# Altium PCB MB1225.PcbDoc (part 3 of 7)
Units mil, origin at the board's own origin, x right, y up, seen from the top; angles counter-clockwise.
Board outline 5000 x 3464.56 mil, 6 copper layers (Top Layer, L2_GND, L3_VCC, L4_SIG, L5_GND, Bottom Layer), stack 62.2 mil thick; 453 components, 378 nets, 1982 pads, 949 vias.

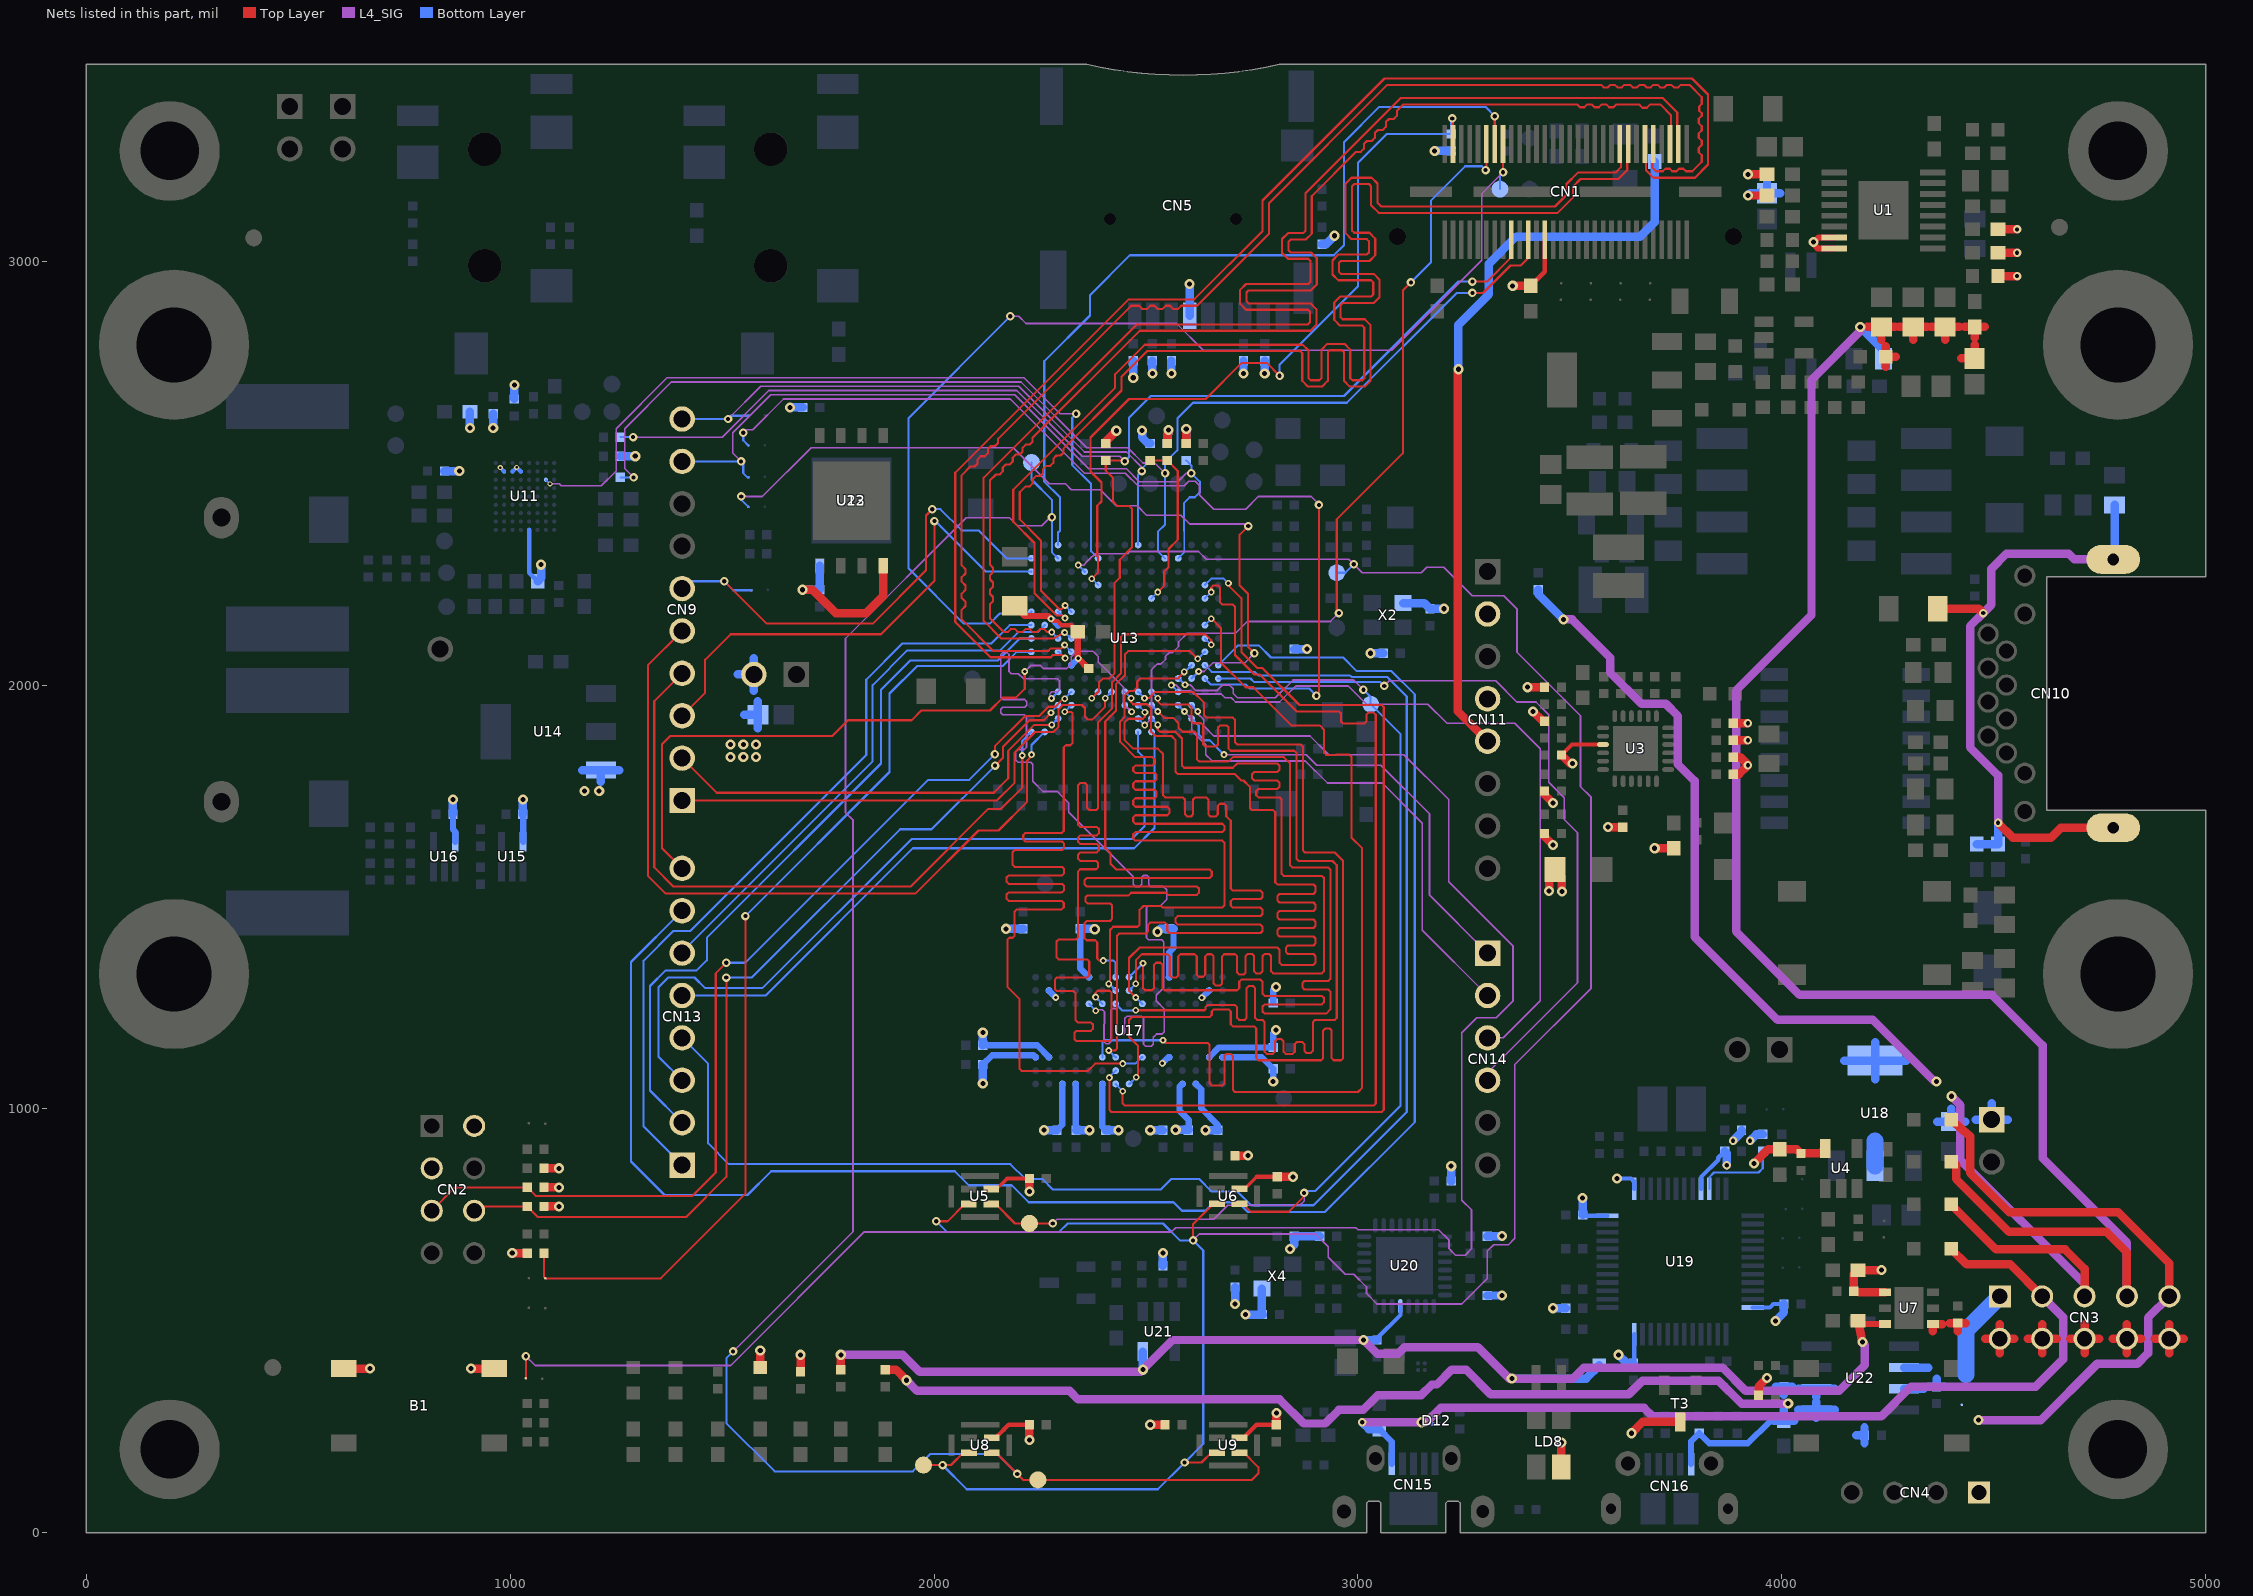
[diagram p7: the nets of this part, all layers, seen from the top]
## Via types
v1: diameter 20, hole 10, Top Layer to Bottom Layer, 354 vias
v2: diameter 24, hole 12, Top Layer to Bottom Layer, 347 vias
v3: diameter 16, hole 8, Top Layer to Bottom Layer, 221 vias
v4: diameter 12, hole 6, Top Layer to Bottom Layer, 27 vias

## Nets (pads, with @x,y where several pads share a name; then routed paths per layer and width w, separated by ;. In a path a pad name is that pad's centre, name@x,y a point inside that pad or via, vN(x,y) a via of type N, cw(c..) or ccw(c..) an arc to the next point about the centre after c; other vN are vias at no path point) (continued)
3V3: B1.1 B1.4 C1.2 C33.2 C38.1 C44.1 C45.1 C48.2 C49.2 C55.1 C56.1 C65.1 C67.2 C71.1 C92.1 C96.2 C98.2 C117.2 C118.2 C123.2 C124.2 C125.2 C126.2 C127.2 C128.2 C130.2 C131.2 C133.2 C134.2 C135.2 C136.2 C137.2 C138.2 C144.1 C147.1 CN1.36 CN2.2 CN2.3 CN5.4 CN11.2 CN11.4 JP4.2 L2.2 R8.1 R17.2 R19.1 R20.1 R30.2 R34.2 R35.1 R37.1 R39.1 R41.1 R43.2 R45.2 R47.2 R51.2 R52.2 R54.1 R56.1 R65.2 R66.2 R67.2 R71.2 R76.2 R79.2 R80.2 R81.2 R82.2 R83.2 R86.2 R87.2 R89.1 R90.1 R91.1 R94.2 R106.2 R107.1 R109.2 R123.2 R125.2 R126.2 R130.1 R134.1 R137.2 R200.1 U3.9 U5.1 U6.1 U7.4 U8.1 U9.1 U11.B2 U11.C2 U11.D2 U11.E9 U12.8 U14.3 U15.5 U16.5 U17.A7 U17.B2 U17.B7 U17.C9 U17.D9 U17.E1 U17.F9 U17.L1 U17.L7 U17.M9 U17.N9 U17.P2 U17.P7 U17.R7 U23.8 X2.4 X4.4 | length 6354.3
  Top Layer w8: U5.1@2145.89,809.28 2172.61,836 ; U6.1@2730.73,809.28 2761.45,840
  Top Layer w10: U8.1@2136,224.67 2145.67,224.67 2159.05,238.05 2159.27,238.05 2165.71,244.49 2165.71,244.71 2176,255 C55.1@2225,255 ; U5.1@2136,809.28 U5.1@2145.89,809.28 ; 2172.61,836 C44.1@2225,836 ; U9.1@2720.61,224.67 2730.5,224.67 2760.83,255 C56.1@2807.57,255 ; U6.1@2720.61,809.28 U6.1@2730.73,809.28 ; 2761.45,840 C45.1@2810,840 ; C1.2@3407.51,2941.92 3440.78,2975.19 CN1.36@3440.78,3050.55 ; C33.2@3480,1835 3504.84,1859.84 U3.9@3578.23,1859.84
  Top Layer w20: B1.4@607.83,387.5 v2(669.5,387.5) ; v2(907.5,387.5) B1.1@962.17,387.5 ; v2(1005,660) R52.2@1040,660 ; R54.1@1080,770 v2(1115,770) ; R56.1@1080,815 v2(1115,815) ; R200.1@1080,860 v2(1115,860) ; R65.2@1590,390 v2(1590,430) ; R66.2@1685,380 v2(1685,420) ; v2(1690,2225) 1713,2225 1768,2170 1840,2170 1880,2210 U23.8@1880,2281.9 ; v2(2225,219) C55.1@2225,255 ; C44.1@2225,836 2225,805.29 v2(2225.29,805.29) ; R17.2@2405,2570 2405,2575 v2(2430,2600) ; v2(2510,255) R71.2@2545,255 ; R19.1@2550,2570 2550,2590 2553,2593 v2(2553,2602) ; R20.1@2595,2570 v2(2595,2604) ; R51.2@2710,890 v2(2741,890) ; C56.1@2807.57,255 v2(2807.57,283) ; C45.1@2810,840 v2(2847,840) ; v2(3365,2941.92) C1.2@3407.51,2941.92 ; v2(3400,1995) R30.2@3440,1995 ; v2(3413,1938) 3436,1915 R34.2@3440,1915 ; R47.2@3440,1650 3440,1643 v2(3460,1623) ; R43.2@3440,1750 3440,1742 v2(3460,1722) ; v2(3451,1514) C38.1@3451,1544 ; C38.1@3451,1551 C38.1@3465,1565 3481,1549 v2(3481,1513) ; C33.2@3480,1835 3500,1815 v2(3506,1815) ; v2(3590,1665) R45.2@3625,1665 ; v2(3700,1615) L2.2@3745,1615 ; R41.1@3885,1790 3899,1790 v1(3920,1811) 3920,1812 3902,1830 R39.1@3885,1830 ; R37.1@3885,1870 v1(3920,1870) ; R35.1@3885,1910 v1(3920,1910) ; R67.2@3945,325 3945,345 v2(3965,365) ; v2(4235,620) C48.2@4180,620 4170,610 C49.2@4170,570 4182.6,567.4 U7.4@4243.48,567.4
  Bottom Layer w9: v4(976.54,2513.25) 985.73,2504.06 U11.B2@985.79,2504.06 ; U11.C2@1005.47,2504.06 U11.C2@1005.47,2504.06 v4(1015.22,2513.76)
  Bottom Layer w10: v4(1015.22,2513.76) 1024.92,2504.06 U11.D2@1025.16,2504.06 ; U11.E9@1044.84,2366.26 1044.84,2265.16 C92.1@1065,2245
  Bottom Layer w15: C118.2@865,1695 865,1660 870.59,1654.41 U16.5@870.59,1630.43 ; C117.2@1030,1695 1030.59,1694.41 U15.5@1030.59,1630.43 ; C130.2@2115,1105 2137,1127 2234.54,1127 U17.A7@2239.53,1122.01 ; C127.2@2115,1150 2243.03,1150 U17.B7@2271.02,1122.01 ; U17.B2@2271.02,1279.49 2271.02,1278.98 v3(2287,1263) ; C138.2@2290,950 2302.52,962.52 U17.C9@2302.52,1059.02 ; U17.D9@2334.02,1059.02 2334.02,950.98 C137.2@2335,950 ; C124.2@2345,1425 2345,1331.49 U17.E1@2365.51,1310.98 ; U17.F9@2397.01,1059.02 2397.01,957.99 C136.2@2405,950 ; v3(2538.61,1108) 2552.62,1122.01 U17.L7@2554.49,1122.01 ; U17.L1@2554.49,1310.98 2554.49,1369.49 2565,1380 C123.2@2565,1425 ; U17.M9@2585.98,1059.02 2579,1052.04 2579,996 2600.84,974.16 2600.84,950.84 C134.2@2600,950 ; U17.N9@2617.48,1059.02 2630,1046.5 2630,1002 2670,962 C133.2@2670,950 ; v3(2631.92,1262.43) U17.P2@2648.98,1279.49 ; U17.P7@2648.98,1122.01 2671.97,1145 C128.2@2800,1145 2800,1179 v2(2807,1186) ; U17.R7@2680.47,1122.01 2772.99,1122.01 C131.2@2800,1095 v2(2800,1065) ; C126.2@2800,1250 2800,1281 v2(2807,1288)
  Bottom Layer w20: C71.1@845,2505 v2(880,2505) ; C118.2@865,1695 v2(865,1730) ; v2(905,2606.83) C67.2@905,2645 ; v2(960,2606.83) C65.1@960,2640 ; R87.2@1010,2675 v2(1010,2707.91) ; C117.2@1030,1695 v2(1030,1730) ; C92.1@1065,2245 1073,2253 v2(1073,2284) ; 1170.5,1799.45 U14.3@1214.02,1799.45 ; 1214.02,1771.43 U14.3@1214.02,1799.45 ; 1257.54,1799.45 U14.3@1214.02,1799.45 ; R94.2@1260,2540 v2(1295,2540) ; 1536.98,2025 JP4.2@1575,2025 ; 1551.97,1930 R109.2@1584.49,1930 ; 1575,1986.98 JP4.2@1575,2025 ; 1575,2063.02 JP4.2@1575,2025 ; 1584.49,1898.48 R109.2@1584.49,1930 ; 1584.49,1961.52 R109.2@1584.49,1930 ; v2(1660,2655) R86.2@1690,2655 ; v2(1690,2225) C96.2@1730,2225 U12.8@1730,2281.46 ; v2(2115,1060) C130.2@2115,1105 ; C127.2@2115,1150 v2(2115,1180) ; v2(2170,1425) C125.2@2210,1425 ; v2(2259,950) C138.2@2290,950 ; C137.2@2335,950 v2(2367,950) ; C124.2@2345,1425 2378,1425 v2(2379,1424) ; C136.2@2405,950 v2(2435,950) ; v2(2470,2725) R83.2@2470,2765 ; v2(2490.82,2600.29) 2490.82,2584.18 2505,2570 R91.1@2510,2570 ; v2(2510,950) C135.2@2540,950 ; v2(2515,2735) R82.2@2515,2765 ; v2(2527,1418) 2534,1425 C123.2@2555,1425 C123.2@2565,1425 ; R130.1@2540,630 v2(2540,660) ; R90.1@2550,2570 2550,2590 2553,2593 v2(2553,2602) ; v2(2560,2735) R81.2@2560,2765 ; v2(2570,950.84) C134.2@2600.84,950.84 ; R89.1@2595,2570 v2(2595,2604) ; CN5.4@2602.99,2871.21 v2(2602.99,2946) ; v2(2640,950) C133.2@2670,950 ; v2(2710,540) R134.1@2710,580 ; v2(2730,2735) R80.2@2730,2765 ; v2(2735,515) C147.1@2775,515 2773.58,516.42 X4.4@2773.58,576.46 ; v2(2780,2735) R79.2@2780,2765 ; v2(2840,670) 2850,680 C144.1@2850,700 R126.2@2910,700 ; R106.2@2850,2085 v2(2880,2085) ; R76.2@2915,3040 2925,3040 v2(2945,3060) ; v2(3030,2075) R107.1@3060,2075 ; X2.4@3106.42,2193.54 3156.46,2193.54 C98.2@3170,2180 v2(3203.12,2180) ; v2(3181,3260) R8.1@3220,3260 ; R123.2@3220,830 v2(3220,865) ; R137.2@3305,560 v2(3340,560) ; R125.2@3305,700 v2(3340,700)
  other v2: 1175,1750 1210,1750 1520,1830 1550,1830 1580,1830 1520,1860 1550,1860 1580,1860
3V3_ST_LINK: C41.1 C42.2 C140.1 C143.2 C146.2 C151.2 CN4.1 LD8.4 R118.2 R120.1 R138.2 T3.3 U4.5 U19.1 U19.9 U19.24 U19.36 U19.48 | length 1019.4
  Top Layer w20: LD8.4@3479.53,155.94 v2(3479.53,213) ; v2(3645,235) 3671.69,261.69 T3.3@3760,261.69 ; v2(3933.98,871.31) 3967.67,905 C41.1@3995,905 4035,905 C42.2@4045,895 4090.36,895 U4.5@4102.6,907.24
  Bottom Layer w10: C143.2@3530,750 3531.73,748.27 U19.48@3588.74,748.27 ; v2(3611,836) 3644,836 3651.73,828.27 U19.1@3651.73,811.26 ; C151.2@3650,400 3651.73,401.73 U19.36@3651.73,468.74 ; U19.9@3809.21,811.26 3809.21,839.21 3850,880 3850,885 C140.1@3865,900 ; U19.24@3931.26,531.73 3971.73,531.73 3980,540 C146.2@4005,540
  Bottom Layer w20: v2(3460,530) R138.2@3490,530 ; C143.2@3530,750 v2(3530,790) ; v2(3615,420) 3635,400 C151.2@3650,400 ; C140.1@3865,900 3870,895 v1(3870,867.5) ; v1(3885,925) 3905,945 R118.2@3905,950 ; v1(3925,925) 3940,940 R120.1@3955,940 ; v2(3985,500) 4005,520 C146.2@4005,540
5V: C50.2 C51.2 C150.1 CN3.2 CN3.4 CN3.6 CN3.8 CN3.10 CN11.5 D11.1 L4.1 R58.1 U7.1 U7.6 U20.21 U21.5 | length 5713.9
  Top Layer w15: C51.2@4180,500 4197.4,492.6 U7.6@4243.48,492.6
  Top Layer w20: R58.1@1780,385 v2(1780,420) ; v2(3237,2745) 3235,2743 3235,1938.5 CN11.5@3305.8,1867.7 ; C51.2@4180,500 v2(4190,450) ; 4356.52,475.58 U7.1@4356.52,492.6 4378.54,492.6 ; 4395.98,495 C50.2@4415,495 ; 4415,475.98 C50.2@4415,495 ; 4434.02,495 C50.2@4415,495 ; 4480.2,458 CN3.2@4514.22,458 ; 4514.22,423.98 CN3.2@4514.22,458 ; 4514.22,492.02 CN3.2@4514.22,458 ; 4548.24,458 CN3.2@4514.22,458 ; 4580.2,458 CN3.4@4614.22,458 ; 4614.22,423.98 CN3.4@4614.22,458 ; 4614.22,492.02 CN3.4@4614.22,458 ; 4648.24,458 CN3.4@4614.22,458 ; 4680.2,458 CN3.6@4714.22,458 ; 4714.22,423.98 CN3.6@4714.22,458 ; 4714.22,492.02 CN3.6@4714.22,458 ; 4748.24,458 CN3.6@4714.22,458 ; 4780.2,458 CN3.8@4814.22,458 ; 4814.22,423.98 CN3.8@4814.22,458 ; 4814.22,492.02 CN3.8@4814.22,458 ; 4848.24,458 CN3.8@4814.22,458 ; 4880.2,458 CN3.10@4914.22,458 ; 4914.22,423.98 CN3.10@4914.22,458 ; 4914.22,492.02 CN3.10@4914.22,458 ; 4948.24,458 CN3.10@4914.22,458
  L4_SIG w20: v2(1780,420) 1926,420 1966,380 2487.6,380 v2(2492.6,385) 2562.6,455 v2(3013,455) 3045,423 3095.13,423 3110.13,438 3283,438 3357,364 v2(3363,364) 3507,364 3533,390 3860,390 3915,335 4135,335 4196,396 4196,444 v2(4190,450)
  Bottom Layer w10: C150.1@3045,455 3045,459 3100.16,514.16 U20.21@3100.16,534.72
  Bottom Layer w20: v2(2492.6,385) U21.5@2492.6,427.76 ; v2(3013,455) C150.1@3045,455 ; v2(3237,2745) 3237,2850 3309,2922 3309,2994 3373,3058 3666,3058 3700,3092 L4.1@3700,3235 ; v2(3363,364) 3538.29,364 D11.1@3569.29,395
5V_POE: C13.2 C14.2 C15.2 C16.2 CN3.7 D6.1 R11.2 R16.2 R84.2 | length 4278.5
  Top Layer w20: 4201.98,2845 C13.2@4235,2845 ; 4235,2814.48 C13.2@4235,2845 ; 4245,2750.98 R11.2@4245,2775 ; 4245,2799.02 R11.2@4245,2775 ; 4268.02,2845 C13.2@4235,2845 ; 4268.52,2775 R11.2@4245,2775 ; 4276.98,2845 C14.2@4310,2845 ; 4310,2814.48 C14.2@4310,2845 ; 4343.02,2845 C14.2@4310,2845 ; 4351.98,2845 C15.2@4385,2845 ; 4385,2814.48 C15.2@4385,2845 ; D6.1@4399.29,875 4411,868.29 4411,835 4536,710 4766,710 4814.22,661.78 CN3.7@4814.22,558 ; 4418.02,2845 C15.2@4385,2845 ; 4423.48,2770.51 R16.2@4455,2770.51 4455,2803.03 ; 4430.98,2845 C16.2@4455,2845 ; 4455,2819.48 C16.2@4455,2845 ; 4479.02,2845 C16.2@4455,2845
  L4_SIG w20: v2(4185,2845) 4185,2835 4070,2720 4070,2165 3892,1987 3892,1419 4042,1269 4496,1269 4615,1150 4615,884 4814.22,684.78 CN3.7@4814.22,558
  Bottom Layer w20: v2(4185,2845) 4240,2790 R84.2@4240,2770
5V_ST_LINK: C152.2 CN3.1 SB23.2 U22.6 U22.7 | length 378.7
  Bottom Layer w20: U22.7@4288.3,340 4335,340 ; U22.6@4288.3,390 4345.98,390 ; 4345.98,345 C152.2@4365,345 ; 4365,364.02 C152.2@4365,345 ; 4384.02,345 C152.2@4365,345
  Bottom Layer w40: 4434,374 4434,477.78 CN3.1@4514.22,558
5V_USB_CHARGER: C155.2 CN3.9 CN16.1 D5.1 R59.2 R144.2 R147.2 R150.2 SB23.1 U22.1 U22.2 | length 4390.4
  Top Layer w20: R59.2@1885,385 1910,385 v2(1935,360) ; D5.1@4399.29,975 4444,935.29 4444,849 4537,756 4794,756 4914.22,635.78 CN3.9@4914.22,558
  L4_SIG w20: v2(1935,360) 1960,335 2320,335 2340,315 2815,315 2872,258 2923,258 2955,290 3012,290 3047,325 3149.49,325 3174.49,350 3186.4,350 3221.4,385 3255,385 3313,327 3639,327 3671,359 3851,359 3905,305 v2(4015,305) ; v2(4464,266) 4611,266 4744,399 4839,399 4864,424 4864,507.78 CN3.9@4914.22,558
  Bottom Layer w14: CN16.1@3786.18,162.4 3786.18,216.18 R147.2@3805,235
  Bottom Layer w15: R147.2@3805,235 3829,211 3920,211 3970,261
  Bottom Layer w20: 3980.98,265 C155.2@4005,265 ; 3985.98,345 R144.2@4005,345 ; 4005,290.52 C155.2@4005,265 ; 4005,325.98 R144.2@4005,345 ; 4024.02,345 R144.2@4005,345 ; 4029.02,265 C155.2@4005,265 ; 4038.68,290 U22.1@4081.7,290 ; 4038.68,340 U22.2@4081.7,340 ; 4081.7,270.98 U22.1@4081.7,290 ; 4081.7,309.02 U22.1@4081.7,290 ; 4081.7,320.98 U22.2@4081.7,340 ; 4124.72,290 U22.1@4081.7,290 ; 4124.72,340 U22.2@4081.7,340 ; 4175.98,230 R150.2@4195,230 ; 4195,210.98 R150.2@4195,230 ; 4195,249.02 R150.2@4195,230
5V_USB_HS: CN3.3 CN15.1 D8.1 D12.A1 L7.2 | length 2332.1
  Top Layer w20: D8.1@4399.29,670 4436.15,633.14 4539.08,633.14 CN3.3@4614.22,558
  L4_SIG w20: v1(3010,261) v2(3150,261) 3161.03,261 3194.98,295 3675,295 3695,275 4235,275 4305,345 4599,345 4664,410 4664,508.22 CN3.3@4614.22,558
  Bottom Layer w8: v2(3150,261) 3153.87,257.13 D12.A1@3177.13,257.13
  Bottom Layer w15: L7.2@3050,245 3079.69,215.31 CN15.1@3079.69,162.8
  Bottom Layer w20: v1(3010,261) 3026,245 L7.2@3050,245
AGND: C6.1 C7.1 C10.2 C11.2 R6.2 R74.2 U1.15 U1.16 | length 447.6
  Top Layer w14: U1.16@4123.86,3030.43 4084.57,3030.43 4075,3040 v2(4075,3045) 4086.02,3056.02 U1.15@4123.86,3056.02
  Top Layer w20: v2(3920,3155) C7.1@3965,3155 ; v2(3920,3205) C6.1@3965,3205 ; R6.2@4510,2965 v1(4555,2965) ; C11.2@4510,3020 v1(4555,3020) ; C10.2@4510,3075 v1(4555,3075)
  Bottom Layer w20: v2(3920,3155) 3925.51,3160.51 R74.2@3965,3160.51 ; 3965,3193.03 R74.2@3965,3160.51 ; 3996.52,3160.51 R74.2@3965,3160.51
AIN_1: R119.2 R120.2 U19.10 | length 247.5
  Bottom Layer w5: U19.10@3828.9,811.26 3828.9,838.9 3840,850 3945,850 3955,860 R120.2@3955,900 R119.2@4000,900
ARD_A0: CN14.1 U13.P3 | length 1051.7
  L4_SIG w4: v3(2684,1836) 2878,1836 2903,1811 3054,1811 3169,1696 3169,1504.5 CN14.1@3305.8,1367.7
  Bottom Layer w5: U13.P3@2607.48,1921.02 2624.48,1904.02 2624.48,1883.52 2638,1870 2650,1870 v3(2684,1836)
ARD_A1: CN14.2 U13.N4 | length 1191.6
  L4_SIG w4: v3(2590.83,1937.67) 2608,1920.5 2608,1892 2641,1859 2641,1836 2656,1821 2876,1821 2928,1769 3057,1769 3152,1674 3152,1421.5 CN14.2@3305.8,1267.7
  Bottom Layer w5: U13.N4@2575.98,1952.52 v3(2590.83,1937.67)
ARD_A2: CN14.3 U13.M4 | length 1741.6
  L4_SIG w4: v3(2560,2000) 2571.41,2000 2585.2,1986.21 2605.47,1986.21 2612.68,1979 2677.22,1979 2686.2,1970.02 2700.98,1970.02 2711,1960 2815,1960 2853,1998 2977,1998 3020,1955 3165,1955 3210,1910 3370,1910 3430,1850 3430,1255 3342.7,1167.7 CN14.3@3305.8,1167.7
  Bottom Layer w5: v3(2560,2000) U13.M4@2575.98,1984.02
ARD_A3: CN14.4 U13.L1 | length 1803.3
  L4_SIG w4: v1(3062,1998) 3074,2010 3325,2010 3375,1960 3420,1960 3450,1930 3450,1771 3487,1734 3487,1683 3518,1652 3518,1298 3305.8,1085.8 CN14.4@3305.8,1067.7
  Bottom Layer w5: U13.L1@2670.47,2015.51 2746.49,2015.51 2755,2007 3053,2007 v1(3062,1998)
ARD_A4: SB14.1 U13.L3 | length 1847.5
  Top Layer w5: v1(2741,2375) 2721,2355 2721,2235 2741,2215 2741,2089.77 v1(2755.75,2075.02)
  L4_SIG w4: v1(1545,2445) 1595,2445 1710,2560 2187,2560 2272,2475 2310,2475 2324,2461 2392,2461 2430,2423 2479,2423 2501.16,2400.84 2582.16,2400.84 2603,2380 2736,2380 v1(2741,2375) ; v3(2624,2032) 2637,2032 2658,2053 2733.73,2053 v1(2755.75,2075.02)
  Bottom Layer w5: v1(1545,2445) 1545,2437.32 SB14.1@1561.99,2420.33 ; U13.L3@2607.48,2015.51 2616.96,2024.99 ; 2616.99,2024.99 v3(2624,2032)
ARD_A5: SB12.1 U13.L2 | length 2310.3
  Top Layer w5: v1(2902,1975) 2903,1975 2908,1980 v1(2908,2425.01)
  L4_SIG w4: v1(1550,2595) 1557.5,2602.5 1572.5,2602.5 1645,2675 2180,2675 2355,2500 2451.22,2500 2481.22,2470 2590,2470 2601,2481 2616.05,2481 2626,2471.05 2626,2449 2660,2415 2735,2415 2765,2445 2890,2445 2908,2427 v1(2908,2425.01)
  Bottom Layer w5: v1(1550,2595) 1550,2577.32 SB12.1@1561.99,2565.33 ; U13.L2@2638.98,2015.51 2653.49,2001 2736,2001 2745,1992 2885,1992 v1(2902,1975)
ARD_D0: CN13.1 U13.G15 | length 1866.6
  Bottom Layer w5: CN13.1@1405.8,867.7 1315,958.5 1315,1350 1385,1420 1425,1420 1840,1835 1840,2013 1925,2098 2135,2098 2178.5,2141.5 U13.G15@2229.53,2141.5
ARD_D1: CN13.2 U13.H15 | length 1725.9
  Bottom Layer w5: CN13.2@1405.8,967.7 1330,1043.5 1330,1290 1367,1327 1440,1327 1464,1351 1464,1404 1875,1815 1875,1989 1944,2058 2150,2058 2202,2110 U13.H15@2229.53,2110
ARD_D2: CN13.3 U13.R7 | length 1795.4
  Bottom Layer w5: CN13.3@1405.8,1067.7 1350,1123.5 1350,1287 1373,1310 1435,1310 1460,1285 1595,1285 1947,1637 2466,1637 2496.35,1667.35 2496.35,1827.65 2481.5,1842.5 U13.R7@2481.5,1889.53
ARD_D3: CN13.4 U13.K2 | length 3581
  Bottom Layer w5: CN13.4@1405.8,1167.7 1467,1106.5 1467,919 1516,870 2180,870 2215,835 2255,835 2280,810 2535,810 2560,835 2625,835 2655,805 2716,805 2748,773 2895,773 3115,993 3115,1973 3069,2019 2985,2019 2981,2023 2765,2023 2756.9,2031.1 2654.89,2031.1 U13.K2@2638.98,2047.01
ARD_D4: CN13.5 U13.R6 | length 1507.4
  Bottom Layer w5: CN13.5@1405.8,1267.7 1602.7,1267.7 1950,1615 2472,1615 2520,1663 2520,1882.52 U13.R6@2512.99,1889.53
ARD_D5: CN13.6 U13.G14 | length 1283
  Bottom Layer w5: CN13.6@1405.8,1367.7 1405.8,1370.8 1855,1820 1855,2000 1937,2082 2156,2082 2199,2125 2244.52,2125 U13.G14@2261.02,2141.5
ARD_D6: CN13.7 U13.K1 | length 4230
  Bottom Layer w5: CN13.7@1405.8,1467.7 1285,1346.9 1285,876 1364,797 1560,797 1616,853 2049,853 2082,820 2183,820 2223,780 2565,780 2585,760 2640,760 2660,780 2717,780 2740,757 2922,757 3134,969 3134,1978 3079,2033 2997,2033 2965,2065 2795,2065 2767,2093 2716.46,2093 U13.K1@2670.47,2047.01
ARD_D7: CN13.8 U13.N8 | length 1663.7
  Top Layer w5: CN13.8@1405.8,1567.7 1358,1615.5 1358,1860 1378,1880 1760,1880 1797,1917 1947,1917 1970,1940 2132,1940 2162,1970 2193,1970 2214,1991 v3(2214,2032)
  L4_SIG w4: v3(2214,2032) 2228,2046 2251,2046 2258,2039 2313,2039 2324,2050 2324,2067 2337,2080 2375,2080 2387.5,2067.5 2387.5,2054.5 2447,1995 2447,1955 2465,1937 v3(2466,1937)
  Bottom Layer w4: U13.N8@2450,1952.52 2450.48,1952.52 v3(2466,1937)
ARD_D8: CN9.1 U13.M9 | length 1237
  Top Layer w5: CN9.1@1405.8,1727.7 2147.7,1727.7 2190,1770 2190,1841 2238.25,1889.25 2281.26,1889.25 2294,1901.99 2294,1942.99 2304.01,1953 2349,1953 2356,1946 2356,1925 2362,1919 2374,1919 2403.65,1948.65 v3(2403.65,1969.17)
  Bottom Layer w5: v3(2403.65,1969.17) U13.M9@2418.5,1984.02
ARD_D9: CN9.2 U13.P13 | length 1031
  Top Layer w5: CN9.2@1405.8,1827.7 1487.5,1746 2141,1746 2175.08,1780.08 2175.08,1844.92 2236.33,1906.17 v3(2277.67,1906.17)
  Bottom Layer w5: v3(2277.67,1906.17) U13.P13@2292.52,1921.02
ARD_D10: CN9.3 U13.C15 | length 1191.8
  Top Layer w5: CN9.3@1405.8,1927.7 1460,1981.9 1460,2060 1520,2120 1875,2120 2001,2246 v1(2001,2387)
  Bottom Layer w5: v1(2001,2387) 2003,2387 2122,2268 2229.01,2268 U13.C15@2229.53,2267.48
ARD_D11: CN9.4 U13.R15 | length 1608.6
  Top Layer w5: CN9.4@1405.8,2027.7 1340,1961.9 1340,1570 1385,1525 1945,1525 2128,1708 2158,1708 2208,1758 v3(2208,1834)
  Bottom Layer w5: v3(2208,1834) 2208,1868 U13.R15@2229.53,1889.53
ARD_D12: CN9.5 U13.R14 | length 1795
  Top Layer w5: CN9.5@1405.8,2127.7 1325,2046.9 1325,1550 1367,1508 1956,1508 2105,1657 2152,1657 2219,1724 2219,1821 2230,1832 v3(2230,1836)
  Bottom Layer w5: v3(2230,1836) 2230,1858.51 U13.R14@2261.02,1889.53
ARD_D13: CN9.6 SB15.2 U13.B15 | length 1180.7
  Top Layer w5: v1(1505,2245) 1605,2145 1855,2145 1981,2271 1981,2400 v1(1996,2415)
  Bottom Layer w5: CN9.6@1405.8,2227.7 1423.1,2245 v1(1505,2245) 1526.19,2223.81 SB15.2@1569.17,2223.81 ; v1(1996,2415) 2015,2415 2065,2365 2105,2365 2171.02,2298.98 U13.B15@2229.53,2298.98
ARD_D14: CN9.9 R89.2 SB13.1 U13.B4 | length 1745.1
  L4_SIG w4: v1(1544.67,2527.7) 1525,2547.37 1525,2595 1615,2685 2190,2685 2365,2510 2453.95,2510 2483.95,2480 2575,2480 2595,2500 v1(2607,2500)
  Bottom Layer w4: U13.B4@2575.98,2298.98 2590,2313 2590,2364
  Bottom Layer w5: CN9.9@1405.8,2527.7 v1(1544.67,2527.7) 1550,2522.37 1550,2500 1559.67,2490.33 SB13.1@1561.99,2490.33 ; 2590,2364 2590,2430 2603,2443 2615,2443 2627,2455 2627,2480 v1(2607,2500) 2607,2518 R89.2@2595,2530
ARD_D15: CN9.10 R91.2 SB11.1 U13.A7 | length 1466.8
  L4_SIG w4: v1(1514,2627.7) 1591.3,2705 2200,2705 2355,2550 2454,2550 2490,2514 v1(2490,2505)
  Bottom Layer w5: CN9.10@1405.8,2627.7 v1(1514,2627.7) 1521.63,2635.33 SB11.1@1561.99,2635.33 ; U13.A7@2481.5,2330.47 2481.5,2496.5 v1(2490,2505) 2490,2510 R91.2@2510,2530
Audio_INT: U11.G3 U13.B10 | length 1826.2
  L4_SIG w3.5: v4(1093.96,2474.62) 1115.38,2474.62 1120,2470
  L4_SIG w4: 1120,2470 1215,2470 1250,2505 1250,2605 1370,2725 2212.06,2725 2297.06,2640 v1(2335,2640)
  Bottom Layer w3.5: U11.G3@1084.21,2484.37 v4(1093.96,2474.62)
  Bottom Layer w5: v1(2335,2640) 2326,2631 2326,2519 2370.5,2474.5 2370.5,2315.49 U13.B10@2387.01,2298.98
AUDIO_SCL: CN1.44 R17.1 R88.1 U13.M10 | length 3230.1
  Top Layer w5: v3(2372.16,1969.17) 2389.15,1986.16 2389.15,2006.67 2397.64,2015.16 2413.16,2015.16 2426,2028 2426,2241 2438,2253 2438,2296 2467,2325 2467,2416 2460.5,2422.5 2432.49,2422.5 2430.99,2424 2422,2433.01 2422,2489 2405,2506 R17.1@2405,2530 2448,2530 v1(2450,2528) ; v1(3270,2952) 3305,2952 3362.04,3009.04 CN1.44@3362.04,3050.55
  L4_SIG w4: v1(1290,2585) 1500,2585 1610,2695 2195,2695 2350,2540 2438,2540 v1(2450,2528)
  Bottom Layer w5: R88.1@1260,2585 v1(1290,2585) ; v3(2372.16,1969.17) U13.M10@2387.01,1984.02 ; v1(2450,2528) 2460,2538 2460,2631 2511,2682 2967,2682 3237,2952 v1(3270,2952)
AUDIO_SDA: CN1.40 R90.2 R95.1 U13.B5 | length 2947.1
  Top Layer w5: v1(3270,2925) 3295,2925 3360,2990 3384,2990 3401.41,3007.41 CN1.40@3401.41,3050.55
  L4_SIG w4: v1(1291,2490) 1270,2511 1270,2605 1380,2715 2205,2715 2360,2560 2457,2560 2493,2524 2521,2524 v1(2545,2500)
  Bottom Layer w5: R95.1@1260,2490 v1(1291,2490) ; U13.B5@2544.49,2298.98 2528.53,2314.94 2528.53,2362.53 2545,2379 v1(2545,2500) 2545,2525 R90.2@2550,2530 2574,2554 2574,2629 2611,2666 2974,2666 3233,2925 v1(3270,2925)
B_USER: SB9.1 U13.N3 | length 4391.8
  Top Layer w5: SB9.1@1037.13,364.47 v1(1037.13,416.87)
  L4_SIG w4: v1(1037.13,416.87) 1059,395 1520,395 1835,710 2560,710 2570,720 2995,720 3000,715 3190,715 3215,690 3215,670 3230,655 3253,655 3268,670 3268,762 3245,785 3245,1180 3280,1215 3326,1215 3366,1255 3366,1384 3214,1536 3214,1730 3108,1836 2931,1836 2887,1880 2660,1880 2636.33,1903.67 2636.33,1918.67 2622.33,1932.67 v3(2622.33,1937.67)
  Bottom Layer w5: U13.N3@2607.48,1952.52 v3(2622.33,1937.67)
BOOT0: R18.2 R19.2 U13.E6 | length 401.6
  Top Layer w5: R18.2@2510,2530 R19.2@2550,2530 2575,2505 2575,2343 2553,2321 2553,2278 2543,2268 2543,2234.5 v3(2527.84,2219.34)
  Bottom Layer w4: U13.E6@2512.99,2204.49 v3(2527.84,2219.34)
CEC: CN1.47 U13.A13 | length 2007.1
  Top Layer w5: CN1.47@3322.67,3276.53 v1(3322.67,3341.67)
  Bottom Layer w5: U13.A13@2292.52,2330.47 2292.52,2360 2297,2364.48 2297,2443 2260,2480 2260,2764 2368,2872 2368,2920 2462,3014 2943,3014 2967,3038 2967,3281 3050,3364 3301,3364 3322.67,3342.33 v1(3322.67,3341.67)
CEC_CLK: CN1.45 TP2.1 U13.F15 | length 2620.8
  Top Layer w5: v1(3342.35,3210) CN1.45@3342.35,3276.53
  L4_SIG w4: v1(2180,2870) 2200,2870 2217,2853 2572,2853 2635,2790 3080,2790 3292,3002 3292,3159.65 v1(3342.35,3210)
  Bottom Layer w5: v1(2180,2870) 1940,2630 1940,2275 2070,2145 2131.22,2145 2155.22,2169 2225.54,2169 U13.F15@2229.53,2172.99 ; TP2.1@3335,3170 3335,3202.65 v1(3342.35,3210)
CHASSIS: C89.1 C121.1 C122.2 CN10.13 CN10.14 R96.1 | length 1592.4
  Top Layer w20: C89.1@4368,2180 4465,2180 v1(4475,2170) ; v1(4510,1675) 4545,1640 4635,1640 4658.46,1663.46 CN10.14@4781.85,1663.46
  L4_SIG w20: v1(4510,1675) 4510,1787 4444,1853 4444,2139 v1(4475,2170) 4494,2189 4494,2274 4530,2310 4676.54,2310 4690,2296.54 CN10.13@4781.85,2296.54
  Bottom Layer w20: C122.2@4460,1625 C121.1@4510,1625 v1(4510,1675) ; CN10.13@4781.85,2296.54 4785,2299.69 R96.1@4785,2425
DFSDM_CKOUT: TP5.1 TP102.1 U5.3 U6.3 U8.3 U9.3 U13.C11 | length 6007.5
  Top Layer w5: TP5.1@1975,160 v1(2020,160) 2040,160 2071.21,191.21 U8.3@2082.86,191.21 ; v1(2005,735) 2032,735 2072.82,775.82 U5.3@2082.86,775.82 ; v1(2591,166) 2631,166 2656.21,191.21 U9.3@2667.47,191.21 ; v1(2611,690) 2611,728 2658.82,775.82 U6.3@2667.47,775.82
  L4_SIG w4: v3(2340,2283) 2353,2283 2358,2288 2358,2288.29 2366.2,2296.49 2366.49,2296.49 2380,2310 2457,2310 2462,2315 2624,2315 2642,2297 2978,2297 v1(2990,2285) 3010,2265 3149,2265 3162,2278 3202.46,2278 3269.81,2210.65 3344.35,2210.65 3375,2180 3375,2078 3525,1928 3525,1760 3550,1735 3550,1285 3370,1105 3370,695 3355,680 3320,680 3305,665 3305,600 3245,540 3045,540 3020,565 3020,580 2990,610 2970,610 2930,650 2930,675 2900,705 2626,705 v1(2611,690)
  Bottom Layer w5: v1(2005,735) 2030,710 2295,710 2315,730 2540,730 2580,690 v1(2611,690) 2635,666 2635,210 v1(2591,166) 2528,103 2077,103 v1(2020,160) ; v3(2340,2283) 2341,2282 U13.C11@2355.51,2267.48 ; TP102.1@2950,2265 2970,2265 v1(2990,2285)
DFSDM_DATIN1: TP101.1 TP103.1 U5.4 U6.4 U13.L4 | length 2810
  Top Layer w5: U5.4@2136,775.82 2145.18,775.82 2191,730 TP103.1@2225,730 v1(2280,730) ; U6.4@2720.61,775.82 2729.18,775.82 2747.5,757.5 2836.5,757.5 2873,794 v1(2873,802)
  L4_SIG w4: v1(2280,730) 2290,740 2660,740 2693,773 2863,773 2873,783 v1(2873,802) ; v3(2592,2001) 2604,2001 2618,1987 2667,1987 2680,2000 2697,2000 2706,1991 2706,1980 2716,1970 2805,1970 2847,2012 2990,2012 v1(3013,1989)
  Bottom Layer w5: U13.L4@2575.98,2015.51 2577.49,2015.51 v3(2592,2001) ; v1(2873,802) 2877.5,806.5 2899.5,806.5 3100,1007 3100,1885 TP101.1@3030,1955 3030,1972 v1(3013,1989)
DFSDM_DATIN5: TP100.1 TP104.1 U8.4 U9.4 U13.B13 | length 4362.1
  Top Layer w5: U8.4@2136,191.21 2143.79,191.21 v1(2196,139) 2210,125 TP104.1@2245,125 2750,125 2765,140 2765,155 2728.79,191.21 U9.4@2720.61,191.21
  L4_SIG w4: v1(1526,428) 1809,711 1809,1681 1791,1699 1791,2110 2076,2395 2178,2395 2197,2376 2254,2376 2274,2396 v1(2278,2396)
  Bottom Layer w5: v1(1526,428) 1510,412 1510,259 1624,145 1950,145 1991,186 2149,186 v1(2196,139) ; TP100.1@2230,2525 2230,2485 2278,2437 v1(2278,2396) 2278,2313.5 U13.B13@2292.52,2298.98
DSI.DSI_CK_N: CN1.5 U13.H13 | length 3263.4
  Top Layer w5.1: v3(2277.5,2125) 2267,2125 2260,2132 2249.79,2132 2242.79,2125 2232.59,2125 2225.59,2132 2215.39,2132 2208.39,2125 2198.19,2125 2191.19,2132 2180.99,2132 2173.99,2125 2165,2125 2132,2158 2132,2190.52 2139,2197.52 2139,2207.72 2132,2214.72 2132,2224.92 2139,2231.92 2139,2242.12 2132,2249.12 2132,2259.32 2139,2266.32 2139,2276.52 2132,2283.52 2132,2483 2145.93,2496.93 2154.93,2496.93 2162.14,2504.14 2162.14,2513.14 2169.35,2520.35 2178.35,2520.35 2185.56,2527.56 2185.56,2536.56 2192.77,2543.77 2201.77,2543.77 2208.98,2550.98 2208.98,2559.98 2216.19,2567.19 2225.19,2567.19 2232.4,2574.4 2232.4,2583.4 2485,2836 2888.22,2836 2902,2849.78 2902,2886.76 2888.22,2900.54 2742,2900.54 2737,2905.54 2737,2926.14 2742,2931.14 2889.22,2931.14 2903,2944.92 2903,3006.86 2889.22,3020.64 2841.1,3020.64 2836,3025.74 2836,3046.14 2841.1,3051.24 2877.12,3051.24 2891,3065.12 2891,3153.52 2995.29,3257.81 3006.81,3257.81 3014.02,3265.02 3014.02,3276.54 3021.23,3283.75 3032.75,3283.75 3039.96,3290.96 3039.96,3302.48 3047.17,3309.69 3058.69,3309.69 3065.9,3316.9 3065.9,3328.42 3073.11,3335.63 3084.63,3335.63 3091.84,3342.84 3091.84,3354.36 3107.48,3370 3516.78,3370 3523.78,3363 3533.98,3363 3540.98,3370 3551.18,3370 3558.18,3363 3568.38,3363 3575.38,3370 3585.58,3370 3592.58,3363 3602.78,3363 3609.78,3370 3663.01,3370 3671.01,3362 3681.21,3362 3689.21,3370 3713,3370 3738.39,3344.61 3738.39,3321 3736.05,3318.66 CN1.5@3736.05,3276.53
  Bottom Layer w5.1: v3(2277.5,2125) U13.H13@2292.52,2110
DSI.DSI_CK_P: CN1.3 U13.H12 | length 3265
  Top Layer w5.1: v3(2308,2124) 2281,2110 2158.78,2110 2117,2151.78 2117,2489.22 2478.78,2851 2882,2851 2887,2856 2887,2880.54 2882,2885.54 2735.78,2885.54 2722,2899.32 2722,2932.36 2735.78,2946.14 2883,2946.14 2888,2951.14 2888,3000.64 2883,3005.64 2834.88,3005.64 2821,3019.52 2821,3052.36 2834.88,3066.24 2870.9,3066.24 2876,3071.34 2876,3159.74 3101.26,3385 3719.22,3385 3753.39,3350.83 3753.39,3321 3755.74,3318.65 CN1.3@3755.74,3276.53
  Bottom Layer w5.1: v3(2308,2124) U13.H12@2324.02,2110
DSI.DSI_D0_N: CN1.11 U13.J13 | length 3288
  Top Layer w5.1: v3(2309.17,2063.65) 2301.82,2071 2280.67,2071 2275.22,2065.55 2133.23,2065.55 2050,2148.78 2050,2501 2459,2910 2614,2910 2775,3071 2775,3143.22 3062.78,3431 3788.22,3431 3826,3393.22 3826,3228 3795,3197 3697,3197 3679.34,3214.66 3679.34,3231.66 3677,3234 CN1.11@3677,3276.53
  Bottom Layer w4: U13.J13@2292.52,2078.5 2294.32,2078.5 v3(2309.17,2063.65)
DSI.DSI_D0_P: CN1.9 U13.J12 | length 3284.5
  Top Layer w5.1: v3(2308,2094.52) 2299.48,2086 2274.45,2086 2269,2080.55 2139.45,2080.55 2065,2155 2065,2177.44 2074,2186.44 2074,2196.64 2065,2205.64 2065,2215.84 2074,2224.84 2074,2235.04 2065,2244.04 2065,2254.24 2074,2263.24 2074,2273.44 2065,2282.44 2065,2494.78 2085.76,2515.54 2095.54,2515.54 2102.76,2522.76 2102.76,2532.54 2109.98,2539.76 2119.76,2539.76 2126.98,2546.98 2126.98,2556.76 2134.2,2563.98 2143.98,2563.98 2151.2,2571.2 2151.2,2580.98 2465.22,2895 2483.78,2895 2491.78,2887 2501.98,2887 2509.98,2895 2520.18,2895 2528.18,2887 2538.38,2887 2546.38,2895 2556.58,2895 2564.58,2887 2574.78,2887 2582.78,2895 2620.22,2895 2790,3064.78 2790,3137 3069,3416 3573.8,3416 3579.8,3410 3590,3410 3596,3416 3606.2,3416 3612.2,3410 3622.4,3410 3628.4,3416 3642.29,3416 3648.29,3410 3658.49,3410 3664.49,3416 3674.69,3416 3680.69,3410 3690.89,3410 3696.89,3416 3707.09,3416 3713.09,3410 3723.29,3410 3729.29,3416 3739.49,3416 3745.49,3410 3755.69,3410 3761.69,3416 3782,3416 3811,3387 3811,3371.06 3805,3365.06 3805,3354.86 3811,3348.86 3811,3342.92 3804,3335.92 3804,3325.72 3811,3318.72 3811,3308.52 3804,3301.52 3804,3291.32 3811,3284.32 3811,3274.12 3804,3267.12 3804,3256.92 3811,3249.92 3811,3234.22 3788.78,3212 3773.8,3212 3767.8,3218 3757.6,3218 3751.6,3212 3741.4,3212 3735.4,3218 3725.2,3218 3719.2,3212 3703.22,3212 3694.34,3220.88 3694.34,3234 3696.68,3236.34 CN1.9@3696.68,3276.53
  Bottom Layer w4: v3(2308,2094.52) U13.J12@2324.02,2078.5
DSI.DSI_D1_N: CN1.17 U13.F13 | length 3220.4
  Top Layer w5.1: v3(2309,2158) 2303,2164 2289.78,2164 2237,2216.78 2237,2335 2187,2385 2187,2461 2427.22,2701.22 2427.22,2733.44 2496.78,2803 2869.59,2803 2883.47,2789.12 2883.47,2724 2888.47,2719 2909.07,2719 2914.07,2724 2914.07,2791.22 2927.85,2805 2968.22,2805 2982,2791.22 2982,2724 2987,2719 3010,2719 3015,2724 3015,2843 3010,2848 2957.78,2848 2944,2861.78 2944,2902.62 2957.78,2916.4 3031,2916.4 3036,2921.4 3036,2950 3031,2955 2953.78,2955 2940,2968.78 2940,3001.82 2953.78,3015.6 3021,3015.6 3026,3020.6 3026,3047 3021,3052 2984.78,3052 2971,3065.78 2971,3183.22 2984.78,3197 3032.22,3197 3046,3183.22 3046,3138.22 3055.22,3129 3464.78,3129 3492,3156.22 3492,3182.22 3518.78,3209 3607.78,3209 3620.28,3221.5 3620.28,3232 3617.94,3234.34 CN1.17@3617.94,3276.53
  Bottom Layer w5.1: U13.F13@2292.52,2172.99 v3(2309,2158)
DSI.DSI_D1_P: CN1.15 U13.F12 | length 3218.5
  Top Layer w5.1: v3(2309.17,2187.84) 2300.33,2179 2296,2179 2252,2223 2252,2341.22 2202,2391.22 2202,2454.78 2216.01,2468.79 2225.79,2468.79 2233.01,2476.01 2233.01,2485.79 2240.23,2493.01 2250.01,2493.01 2257.23,2500.23 2257.23,2510.01 2264.45,2517.23 2274.23,2517.23 2281.45,2524.45 2281.45,2534.23 2288.67,2541.45 2298.45,2541.45 2305.67,2548.67 2305.67,2558.45 2442.22,2695 2442.22,2727.22 2503,2788 2863.37,2788 2868.47,2782.9 2868.47,2717.78 2882.25,2704 2915.29,2704 2929.07,2717.78 2929.07,2785 2934.07,2790 2962,2790 2967,2785 2967,2717.78 2980.78,2704 3016.22,2704 3030,2717.78 3030,2849.22 3016.22,2863 2964,2863 2959,2868 2959,2896.4 2964,2901.4 3037.22,2901.4 3051,2915.18 3051,2956.22 3037.22,2970 2960,2970 2955,2975 2955,2995.6 2960,3000.6 3027.22,3000.6 3041,3014.38 3041,3053.22 3027.22,3067 2991,3067 2986,3072 2986,3177 2991,3182 3026,3182 3031,3177 3031,3132 3049,3114 3471,3114 3507,3150 3507,3176 3525,3194 3614,3194 3635.28,3215.28 3635.28,3232 3637.63,3234.35 CN1.15@3637.63,3276.53
  Bottom Layer w5.1: v3(2309.17,2187.84) U13.F12@2324.02,2172.99
DSI.DSI_RESET: CN1.57 R8.2 U13.D10 | length 1832.8
  Top Layer w5: v3(2372.16,2250.83) 2386.5,2265.17 2386.5,2303 2385,2304.5 2385,2423 2395,2433 2395,2478 2369,2504 2369,2584 2460,2675 2641,2675 2726,2760 2785,2760 v1(2815,2730) ; v1(3222.51,3336.92) 3224.24,3335.19 CN1.57@3224.24,3276.53
  Bottom Layer w4: v3(2372.16,2250.83) U13.D10@2387.01,2235.98
  Bottom Layer w5: v1(2815,2730) 2815,2756 3000,2941 3000,3232 3068,3300 R8.2@3220,3300 3220,3334.41 v1(3222.51,3336.92)
DSI.DSI_TE: CN1.49 U13.P7 | length 1962.7
  Top Layer w5: v1(2955,2170) 2950,2175 2950,2391 3106,2547 3106,2931 v1(3125,2950) ; v1(3301,3215) 3302.98,3216.98 CN1.49@3302.98,3276.53
  L4_SIG w4: v3(2497,1905.52) 2513,1921.52 2513,2035.8 2526.85,2049.65 2535.14,2049.65 2546,2060.51 2546,2067.8 2554.55,2076.35 2562.28,2076.35 2576.83,2090.9 2576.83,2101.8 2597.03,2122 2711,2122 2739,2150 2935,2150 v1(2955,2170)
  Bottom Layer w5: U13.P7@2481.5,1921.02 v3(2497,1905.52) ; v1(3125,2950) 3172,2997 3172,3143 3253,3224 3292,3224 v1(3301,3215)
DSI_VDD12: C23.2 C25.2 C27.2 U13.G13 U13.K12 | length 317.9
  Top Layer w10: v3(2276,2156.35) 2281.35,2151 2291,2151 2301,2141 2324,2141 C25.2@2339,2126
  Top Layer w15: C23.2@2190,2187 2214,2163 2269.35,2163 v3(2276,2156.35) ; C25.2@2339,2126 2339,2064 v3(2340,2063) 2364,2039 C27.2@2365,2039
  Bottom Layer w15: v3(2276,2156.35) 2277.67,2156.35 U13.G13@2292.52,2141.5 ; U13.K12@2324.02,2047.01 v3(2340,2063)
E5V: C139.2 CN3.5 D7.1 JP1.1 R103.2 U18.2 U18.4 | length 3276.8
  Top Layer w20: D7.1@4399.29,775 4505.65,668.64 4668.36,668.64 4714.22,622.78 CN3.5@4714.22,558
  L4_SIG w20: v2(3485,2155) 3505,2155 3595,2065 3595,2030 3669,1956 3726,1956 3755,1927 3755,1813 3794,1774 3794,1406 3990,1210 4215,1210 4360,1065 v2(4365,1065) ; v2(4400,1030) 4421,1009 4421,880 4714.22,586.78 CN3.5@4714.22,558
  Bottom Layer w20: R103.2@3425,2225 3425,2215 v2(3485,2155) ; 4146.98,1114.02 U18.4@4220,1114.02 ; 4220,1070.5 U18.4@4220,1114.02 ; 4220,1157.54 U18.4@4220,1114.02 ; 4293.02,1114.02 U18.4@4220,1114.02 ; 4366.98,970 C139.2@4400,970 ; 4400,1000.52 C139.2@4400,970 ; 4433.02,970 C139.2@4400,970 ; 4456.98,975 JP1.1@4495,975 ; 4495,1013.02 JP1.1@4495,975 ; 4533.02,975 JP1.1@4495,975
  Bottom Layer w40: U18.2@4220,865.98 4220,925
EXT_RST: CN2.6 R54.2 U13.N13 | length 2183.6
  Top Layer w5: CN2.6@915,760 925,770 R54.2@1040,770 1065,745 1415,745 1510,840 v1(1510,1310) ; v1(2144,1810) 2163,1829 2163,1855 2225,1917 2258.5,1917 v3(2276,1934.5)
  Bottom Layer w4: v3(2276,1934.5) 2276,1936 U13.N13@2292.52,1952.52
  Bottom Layer w5: v1(1510,1310) 1570,1310 1920,1660 1994,1660 v1(2144,1810)
EXT_SCL: CN2.5 R56.2 U13.M12 | length 2319
  Top Layer w5: CN2.5@815,760 870,815 R56.2@1040,815 1060,795 1430,795 1485,850 1485,1320 v1(1510,1345) ; v1(2143.5,1837) 2143.5,1855.5 2215,1927 2247.99,1927 2269.99,1949 2286,1949 2304.89,1967.89 v3(2308.37,1967.89)
  Bottom Layer w5: v1(1510,1345) 1555,1345 1986.5,1776.5 2083,1776.5 v1(2143.5,1837) ; v3(2308.37,1967.89) 2308.37,1968.37 U13.M12@2324.02,1984.02
EXT_SDA: R52.1 SB6.1 U13.J15 | length 2311.8
  Top Layer w5: R52.1@1080,660 1080,603.34 SB6.1@1083.01,600.33 1355.33,600.33 1555,800 v1(1555,1455)
  Bottom Layer w5: v1(1555,1455) 1895,1795 1895,1980 1960,2045 2162,2045 2195.5,2078.5 U13.J15@2229.53,2078.5
FMC_A0: U13.D2 U17.G8 | length 2331.5
  Top Layer w5: v3(2413.65,1074) 2413.65,998 2418.65,993 3056,993 3061,998 3061,1948 3056,1953 2862,1953 2775,2040 2763,2040 2725,2078 2725,2205 2694.36,2235.64 v3(2694.36,2240)
  Bottom Layer w5: v3(2413.65,1074) 2413.65,1075.66 U17.G8@2428.5,1090.51 ; U13.D2@2638.98,2235.98 2654.83,2251.83 2682.53,2251.83 v3(2694.36,2240)
FMC_A1: U13.E2 U17.G9 | length 2248.6
  Top Layer w5: v3(2445,1042) 2445,1013 2450,1008 3037,1008 3042,1013 3042,1930 3037,1935 3025,1935 3020,1930 3020,1914 3015,1909 2965,1909 2960,1914 2960,1933 2955,1938 2855,1938 2768,2025 2756,2025 2710,2071 2710,2185 2705,2190 2680,2190 2675,2195 2675,2230 2670,2235 2658.83,2235 2653.83,2230 v3(2653.83,2219.34)
  Bottom Layer w5: U17.G9@2428.5,1059.02 2428.5,1058.5 v3(2445,1042) ; U13.E2@2638.98,2204.49 v3(2653.83,2219.34)
FMC_A2: U13.G2 U17.F7 | length 2263.1
  Top Layer w5: v3(2540,1162) 2546,1156 2645,1156 2650,1151 2650,1060 2655,1055 2680,1055 2685,1060 2685,1125 2690,1130 2700,1130 2705,1125 2705,1045 2710,1040 3000,1040 3010,1050 3010,1615 2984.5,1640.5 2984.5,1831 2979.5,1836 2948.58,1836 2948.08,1835.5 2925,1835.5 2920,1840.5 2920,1895 2910,1905 2843,1905 2753,1995 2735,1995 2677,2053 2677,2134.35 2655,2156.35 v3(2653.83,2156.35)
  Bottom Layer w5: U17.F7@2397.01,1122.01 2397.01,1157 2402.01,1162 v3(2540,1162) ; U13.G2@2638.98,2141.5 v3(2653.83,2156.35)
FMC_A3: U13.H2 U17.F3 | length 2226.7
  Top Layer w5: v3(2381,1264) 2381,1274 2386,1279 2414,1279 2419,1274 2419,1165 2414,1160 2336,1160 2331,1165 2331,1179.29 2336,1184.29 2370,1184.29 2375,1189.29 2375,1199.29 2370,1204.29 2339,1204.29 2334,1209.29 2334,1273 2329,1278 2290,1278 2285,1283 2285,1305 2290,1310 2361,1310 2366,1315 2366,1348 2361,1353 2294,1353 2289,1358 2289,1395 2294,1400 2315.78,1400 2328.21,1399.99 2335,1400 2340,1405 2340,1560.44 2345,1565.44 2382,1565.44 2387,1570.44 2387,1580.44 2382,1585.44 2345,1585.44 2340,1590.44 2340,1600.44 2345,1605.44 2384,1605.44 2389,1610.44 2389,1620.44 2384,1625.44 2345,1625.44 2340,1630.44 2340,1640.44 2345,1645.44 2384,1645.44 2389,1650.44 2389,1660.44 2384,1665.44 2345,1665.44 2340,1670.44 2340,1764 2345,1769 2356,1769 2361,1764 2361,1710 2366,1705 2382,1705 2387,1710 2387,1912 2420,1945 2420,2007 2441.35,2028.35 2441.35,2115 2446.35,2120 2640,2120 2653.83,2106.17 v3(2653.83,2095.15)
  Bottom Layer w5: v3(2381,1264) U17.F3@2397.01,1247.99 ; U13.H2@2638.98,2110 v3(2653.83,2095.15)
FMC_A4: U13.J2 U17.G1 | length 2221.5
  Top Layer w5: v3(2399,1350) 2390,1350 2385,1355 2385,1393 2380,1398 2360,1398 2355,1403 2355,1438.5 2360,1443.5 2415,1443.5 2420,1448.5 2420,1480 2415,1485 2362,1485 2357,1490 2357,1499 2362,1504 2459,1504 2465,1510 2547.44,1510 2552.44,1505 2620,1505 2625,1510 2625,1520 2620,1525 2360,1525 2355,1530 2355,1540 2360,1545 2650,1545 2655,1550 2655,1560 2650,1565 2430,1565 2416,1579 2416,1604 2404,1616 2404,1914 2429,1939 2429,2002 2450.35,2023.35 2450.35,2072.35 2458,2080 2603.65,2080 2621.65,2062 v3(2622,2062)
  Bottom Layer w5: v3(2399,1350) 2423.5,1350 2428.5,1345 U17.G1@2428.5,1310.98 ; v3(2622,2062) 2623.51,2063.51 2623.99,2063.51 U13.J2@2638.98,2078.5
FMC_A5: U13.K3 U17.G2 | length 2248.1
  Top Layer w5: v3(2412,1295) 2415,1298 2415,1422.28 2422.72,1430 2480,1430 2485,1435 2485,1470 2494,1479 2536,1479 2540,1475 2680,1475 2685,1480 2685,1628 2680,1633 2475,1633 2470,1638 2470,1648 2475,1653 2680,1653 2685,1658 2685,1668 2680,1673 2475,1673 2470,1678 2470,1688 2475,1693 2550,1693 2555,1698 2555,1708 2550,1713 2475,1713 2470,1718 2470,1728 2475,1733 2520,1733 2525,1738 2525,1748 2520,1753 2475,1753 2470,1758 2470,1768 2475,1773 2520,1773 2525,1778 2525,1788 2520,1793 2475,1793 2470,1798 2470,1805 2475,1810 2515,1810 2520,1815 2520,1825 2515,1830 2475,1830 2439,1866 2439,1914 2449,1924 2449,1975 2460.16,1986.16 2470.86,1986.16 2479.35,1994.65 2479.35,2008.51 2486,2015.16 2574.16,2015.16 v3(2590,2031)
  Bottom Layer w5: v3(2412,1295) 2412.99,1295 U17.G2@2428.5,1279.49 ; v3(2590,2031) 2591.47,2031 U13.K3@2607.48,2047.01
FMC_A6: U13.M6 U17.G3 | length 2219.6
  Top Layer w5: v3(2476,1233) 2638,1233 2640,1235 2640,1240 2645,1245 2710,1245 2715,1240 2715,1215 2720,1210 2732.36,1210 2737.36,1215 2737.36,1285 2742.36,1290 2752.36,1290 2757.36,1285 2757.36,1215 2762.36,1210 2775,1210 2780,1205 2780,1135 2785,1130 2799.34,1130 2804.34,1135 2804.34,1160 2809.34,1165 2819.34,1165 2824.34,1160 2824.34,1135 2829.34,1130 2846,1130 2851,1135 2851,1153 2856,1158 2868.56,1158 2873.56,1153 2873.56,1137 2878.56,1132 2888.56,1132 2893.56,1137 2893.56,1205 2898.56,1210 2945,1210 2950,1215 2950,1575 2940,1585 2860,1585 2855,1590 2855,1840 2850,1845 2700,1845 2695,1850 2695,1900 2690,1905 2675,1905 2670,1900 2670,1860 2665,1855 2640,1855 2635,1860 2635,1905 2630,1910 2612,1910 2607,1915 2607,1948 2601,1954 2536,1954 2527.84,1962.16 v3(2527.84,1969.17)
  Bottom Layer w5: U17.G3@2428.5,1247.99 2444.49,1232 2475,1232 v3(2476,1233) ; U13.M6@2512.99,1984.02 v3(2527.84,1969.17)
FMC_A7: U13.N6 U17.H1 | length 2266.8
  Top Layer w5: v3(2493,1344) 2493,1285 2498,1280 2513.83,1280 2518.83,1285 2518.83,1340 2523.83,1345 2533.83,1345 2538.83,1340 2538.83,1285 2543.83,1280 2715,1280 2720,1285 2720,1300 2725,1305 2770,1305 2775,1300 2775,1271.87 2780,1266.87 2915,1266.87 2920,1261.87 2920,1251.87 2915,1246.87 2780,1246.87 2775,1241.87 2775,1230 2780,1225 2925,1225 2935,1235 2935,1276.87 2930,1281.87 2874,1281.87 2869,1286.87 2869,1296.87 2874,1301.87 2930,1301.87 2935,1306.87 2935,1565 2930,1570 2845,1570 2840,1575 2840,1815 2825,1830 2705,1830 2695,1820 2625,1820 2620,1825 2620,1885 2615,1890 2586.33,1890 2576.33,1900 2576.33,1910.67 2564.25,1922.75 2542.76,1922.75 v3(2527.84,1937.67)
  Bottom Layer w5: U17.H1@2460,1310.98 v3(2493,1344) ; U13.N6@2512.99,1952.52 v3(2527.84,1937.67)
FMC_A8: U13.P6 U17.H2 | length 2265.5
  Top Layer w5: v3(2476,1295.34) 2476,1350.71 2490.29,1365 2551.02,1365 2556.02,1360 2556.02,1315 2561.02,1310 2571.02,1310 2576.02,1315 2576.02,1360 2581.02,1365 2614.67,1365 2619.67,1360 2619.67,1317 2624.67,1312 2634.67,1312 2639.67,1317 2639.67,1360 2644.67,1365 2654.67,1365 2659.67,1360 2659.67,1296 2664.67,1291 2674.67,1291 2679.67,1296 2679.67,1360 2684.67,1365 2710,1365 2715,1360 2715,1322 2720,1317 2730,1317 2735,1322 2735,1361 2740,1366 2750,1366 2755,1361 2755,1325 2760,1320 2770,1320 2775,1325 2775,1361 2780,1366 2790,1366 2795,1361 2795,1325 2800,1320 2915,1320 2920,1325 2920,1545 2915,1550 2825,1550 2820,1555 2820,1730 2815,1735 2765,1735 2760,1740 2760,1750 2765,1755 2810,1755 2815,1760 2815,1770 2810,1775 2755,1775 2750,1780 2750,1790 2755,1795 2810,1795 2815,1800 2815,1810 2810,1815 2715,1815 2705,1805 2590,1805 2585,1810 2585,1874.01 2569.01,1890 2532.84,1890 2527.84,1895 v3(2527.84,1906.17)
  Bottom Layer w5: U17.H2@2460,1279.49 2460.15,1279.49 v3(2476,1295.34) ; U13.P6@2512.99,1921.02 v3(2527.84,1906.17)
FMC_A9: U13.M8 U17.J3 | length 2269.8
  Top Layer w5: v3(2464.85,1969.17) 2464.85,1959.82 2470,1954.67 2502.36,1954.67 2512,1945.03 2512,1890 2522,1880 2560,1880 2570,1870 2570,1795 2575,1790 2710,1790 2725,1775 2730,1775 2745,1760 2745,1710 2750,1705 2800,1705 2805,1700 2805,1535 2810,1530 2895,1530 2900,1525 2900,1512.05 2895,1507.05 2815,1507.05 2810,1502.05 2810,1492.05 2815,1487.05 2895,1487.05 2900,1482.05 2900,1472.05 2895,1467.05 2815,1467.05 2810,1462.05 2810,1452.05 2815,1447.05 2895,1447.05 2900,1442.05 2900,1432.05 2895,1427.05 2815,1427.05 2810,1422.05 2810,1412.05 2815,1407.05 2895,1407.05 2900,1402.05 2900,1390.56 2895,1385.56 2835,1385.56 2830,1380.56 2830,1370.56 2835,1365.56 2895,1365.56 2900,1360.56 2900,1345 2895,1340 2820,1340 2815,1345 2815,1376 2810,1381 2485,1381
  Top Layer w5.1: v3(2476,1263) 2460,1279 2460,1356 2485,1381
  Bottom Layer w5: U13.M8@2450,1984.02 v3(2464.85,1969.17) ; v3(2476,1263) 2491.01,1247.99 U17.J3@2491.5,1247.99
FMC_A10: U13.N7 U17.G7 | length 2227.5
  Top Layer w5: v3(2412,1138) 2427,1138 2432,1143 2432,1409 2437,1414 2500,1414 2505,1419 2505,1434.5 2510,1439.5 2545,1439.5 2550,1434.5 2550,1420 2555,1415 2770,1415 2775,1420 2775,1430 2770,1435 2575,1435 2570,1440 2570,1450 2575,1455 2770,1455 2775,1460 2775,1470 2770,1475 2705,1475 2700,1480 2700,1490 2705,1495 2770,1495 2775,1500 2775,1510 2770,1515 2705,1515 2700,1520 2700,1680 2689.37,1690.63 2689.37,1715 2684.37,1720 2674.37,1720 2669.37,1715 2669.37,1695 2664.37,1690 2652,1690 2647,1695 2647,1730 2642,1735 2616,1735 2611,1730 2611,1695 2606,1690 2597,1690 2592,1695 2592,1730 2587,1735 2545,1735 2540,1740 2540,1838 2528,1850 2470,1850 2449,1871 2449,1911 2458.67,1920.67 2492.5,1920.67 2497.5,1925.67 v3(2497.5,1935.81)
  Bottom Layer w4: U13.N7@2481.5,1952.52 2497.5,1936.52 v3(2497.5,1935.81)
  Bottom Layer w5: v3(2412,1138) 2427.99,1122.01 U17.G7@2428.5,1122.01
FMC_A11: U13.M7 U17.H9 | length 2255.9
  Top Layer w5: v3(2477,1075) 2481,1079 2481,1149 2460,1170 2460,1210 2467,1217 2650,1217 2655,1222 2655,1230 2660,1235 2695,1235 2700,1230 2700,1200 2705,1195 2755,1195 2760,1190 2760,1120 2765,1115 2912.9,1115 2917.9,1120 2917.9,1185 2922.9,1190 2932.9,1190 2937.9,1185 2937.9,1120 2942.9,1115 2960,1115 2965,1120 2965,1585 2945,1605 2875,1605 2870,1610 2870,1855 2865,1860 2715,1860 2710,1865 2710,1918.17 2705,1923.17 2642,1923.17 2637,1928.17 2637,1958 2611,1984 2522,1984 2507.17,1969.17 v3(2496.35,1969.17)
  Bottom Layer w5: U17.H9@2460,1059.02 2461.02,1059.02 v3(2477,1075) ; U13.M7@2481.5,1984.02 v3(2496.35,1969.17)
FMC_A12: U13.M13 U17.E3 | length 2225
  L4_SIG w4: v3(2277,1968.5) 2273,1972.5 2273,1979 2278,1984 2291,1984 2296,1989 2296,2009.66 2291,2014.66 2211.34,2014.66 2199,2027 2182,2027 2177,2032 2177,2072 2172,2077 2162,2077 2157,2072 2157,1971 2162,1966 2214,1966 2219,1961 2219,1952.69 2214.31,1948 2162,1948 2157,1943 2157,1935 2162,1930 2213,1930 2218,1925 2218,1853 2213,1848 2198,1848 2193,1843 2193,1823 2198,1818 2228,1818 2233,1813 2233,1773 2257,1749 2291,1749 2318,1722 2318,1700.12 2470.12,1548 2470.12,1530 2475.12,1525 2485.29,1525 2490.29,1530 2490.29,1547 2494.29,1551 2502.29,1551 2506.29,1547 2506.29,1529 2510.29,1525 2541,1525 2549,1517 2549,1494 2534,1479 2506,1479 2501,1474 2501,1404 2506,1399 2537,1399 2542,1394 2542,1286 2524,1268 2524,1255 2543,1236 2543,1182 2538,1177 2525,1177 2517,1169 2517,1153 2512,1148 2499,1148 2494,1153 2494,1214 2489,1219 2455,1219 2450,1214 2450,1180 2445,1175 2437,1175 2432,1180 2432,1232.61 2427.61,1237 2421.39,1237 2417,1232.61 2417,1158.69 2412.31,1154 2405.69,1154 2401,1158.69 2401,1200.2 2402,1201.2 2402,1229 2397,1234 2383.54,1234 v3(2381.52,1231.98)
  Bottom Layer w5: v3(2277,1968.5) U13.M13@2292.52,1984.02 ; U17.E3@2365.51,1247.99 v3(2381.52,1231.98)
FMC_BA0: U13.N12 U17.J7 | length 2266.1
  Top Layer w5: v3(2308.51,1936.99) 2308.51,1936.49 2324,1936.49 2326.5,1933.99 2326.5,1863 2321.5,1858 2311,1858 2306,1853 2306,1656 2301,1651 2215.5,1651 2210.5,1646 2210.5,1636 2215.5,1631 2302,1631 2307,1626 2307,1616 2302,1611 2190,1611 2185,1606 2185,1576.03 2190,1571.03 2302,1571.03 2307,1566.03 2307,1556.03 2302,1551.03 2176,1551.03 2171,1546.03 2171,1536.03 2176,1531.03 2302,1531.03 2307,1526.03 2307,1516.03 2302,1511.03 2176,1511.03 2171,1506.03 2171,1496.03 2176,1491.03 2301,1491.03 2306,1486.03 2306,1476.03 2301,1471.03 2195,1471.03 2190,1466.03 2190,1409 2185,1404 2178,1404 2173,1399 2173,1288 2202,1259 2202,1094.5 2207,1089.5 2362.5,1089.5 2380,1107 v3(2445,1107)
  Bottom Layer w5: v3(2308.51,1936.99) U13.N12@2324.02,1952.52 ; v3(2445,1107) 2474.99,1107 2490,1122.01 U17.J7@2491.5,1122.01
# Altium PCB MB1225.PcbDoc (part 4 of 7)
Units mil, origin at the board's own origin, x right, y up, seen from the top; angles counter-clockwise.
Board outline 5000 x 3464.56 mil, 6 copper layers (Top Layer, L2_GND, L3_VCC, L4_SIG, L5_GND, Bottom Layer), stack 62.2 mil thick; 453 components, 378 nets, 1982 pads, 949 vias.

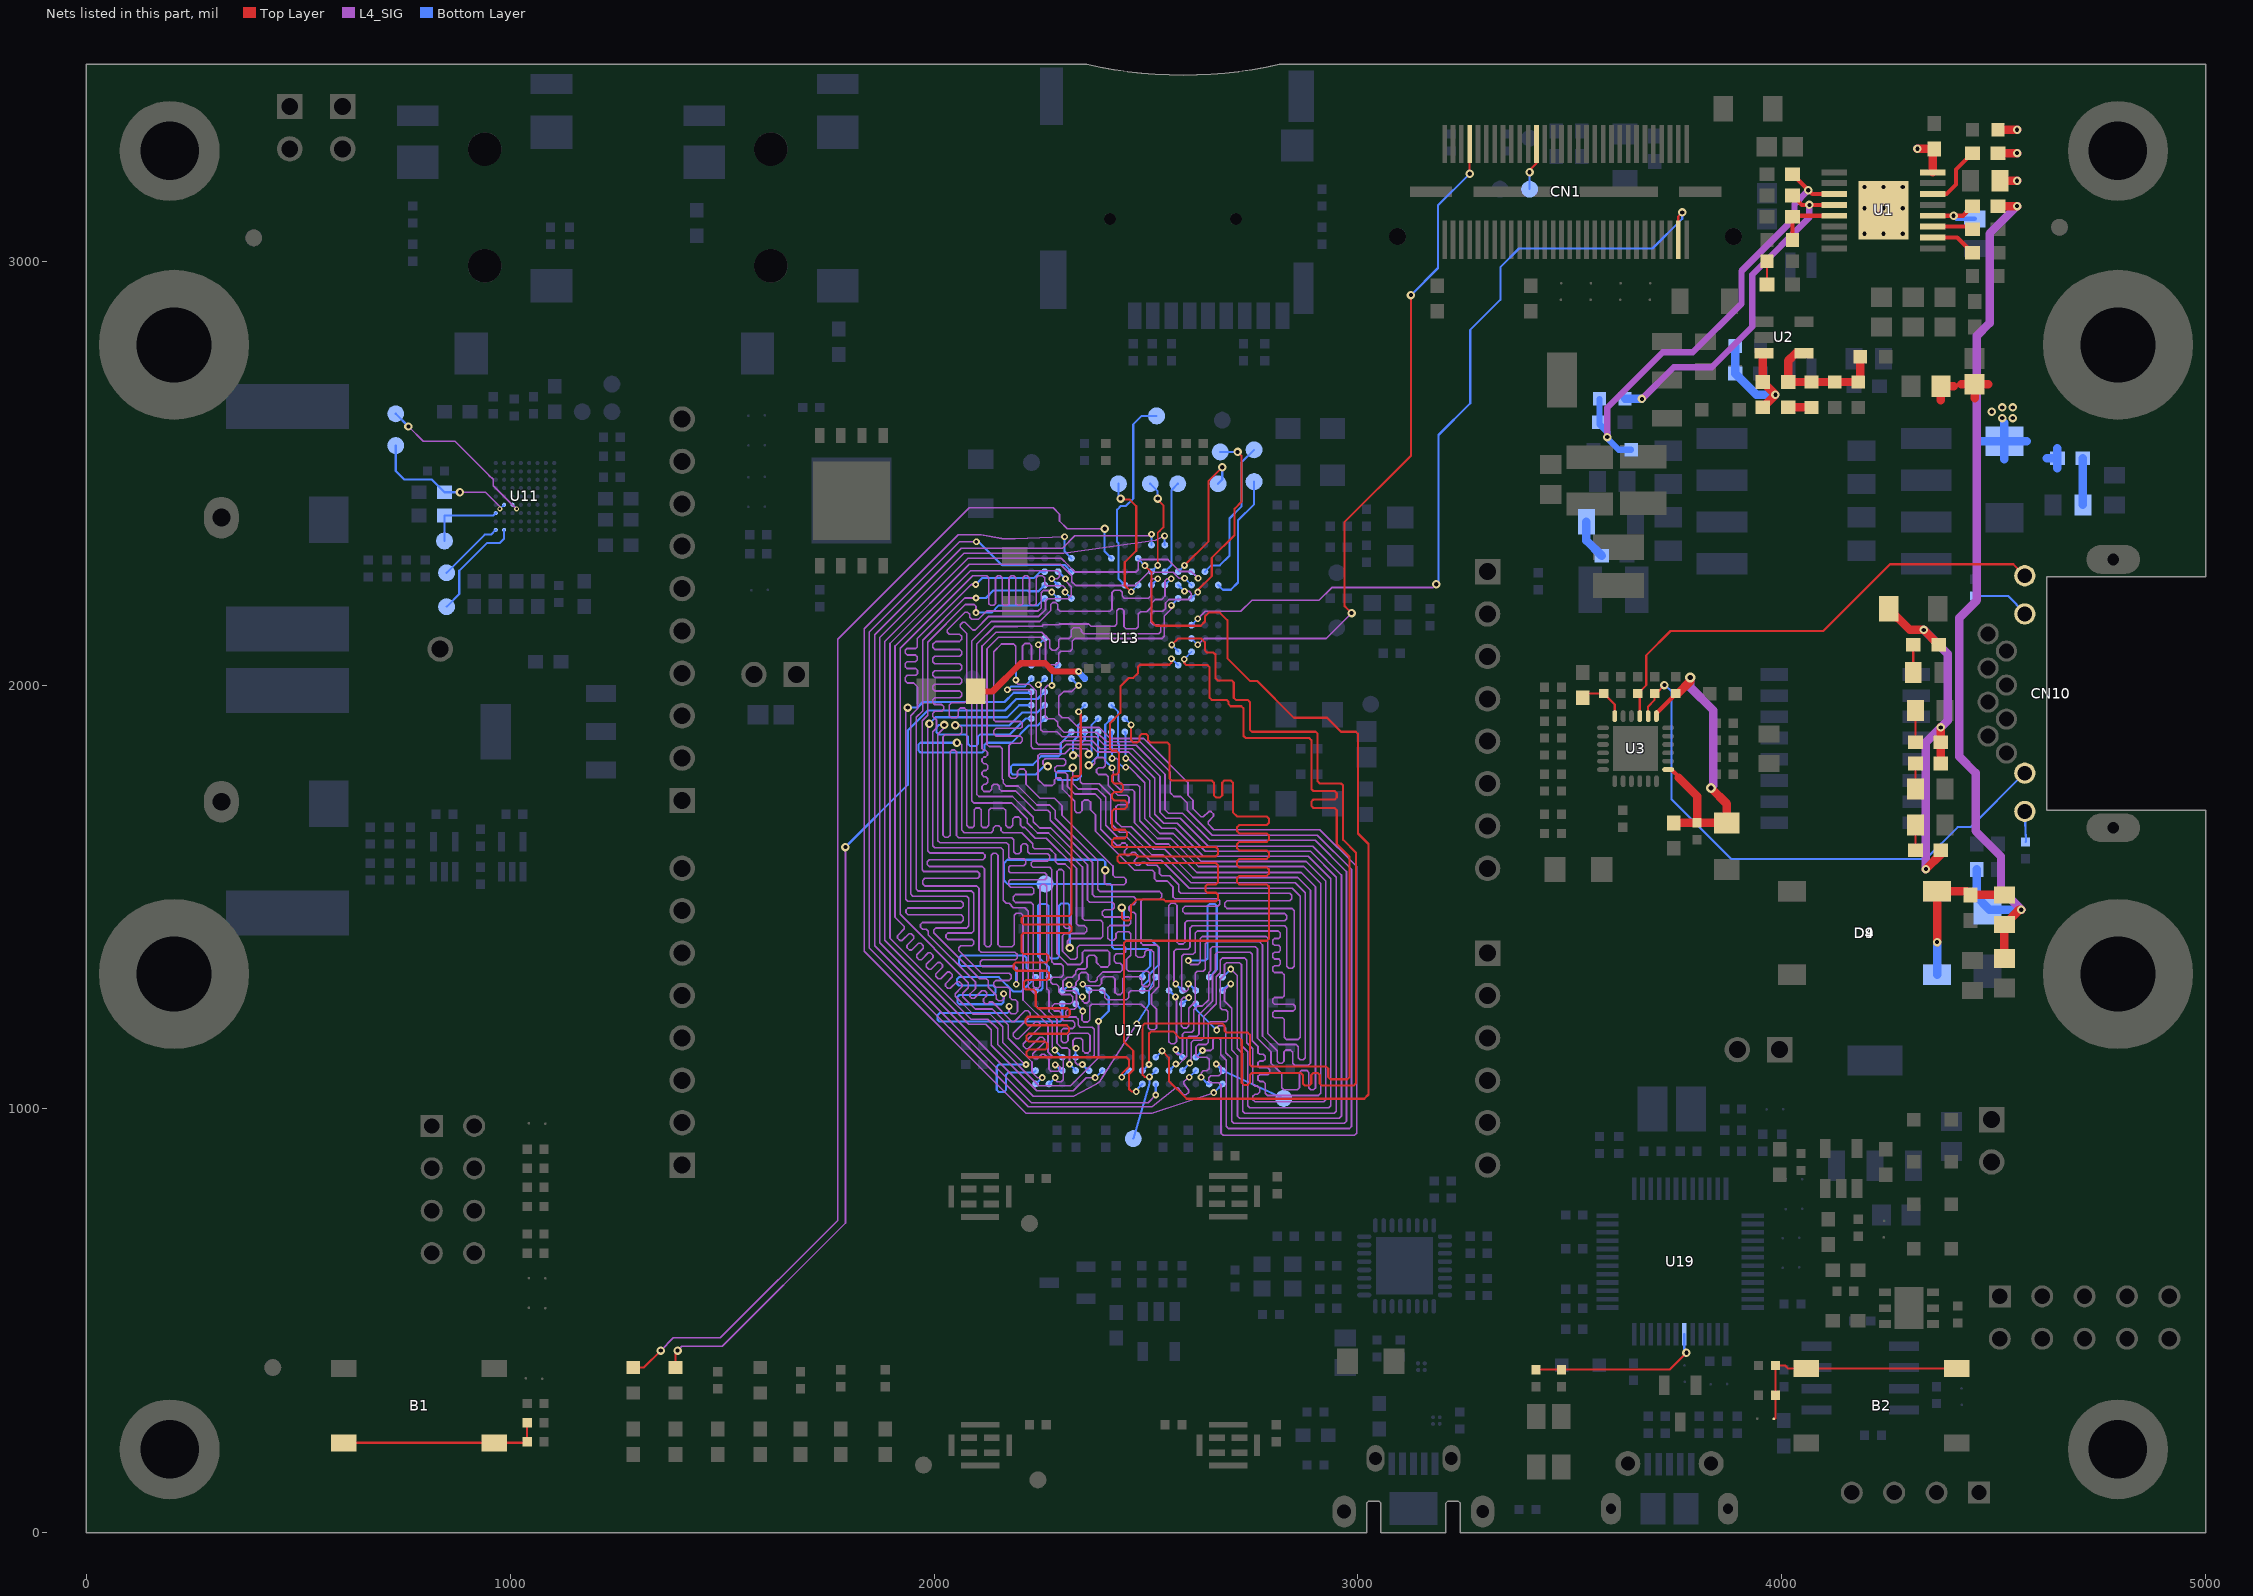
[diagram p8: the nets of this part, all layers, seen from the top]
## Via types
v1: diameter 20, hole 10, Top Layer to Bottom Layer, 354 vias
v2: diameter 24, hole 12, Top Layer to Bottom Layer, 347 vias
v3: diameter 16, hole 8, Top Layer to Bottom Layer, 221 vias
v4: diameter 12, hole 6, Top Layer to Bottom Layer, 27 vias

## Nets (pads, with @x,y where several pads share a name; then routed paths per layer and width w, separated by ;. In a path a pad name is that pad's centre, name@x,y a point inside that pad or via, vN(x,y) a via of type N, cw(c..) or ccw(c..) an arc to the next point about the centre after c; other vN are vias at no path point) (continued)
FMC_BA1: U13.N11 U17.H8 | length 2237.8
  Top Layer w5: v3(2341,1937) 2346,1932 2346,1790 2341,1785 2329,1785 2324,1780 2324,1460 2319,1455 2212,1455 2207,1450 2207,1440 2212,1435 2319,1435 2324,1430 2324,1420 2319,1415 2211,1415 2206,1410 2206,1371 2211,1366 2265,1366 2270,1361 2270,1351 2265,1346 2193,1346 2188,1341 2188,1331 2193,1326 2266,1326 2271,1321 2271,1309 2266,1304 2217,1304 2212,1299 2212,1287 2217,1282 2235,1282 2240,1277 2240,1242.54 2245,1237.54 2315,1237.54 2320,1232.54 2320,1222.54 2315,1217.54 2221,1217.54 2216,1212.54 2216,1202.54 2221,1197.54 2313,1197.54 2318,1192.54 2318,1182.54 2313,1177.54 2223,1177.54 2218,1172.54 2218,1164 2223,1159 2262,1159 2267,1154 2267,1145 2262,1140 2223,1140 2218,1135 2218,1127 2223,1122 2454,1122 2460,1116 2460,1100 2443,1083 v3(2443,1075)
  Bottom Layer w5: v3(2341,1937) 2341,1938.01 U13.N11@2355.51,1952.52 ; v3(2443,1075) 2458.51,1090.51 U17.H8@2460,1090.51
FMC_D0: TP27.1 U13.L12 U17.R8 | length 2396.6
  L4_SIG w4: v3(2341,1999) 2339,1999 2325,1985 2305.68,1985 2294.37,1973.69 2294.37,1962.09 2294.51,1961.95 2294.51,1931.19 2302.71,1922.99 2317.01,1922.99 2340,1900 2390,1900 2416,1874 2495,1874 2510.97,1858.03 ; 2510.97,1858.01 2599,1769.98 2599,1740 2611,1728 2611,1708 2629.78,1689.22 2635.44,1689.22 2647.78,1701.56 2653.44,1701.56 2659.1,1695.9 2659.1,1690.24 2646.76,1677.9 2646.76,1672.24 2660,1659 2910,1659 2997,1572 2997,943 2992,938 2682,938 2677,943 2677,1057.17 2672,1062.17 2652.69,1062.17 2648,1066.86 2648,1073.48 2652.69,1078.17 2672,1078.17 2677,1083.17 2677,1101 2672,1106 v3(2665.98,1106)
  Bottom Layer w5: U13.L12@2324.02,2015.51 2340.53,1999 v3(2341,1999) ; v3(2665.98,1106) 2665.98,1105 U17.R8@2680.47,1090.51 TP27.1@2825,1025
FMC_D1: U13.K13 U17.N7 | length 2263.6
  L4_SIG w4: v3(2278,1999) 2267,1999 2262,1994 2262,1925.5 2267,1920.5 2283.14,1920.5 2291.67,1911.97 2291.67,1903.87 2306.54,1889 2384,1889 2407,1866 2486,1866 2557,1795 2557,1746 2566,1737 2582,1737 2597,1722 2597,1705 2656,1646 2904,1646 2985,1565 2985,959 2980,954 2694,954 2689,959 2689,1115 2676,1128 2676,1163.61 2671.61,1168 2663,1168 2658,1163 2658,1142.86 2653,1137.86 v3(2633.33,1137.86)
  Bottom Layer w5: v3(2278,1999) 2278,2032.49 U13.K13@2292.52,2047.01 ; U17.N7@2617.48,1122.01 v3(2633.33,1137.86)
FMC_D2: U13.B12 U17.R9 | length 2404.5
  L4_SIG w4: v3(2308,2350) 2191,2345.43 2180,2345 2175,2345 2160,2346 2111,2355 2057,2355 1835.14,2133.14 1835.14,1371.86 2217,990 2514,990 2589.18,1015 v3(2660,1038.55)
  Bottom Layer w5: v3(2308,2350) 2308,2315 U13.B12@2324.02,2298.98 ; v3(2660,1038.55) U17.R9@2680.47,1059.02
FMC_D3: U13.C12 U17.N8 | length 2341.6
  L4_SIG w4: v3(2100,2338) 2060,2338 1847.14,2125.14 1847.14,1379.86 2222,1005 2514,1005 2570.64,1050.06 2576.26,1049.41 2588.39,1034.16 2594.01,1033.53 2600.28,1038.52 2600.91,1044.14 2588.78,1059.38 2589.42,1065.01 v3(2602,1075.03)
  Bottom Layer w5: v3(2100,2338) 2105,2338 2159.75,2283.25 2308.25,2283.25 U13.C12@2324.02,2267.48 ; v3(2602,1075.03) U17.N8@2617.48,1090.51
FMC_D4: U13.R8 U17.P9 | length 2240.9
  L4_SIG w4: v3(2452,1827) 2457,1827 2509,1775 2509,1690.06 2537.06,1662 2569,1662 2635,1596 2883,1596 2936,1543 2936,1008 2931,1003 2745,1003 2740,1008 2740,1135 2725.5,1149.5 2725.5,1340 2720.5,1345 2690,1345 2685,1340 2685,1316 2675,1306 2675,1239 2680,1234 2688,1234 2693,1229 2693,1211 2688,1206 2652,1206 2647,1201 2647,1157 2642,1152 2623,1152 2618,1147 2618,1127 2623,1122 2644,1122 2649,1117 2649,1095 2644,1090 2635.05,1090 2630.05,1085 v3(2630.05,1074.94)
  Bottom Layer w5: U13.R8@2450,1889.53 2452,1887.53 v3(2452,1827) ; v3(2630.05,1074.94) 2645.97,1059.02 U17.P9@2648.98,1059.02
FMC_D5: U13.N9 U17.M8 | length 2219.5
  L4_SIG w4: v3(2452,1806) 2461,1806 2497,1770 2497,1685.08 2532.08,1650 2564,1650 2630,1584 2878,1584 2924,1538 2924,1022 2919,1017 2757,1017 2752,1022 2752,1030 2757,1035 2763,1035 2768,1040 2768,1049 2763,1054 2757,1054 2752,1059 2752,1142 2738,1156 2738,1351 2733,1356 2680,1356 2675,1351 2675,1321 2666,1312 2666,1248 2636,1218 2636,1167 2631,1162 2612,1162 2607,1157 2607,1112.08 v3(2603.06,1108.14)
  Bottom Layer w5: U13.N9@2418.5,1952.52 2434.3,1936.72 2434.3,1862.7 2436,1861 2436,1816 2446,1806 v3(2452,1806) ; U17.M8@2585.98,1090.51 2603.06,1107.59 v3(2603.06,1108.14)
FMC_D6: U13.P9 U17.M7 | length 2233.1
  L4_SIG w4: v3(2420,1805) 2423,1802 2423,1769 2439,1753 2468,1753 2473,1748 2473,1675.12 2523.12,1625 2553,1625 2620,1558 2866,1558 2900,1524 2900,1049.69 2895.31,1045 2888.69,1045 2884,1049.69 2884,1086 2879,1091 2867,1091 2862,1086 2862,1050 2857,1045 2825,1045 2820,1050 2820,1083 2795,1108 2795,1135 2763,1167 2763,1378 2758,1383 2657,1383 2652,1378 2652,1326 2648,1322 2648,1258 2633,1243 2622,1243 2613,1234 2613,1186 2608,1181 2591,1181 2586,1176 2586,1133 2581,1128 2575,1128 2570,1133 v3(2570,1140)
  Bottom Layer w5: U13.P9@2418.5,1921.02 2404,1906.52 2404,1821 v3(2420,1805) ; v3(2570,1140) 2570,1137.99 U17.M7@2585.98,1122.01
FMC_D7: U13.R9 U17.L8 | length 2224
  L4_SIG w4: v3(2420,1827) 2430,1827 2435,1822 2435,1774 2444,1765 2480,1765 2485,1760 2485,1680.1 2527.1,1638 2558,1638 2624,1572 2872,1572 2912,1532 2912,1037 2907,1032 2786,1032 2781,1037 2781,1060.02 2776,1065.02 2768,1065.02 2764,1069.02 2764,1077.02 2768,1081.02 2787.31,1081.02 2792,1085.71 2792,1092.33 2787.31,1097.02 2768,1097.02 2764,1101.02 2764,1109.02 2768,1113.02 2776.31,1113.02 2781,1117.71 2781,1124.33 2776.31,1129.02 2768,1129.02 2764,1133.02 2764,1148 2751,1161 2751,1365 2746,1370 2669,1370 2664,1365 2664,1324 2657,1317 2657,1254 2625,1222 2625,1176 2620,1171 2601,1171 2596,1166 2596,1124 2578.01,1106.01 v3(2570.51,1106.01)
  Bottom Layer w5: U13.R9@2418.5,1889.53 2420,1888.03 v3(2420,1827) ; U17.L8@2554.49,1090.51 2569.48,1105.5 2570,1105.5 v3(2570.51,1106.01)
FMC_D8: U13.P10 U17.L2 | length 2225.9
  L4_SIG w4: v1(2365,1837) 2365,1845 2360,1850 2336.05,1850 2335.05,1851 2320.95,1851 2307.95,1838 2250,1838 2245,1833 2245,1778 2260,1763 2279,1763 2284,1768 2284,1776 2289,1781 2298,1781 2303,1776 2303,1755 2332,1726 2332,1703.98 2336.98,1699 2344.02,1699 2349,1703.98 2349,1724 2354,1729 2364,1729 2369,1724 2369,1706 2381,1694 2381,1655 2473,1563 2515,1563 2520,1558 2520,1543 2525,1538 2550,1538 2563.5,1524.5 2563.5,1501 2568.5,1496 2669,1496 2674,1491 2674,1483 2669,1478 2592,1478 2587,1473 2587,1465.98 2591.98,1461 2827.02,1461 2832,1456.02 2832,1448.98 2827.02,1444 2597,1444 2592,1439 2592,1394 2587,1389 2578,1389 2573,1394 2573,1480 2568,1485 2559,1485 2554,1480 2554,1159 2559,1154 2567,1154 2572,1159 2572,1261.98 v3(2569.49,1264.49)
  Bottom Layer w5: v1(2365,1837) 2371.2,1843.2 2371.2,1905.21 U13.P10@2387.01,1921.02 ; U17.L2@2554.49,1279.49 v3(2569.49,1264.49)
FMC_D9: U13.R10 U17.M3 | length 2226.1
  L4_SIG w4: v1(2365,1811) 2374,1811 2379,1816 2379,1824 2384,1829 2399.02,1829 2404,1824.02 2404,1810 2399,1805 2388,1805 2383,1800 2383,1793.98 2387.98,1789 2406,1789 2411,1784 2411,1763 2434,1740 2455,1740 2460,1735 2460,1723 2455,1718 2434,1718 2429,1713 2429,1679.12 2442.12,1666 2465,1666 2518,1613 2544,1613 2611,1546 2858,1546 2888,1516 2888,1108 2883,1103 2851,1103 2846,1108 2846,1134 2841,1139 2829.54,1139 2825.54,1135 2825.54,1112.69 2820.85,1108 2814.23,1108 2809.54,1112.69 2809.54,1137.46 2775,1172 2775,1387 2767,1395 2645,1395 2640,1390 2640,1330 2635,1325 2621,1325 2616,1320 2616,1253 2601,1238 2601,1196 2596,1191 2588,1191 2583,1196 2583,1257.84 2588,1262.84 v3(2600.83,1262.84)
  Bottom Layer w5: v1(2365,1811) 2387.01,1833.01 U13.R10@2387.01,1889.53 ; U17.M3@2585.98,1247.99 v3(2600.83,1262.84)
FMC_D10: U13.R12 U17.M2 | length 2247.4
  L4_SIG w4: v1(2268,1808) 2262,1808 2257,1813 2257,1821 2262,1826 2306.31,1826 2311,1821.31 2311,1814.69 2306.31,1810 2289.98,1810 2285,1805.02 2285,1797.98 2289.98,1793 2310,1793 2315,1788 2315,1760 2332,1743 2380,1743 2393,1730 2393,1660 2431,1622 2438,1622 2443.54,1627.54 2450.46,1627.54 2455.37,1622.63 2455.37,1615.71 2449.15,1609.49 2449.15,1603.83 2454.81,1598.17 2460.47,1598.17 2467.82,1605.52 2473.48,1605.52 2479.86,1599.14 2479.86,1593.48 2473.01,1586.63 2473.01,1579.99 2477.69,1575.31 2484.33,1575.31 2491.18,1582.16 2496.84,1582.16 2504,1575 2525,1575 2532,1568 2532,1555 2537,1550 2556,1550 2577,1529 2577,1514 2582,1509 2839,1509 2844,1504 2844,1496 2839,1491 2691,1491 2686,1486 2686,1478 2691,1473 2845,1473 2850,1468 2850,1337 2845,1332 2837,1332 2832,1337 2832,1427 2827,1432 2609,1432 2604,1427 2604,1382 2599,1377 2571,1377 2566,1372 2566,1299 v3(2570,1295)
  Bottom Layer w5: v1(2268,1808) 2259,1808 2240,1789 2186,1789 2181,1794 2181,1807 2186,1812 2233,1812 2253,1832 2294,1832 2299,1837 2299,1862.98 2324.02,1888 U13.R12@2324.02,1889.53 ; v3(2570,1295) 2570.47,1295 U17.M2@2585.98,1279.49
FMC_D11: U13.P11 U17.P1 | length 2226.8
  L4_SIG w4: v1(2328,1834) 2340,1834 2345,1829 2345,1772 2350,1767 2390,1767 2417,1740 2417,1674.14 2438.14,1653 2460,1653 2514,1599 2541.02,1599 2606.02,1534 2852,1534 2876,1510 2876,1120.9 2871.1,1116 2864.18,1116 2859.28,1120.9 2859.28,1147 2854.28,1152 2813,1152 2787,1178 2787,1404 2784,1407 2633,1407 2628,1402 2628,1346 2623,1341 2605,1341 2600,1346 v3(2600,1350)
  Bottom Layer w5: v1(2328,1834) 2328,1868 2340,1880 2340,1905.51 2343.81,1909.33 U13.P11@2355.51,1921.02 ; v3(2600,1350) 2640,1350 2645,1355 2645,1479 2650,1484 2662,1484 2667,1479 2667,1329 U17.P1@2648.98,1310.98
FMC_D12: U13.R11 U17.N2 | length 2224.3
  L4_SIG w4: v1(2327,1805) 2327,1768 2340,1755 2385,1755 2405,1735 2405,1669.16 2433.16,1641 2455,1641 2509,1587 2536.04,1587 2602.04,1521 2845,1521 2864,1502 2864,1169 2859,1164 2831,1164 2826,1169 2826,1211.02 2822,1215.02 2803,1215.02 2799,1219.02 2799,1227.02 2803,1231.02 2847.31,1231.02 2852,1235.71 2852,1242.33 2847.31,1247.02 2803,1247.02 2799,1251.02 2799,1259.02 2803,1263.02 2822,1263.02 2826,1267.02 2826,1317 2821,1322 2803,1322 2799,1326 2799,1334 2803,1338 2813,1338 2817,1342 2817,1350 2813,1354 2803,1354 2799,1358 2799,1366 2803,1370 2813,1370 2817,1374 2817,1382 2813,1386 2803,1386 2799,1390 2799,1398 2803,1402 2813,1402 2817,1406 2817,1415 2812,1420 2621,1420 2616,1415 2616,1370 2611,1365 2589,1365 2584,1360 2584,1281.69 2588.69,1277 2595.31,1277 2600,1281.69 v3(2600,1295)
  Bottom Layer w5: v1(2327,1805) 2327,1802 2322,1797 2293,1797 2288,1792 2288,1781 2293,1776 2338,1776 2346,1784 2346,1862 2355.51,1871.51 U13.R11@2355.51,1889.53 ; v3(2600,1295) 2601.97,1295 U17.N2@2617.48,1279.49
FMC_D13: U13.L15 U17.R1 | length 2313
  L4_SIG w4: v3(2173.05,1988.95) 2224,1988.95 2229,1983.95 2229,1855 2234,1850 2302,1850 2312,1860 2367,1860 2385,1842 2459,1842 2521,1780 2521,1695.04 2542.04,1674 2574,1674 2640,1608 2888,1608 2949,1547 2949,995 2944,990 2733,990 2728,995 2728,1130 2715,1143 2715,1315 v3(2700,1330)
  Bottom Layer w5: v3(2173.05,1988.95) 2173.77,1988.95 2181.82,1997 2214,1997 2229.53,2012.53 U13.L15@2229.53,2015.51 ; U17.R1@2680.47,1310.98 2680.98,1310.98 v3(2700,1330)
FMC_D14: U13.L14 U17.N3 | length 2241.2
  L4_SIG w4: v3(2246.17,2000.66) 2247,2000.66 2252,1995.66 2252,1895 2257,1890 2290,1890 2302,1878 2382,1878 2402,1858 2477,1858 2545,1790 2545,1706 2553,1698 2586,1698 2650,1634 2899,1634 2973,1560 2973,971 2968,966 2707,966 2702,971 2702,1119 2688,1133 2688,1191 2683,1196 2671.9,1196 2666.9,1191 v3(2666.9,1186)
  Bottom Layer w5: v3(2246.17,2000.66) U13.L14@2261.02,2015.51 ; U17.N3@2617.48,1247.99 2617.48,1235.42 v3(2666.9,1186)
FMC_D15: U13.K15 U17.R2 | length 2329.2
  L4_SIG w4: v3(2193,2012) 2193,2007 2198,2002 2225,2002 2241,1986 2241,1865 2246,1860 2297,1860 2306,1869 2373,1869 2392,1850 2467.98,1850 2533,1784.98 2533,1700.02 2547.02,1686 2581,1686 2647,1620 2893,1620 2961,1552 2961,983 2956,978 2721,978 2716,983 2716,1125 2702,1139 2702,1238 2685,1255 2685,1280 v3(2700,1295)
  Bottom Layer w5: v3(2193,2012) 2193,2035 2205.01,2047.01 U13.K15@2229.53,2047.01 ; U17.R2@2680.47,1279.49 2695.98,1295 v3(2700,1295)
FMC_D16: U13.P14 U17.E8 | length 2227.8
  L4_SIG w4: v1(2054,1864) 2060,1864 2065,1859 2065,1658 2071,1652 2135,1652 2140,1657 2140,1663 2145,1668 2153,1668 2158,1663 2158,1657 2163,1652 2207,1652 2233,1626 2233,1618 2237,1614 2273,1614 2286.5,1600.5 2286.5,1583.5 2292,1578 2309,1578 2323,1564 2323,1430.98 2318.02,1426 2310.98,1426 2306,1430.98 2306,1560.31 2301.31,1565 2294.69,1565 2290,1560.31 2290,1366 2315,1341 2345,1341 2350,1346 2350,1369 2355,1374 2409,1374 2414,1369 2414,1340 2409,1335 2394,1335 2383,1346 2383,1358.02 2378.02,1363 2366,1363 2361,1358 2361,1335 2356,1330 2339,1330 2334,1325 2334,1319 2326,1311 2314,1311 2304,1301 2304,1284 2309,1279 2331,1279 2336,1274 2336,1240 2331,1235 2316,1235 2311,1230 2311,1222 2316,1217 2335,1217 2340,1212 2340,1198 2345,1193 2373,1193 2378,1188 2378,1127 2373,1122 2338,1122 2333,1117 2333,1110 2338,1105 v3(2350,1105)
  Bottom Layer w5: v1(2054,1864) 1968,1864 1963,1859 1963,1846 1968,1841 2114,1841 2119,1846 2119,1859 2124,1864 2183,1864 2224.1,1905.1 2245.1,1905.1 U13.P14@2261.02,1921.02 ; v3(2350,1105) 2364.49,1090.51 U17.E8@2365.51,1090.51
FMC_D17: U13.N14 U17.D7 | length 2223.5
  L4_SIG w4: v1(2050,1905) 2060,1905 2065,1900 2065,1888 2060,1883 2026,1883 2021,1878 2021,1645.98 2025.98,1641 2033.02,1641 2038,1645.98 2038,1842.61 2042.39,1847 2048.61,1847 2053,1842.61 2053,1645 2058,1640 2183,1640 2188,1635 2188,1607 2193,1602 2200,1602 2205,1607 2205,1621.31 2209.69,1626 2216,1626 2221,1621 2221,1607 2226,1602 2268.02,1602 2273,1597.02 2273,1589.98 2268.02,1585 2233.39,1585 2229,1580.61 2229,1574.39 2233.39,1570 2273,1570 2278,1565 2278,1347 2283,1342 2300,1342 2305,1337 2305,1316 2300,1311 2279.98,1311 2275,1306.02 2275,1298.98 2279.98,1294 2289,1294 2294,1289 2294,1276 2300,1270 2322,1270 2327,1265 2327,1253 2322,1248 2283.98,1248 2279,1243.02 2279,1235.98 2283.98,1231 2295,1231 2300,1226 2300,1213 2305,1208 2327,1208 2332,1203 2332,1195 2327,1190 2305,1190 2300,1185 2300,1161 2305,1156 2311,1156 2316,1161 2316,1174 2321,1179 2363,1179 2368,1174 2368,1137 2363,1132 2356,1132 2351,1137 2351,1162.31 2346.31,1167 2333,1167 2328,1162 2328,1148.01 2333,1143.01 v3(2335,1143.01)
  Bottom Layer w5: v1(2050,1905) 2178,1905 2208.52,1935.52 2244.02,1935.52 U13.N14@2261.02,1952.52 ; U17.D7@2334.02,1122.01 2334.02,1142.03 v3(2335,1143.01)
FMC_D18: U13.P15 U17.D8 | length 2224.4
  L4_SIG w4: v1(2024,1906) 2024,1899 2009,1884 2009,1633 2014,1628 2171,1628 2176,1623 2176,1594 2180,1590 2211.31,1590 2216,1585.31 2216,1578.69 2211.31,1574 2180,1574 2176,1570 2176,1561 2180,1557 2261.31,1557 2266,1552.31 2266,1545.69 2261.31,1541 2180,1541 2176,1537 2176,1528 2181,1523 2231,1523 2235,1519 2235,1509 2232,1506 2192,1506 2187,1501 2187,1492 2192,1487 2229,1487 2234,1482 2234,1289.69 2238.69,1285 2245.31,1285 2250,1289.69 2250,1525.31 2254.69,1530 2261.31,1530 2266,1525.31 2266,1284 2271,1279 2271,1230 2290,1211 2290,1155 2301,1144 2314.41,1144 2319.41,1139 v3(2319.41,1105.61)
  Bottom Layer w5: v1(2024,1906) 2011,1906 2006,1901 2006,1888 2011,1883 2075,1883 2080,1878 2080,1861 2085,1856 2098,1856 2103,1861 2103,1878 2108,1883 2178,1883 2216.02,1921.02 U13.P15@2229.53,1921.02 ; v3(2319.41,1105.61) 2334.02,1091 U17.D8@2334.02,1090.51
FMC_D19: U13.N15 U17.B9 | length 2255.1
  L4_SIG w4: v1(1989,1909) 1985,1905 1985,1609 1990,1604 2115.31,1604 2120,1599.31 2120,1592.69 2115.31,1588 1988.69,1588 1984,1583.31 1984,1576.69 1988.69,1572 2114,1572 2119,1567 2119,1388 2124,1383 2130,1383 2135,1388 2135,1598.31 2139.69,1603 2146.31,1603 2151,1598.31 2151,1388 2156,1383 2184,1383 2189,1388 2189,1457 2194,1462 2205,1462 2210,1457 2210,1257 2269,1198 2269,1134 2281,1122 2300,1122 2305,1117 2305,1069 2300,1064 2291,1064 2286,1069 v3(2286,1074)
  Bottom Layer w5: v1(1989,1909) 2004,1924 2172.48,1924 2201,1952.52 U13.N15@2229.53,1952.52 ; U17.B9@2271.02,1059.02 v3(2286,1074)
FMC_D20: U13.M15 U17.C8 | length 2245.9
  L4_SIG w4: v1(1938,1947) 1933,1942 1933,1495 1938,1490 2064.31,1490 2069,1485.31 2069,1478.69 2064.31,1474 1938.69,1474 1934,1469.31 1934,1462.69 1938.69,1458 2064,1458 2069,1453 2069,1445 2064,1440 1972.69,1440 1968,1435.31 1968,1429 1973,1424 1981.5,1424 1986.5,1419 1986.5,1410.5 2098,1299 2098,1284.32 2084.82,1271.14 2084.82,1265.18 2089.02,1260.98 2094.98,1260.98 2112.63,1278.63 2119.37,1278.63 2124.13,1273.87 2124.13,1267.13 2116.48,1259.48 2116.48,1253.09 2121.02,1248.56 2127.42,1248.56 2131.43,1252.57 2137.41,1252.57 2183.99,1205.99 2188.99,1205.99 2214.46,1231.46 2221.54,1231.46 2226.96,1226.04 2226.96,1218.96 2187,1179 2187,1171.98 2193.38,1165.6 2199.04,1165.6 2239.4,1205.96 2246.04,1205.96 2250.72,1201.28 2250.72,1194.64 2210.36,1154.28 2210.36,1148.62 2216.75,1142.23 2222.41,1142.23 2249.27,1169.09 2255.91,1169.09 2260.59,1164.41 2260.59,1157.77 2233.16,1130.34 2233.16,1123.84 2237.75,1119.25 2244.25,1119.25 2254,1129 2260,1129 2271,1118 2271,1093.39 2275.39,1089 2292.22,1089 2297,1093.78 2297,1099 2292,1104 v3(2286,1104)
  Bottom Layer w5: v1(1938,1947) 1961,1947 1974,1960 2166.04,1960 2188.04,1982 2227.51,1982 U13.M15@2229.53,1984.02 ; v3(2286,1104) 2299.49,1090.51 U17.C8@2302.52,1090.51
FMC_D21: U13.E12 U17.A9 | length 2242.8
  L4_SIG w4: v3(2255,1074) 2244,1074 2231,1087 2231,1111 2175,1167 2175,1198 2138,1235 2136.98,1236 2097,1236 2068,1265 2068,1273 2081,1286 2081,1298 1920,1459 1920,2087 2091,2258 2124.01,2258 2129.01,2253 2129.01,2192 2133.01,2188 2141.01,2188 2145.01,2192 2145.01,2253 2150.01,2258 2156.01,2258 2161.01,2253 2161.01,2192 2165.01,2188 2173.01,2188 2177.01,2192 2177.01,2253 2182.01,2258 2188.01,2258 2193.01,2253 2193.01,2192 2197.01,2188 2205.01,2188 2209.01,2192 2209.01,2253 2214.01,2258 2220.01,2258 2225.01,2253 2225.01,2192 2229.01,2188 2237.01,2188 2241.01,2192 2241.01,2253 2246.01,2258 2256,2258 2261,2253 2261,2239 2266,2234 2304.17,2234 2309.17,2229 v3(2309.17,2219.34)
  Bottom Layer w5: U17.A9@2239.53,1059.02 2254.51,1074 v3(2255,1074) ; v3(2309.17,2219.34) U13.E12@2324.02,2204.49
FMC_D22: U13.E13 U17.C7 | length 2228.9
  L4_SIG w4: v3(2277.67,2219.34) 2274.01,2223 2258,2223 2253,2218 2253,2182 2246,2175 2125,2175 2105,2155 2089,2155 2084,2160 2084,2167 2079,2172 2073,2172 2031,2130 2031,2125 2036,2120 2060.02,2120 2065,2115.02 2065,2107.98 2060.02,2103 2004,2103 1997,2096 1997,2088.98 2002,2083.98 2060.31,2083.98 2065,2079.29 2065,2072.67 2060.31,2067.98 2002,2067.98 1997,2062.98 1997,2055 2002,2050 2060.31,2050 2065,2045.31 2065,2038.69 2060.31,2034 2002,2034 1997,2029 1997,2023 2002,2018 2060.31,2018 2065,2013.31 2065,2006.69 2060.31,2002 2002,2002 1997,1997 1997,1991 2002,1986 2060.31,1986 2065,1981.31 2065,1974.69 2060.31,1970 2002,1970 1997,1965 1997,1959 2002,1954 2018.31,1954 2023,1949.31 2023,1942.69 2018.31,1938 2002,1938 1997,1933 1997,1926 2006,1917 2006,1899 1997,1890 1997,1621 2002,1616 2158,1616 2163,1611 2163,1492 2170,1485 2177,1485 2187,1475 2213.85,1475 2222,1466.85 2222,1287 2241,1268 2241,1243 2279,1205 2279,1145 v3(2285,1139)
  Bottom Layer w4: v3(2277.67,2219.34) U13.E13@2292.52,2204.49
  Bottom Layer w5: v3(2285,1139) 2301.99,1122.01 U17.C7@2302.52,1122.01
FMC_D23: U13.D13 U17.A8 | length 2238.4
  L4_SIG w4: v3(2217,1105) 2214,1105 2162.04,1156.96 2162.04,1193.96 2132,1224 2092,1224 2049.74,1266.26 2049.74,1271.92 2066.08,1288.26 2066.08,1293.92 2059.7,1300.3 2054.04,1300.3 2038.2,1284.46 2032.54,1284.46 2026.88,1290.12 2026.88,1295.78 2042.72,1311.62 2042.72,1317.28 2037.06,1322.94 2031.4,1322.94 2015.56,1307.1 2009.9,1307.1 2004.24,1312.76 2004.24,1318.42 2020.08,1334.26 2020.08,1339.92 2014.42,1345.58 2008.76,1345.58 1992.92,1329.74 1987.26,1329.74 1981.6,1335.4 1981.6,1341.06 1997.44,1356.9 1997.44,1362.56 1991.78,1368.22 1986.12,1368.22 1970.28,1352.38 1964.62,1352.38 1958.96,1358.04 1958.96,1363.7 1974.8,1379.54 1974.8,1385.2 1969.14,1390.86 1963.48,1390.86 1947.64,1375.02 1941.98,1375.02 1936.32,1380.68 1936.32,1386.34 1952.16,1402.18 1952.16,1407.84 1946.5,1413.5 1940.84,1413.5 1925,1397.66 1919.34,1397.66 1913.68,1403.32 1913.68,1408.98 1929.52,1424.82 1929.52,1430.48 1908,1452 1908,2092 2086,2270 2291,2270 2296,2265 2296,2255.83 2291,2250.83 v3(2277.67,2250.83)
  Bottom Layer w5: v3(2217,1105) 2153,1105 2148,1100 2148,1045 2153,1040 2165,1040 2170,1045 2170,1081 2175,1086 2235.02,1086 U17.A8@2239.53,1090.51 ; v3(2277.67,2250.83) U13.D13@2292.52,2235.98
FMC_D24: U13.E14 U17.A2 | length 2269.2
  L4_SIG w4: v3(2099,2171) 2099,2186 2095,2190 2074,2190 1985,2101 1985,1929.05 1972,1916.05 1972,1564 1976,1560 2103,1560 2107,1556 2107,1548 2103,1544 1978,1544 1973,1539 1973,1531 1978,1526 2101,1526 2106,1521 2106,1375 2111,1370 2191,1370 2196,1365 2196,1356 2192,1352 2113.69,1352 2109,1347.31 2109,1340.69 2113.69,1336 2192,1336 2196,1332 2196,1296 v3(2194,1294)
  Bottom Layer w5: v3(2099,2171) 2136,2171 2153,2188 2244.53,2188 U13.E14@2261.02,2204.49 ; v3(2194,1294) 2194,1332 2189,1337 2064,1337 2059,1342 2059,1357 2064,1362 2213,1362 2218,1357 2218,1333 2223,1328 2251,1328 2256,1323 2256,1284.49 2251,1279.49 U17.A2@2239.53,1279.49
FMC_D25: U13.D14 U17.C3 | length 2242.8
  L4_SIG w4: v3(2099,2205.5) 2072.5,2205.5 1973,2106 1973,1939 1958,1924 1958,1519 1963,1514 2089,1514 2094,1509 2094,1420 2089,1415 2032.39,1415 2028,1410.61 2028,1404.39 2032.39,1400 2089.61,1400 2094,1395.61 2094,1389.39 2089.61,1385 2063,1385 2058,1380 2058,1374 2111.83,1320.17 2177,1320.17 2182,1315.17 2182,1308 2177,1303 2145.69,1303 2141,1298.31 2141,1291.69 2145.69,1287 2174,1287 2179,1282 2179,1263 2184,1258 2192,1258 2197,1253 2197,1230 2192,1225 2182,1225 2177,1230 v3(2177,1242)
  Bottom Layer w5: v3(2099,2205.5) 2122.5,2205.5 2140,2223 2222,2223 2223.52,2221.48 2246.52,2221.48 U13.D14@2261.02,2235.98 ; v3(2177,1242) 2177,1230.69 2172.31,1226 2013,1226 2008,1221 2008,1211 2013,1206 2297.52,1206 2302.52,1211 U17.C3@2302.52,1247.99
FMC_D26: U13.C14 U17.A1 | length 2247.2
  L4_SIG w4: v3(2098.61,2237.39) 2087.39,2237.39 1960,2110 1960,2090 1956.5,2086.5 1936.54,2086.5 1932,2081.96 1932,2075.54 1936.54,2071 1956,2071 1960,2067 1960,2059 1956,2055 1936,2055 1932,2051 1932,2043 1936,2039 1957,2039 1961,2035 1961,2027 1957,2023 1937,2023 1932,2018 1932,2010 1937,2005 1952,2005 1961,1996 1961,1944 1945,1928 1945,1507 1950,1502 2077,1502 2082,1497 2082,1432 2077,1427 2003.69,1427 1999,1422.31 1999,1416 2107.51,1307.49 2123.51,1307.49 2128,1303 2128,1287 2147,1268 2147,1259.98 2151.98,1255 2160,1255 2165,1260 2165,1271 v3(2164,1272)
  Bottom Layer w5: v3(2098.61,2237.39) 2114.22,2253 2223.5,2253 2236.02,2252.98 2250.52,2267.48 U13.C14@2261.02,2267.48 ; v3(2164,1272) 2164,1252 2159,1247 2060,1247 2055,1252 2055,1264 2060,1269 2140,1269 2145,1274 2145,1286 2140,1291 2059,1291 2054,1296 2054,1305.98 2059,1310.98 2153.02,1310.98 2187,1277 2205.55,1277 U17.A1@2239.53,1310.98
FMC_D27: U13.C13 U17.C2 | length 2224.9
  L4_SIG w4: v3(2310,2251) 2310,2246 2324,2232 2324,2212 2316,2204 2268,2204 2263,2199 2263,2178 2247,2162 2129,2162 2097,2130 2091.34,2130 2073,2148.34 2067.34,2148.34 2061.68,2142.68 2061.68,2137.02 2077,2121.7 2077,1963 2072,1958 2041,1958 2036,1953 2036,1928 2041,1923 2052,1923 2057,1928 2057,1941 2062,1946 2072,1946 2077,1941 2077,1669 2082,1664 2091,1664 2095,1668 2095,1706 2099,1710 2107,1710 2111,1706 2111,1668 2115,1664 2124,1664 2129,1669 2129,1704.68 2134,1709.68 2164,1709.68 2169,1704.68 2169,1669 2174,1664 2181,1664 2186,1669 2186,1684 2191,1689 2199,1689 2204,1684 2204,1669 2209,1664 2214,1664 2239,1639 2265,1639 2336,1568 2336,1437 2341,1432 2355,1432 2360,1427 2360,1419 2355,1414 2308,1414 2303,1409 2303,1372 2322,1353 2333,1353 2338,1358 2338,1381 2343,1386 2447,1386 2452,1381 2452,1371 2447,1366 2430,1366 2425,1361 2425,1349 2430,1344 2439,1344 2444,1339 2444,1328 2439,1323 2398,1323 2385,1310 2385,1305 2380,1300 2368,1300 2364,1304 2364,1317 2359,1322 2347,1322 2342,1317 2342,1306 2335,1299 2335,1291.81 2330.19,1287 2323.4,1287 2318.59,1291.81 v3(2318.59,1293.02)
  Bottom Layer w5: U13.C13@2292.52,2267.48 2293.62,2267.48 2310,2251.1 v3(2310,2251) ; U17.C2@2302.52,1279.49 2305.06,1279.49 v3(2318.59,1293.02)
FMC_D28: U13.D6 U17.B1 | length 2244.5
  L4_SIG w4: v1(2320,1380) 2315,1385 2315,1397 2320,1402 2393,1402 2398,1407 2398,1440 2393,1445 2355,1445 2350,1450 2350,1571 2270,1651 2244,1651 2220,1675 2220,1685 2183,1722 2094,1722 2089,1727 2089,2104 2135,2150 2249,2150 2275,2176 2275,2190 2280,2195 2287,2195 2292,2190 2292,2178.84 2297,2173.84 2415,2173.84 2420,2178.84 2420,2219 2425,2224 2439,2224 2444,2219 2444,2210 2449,2205 2506,2205 2511,2210 2511,2245.83 2516,2250.83 v3(2527.84,2250.83)
  Bottom Layer w5: U17.B1@2271.02,1310.98 2271.02,1333.98 2245,1360 2245,1479 2250,1484 2265,1484 2270,1479 2270,1360 2275,1355 2290,1355 2295,1360 2295,1480 2300,1485 2315,1485 2320,1480 v1(2320,1380) ; U13.D6@2512.99,2235.98 v3(2527.84,2250.83)
FMC_D29: U13.D4 U17.D2 | length 2229.2
  L4_SIG w4: v3(2350,1265) 2350,1255 2355,1250 2361,1250 2366,1255 2366,1275.61 2370.39,1280 2397.88,1280 2402.88,1275 2402.88,1263 2407.88,1258 2454,1258 2459,1263 2459,1274 2464,1279 2507,1279 2518,1290 2518,1370 2513,1375 2502,1375 2497,1370 2497,1363 2492,1358 2481,1358 2476,1363 2476,1459 2471,1464 2465,1464 2460,1469 2460,1477 2465,1482 2471,1482 2476,1487 2476,1496 2471,1501 2379,1501 2374,1506 2374,1581 2274,1681 2274,1699 2268,1705 2238,1705 2193,1750 2159,1750 2154,1755 2154,1761 2149,1766 2141,1766 2136,1761 2136,1754 2131,1749 2118,1749 2113,1754 2113,1761.31 2117.69,1766 2122,1766 2127,1771 2127,1779 2122,1784 2117.21,1784 2113,1788.21 2113,1794.17 2117.21,1798.38 2122.5,1798.38 2126.5,1802.38 2126.5,1810.38 2122.5,1814.38 2117.69,1814.38 2113,1819.07 2113,1825.69 2117.69,1830.38 2121.31,1830.38 2126,1835.07 2126,1841.69 2121.31,1846.38 2117,1846.38 2113,1850.38 2113,2092 2146,2125 2254,2125 2273,2106 2273,2088 2279,2082 2287,2082 2294,2089 2294,2107 2297,2110 2319,2110 2324,2115 2324,2130 2329,2135 2343,2135 2348,2130 2348,2126 2353,2121 2530,2121 2535,2126 2535,2137 2530,2142 2517,2142 2512,2147 2512,2168.84 2517,2173.84 2539.84,2173.84 2546,2180 2546,2193.8 2554.2,2202 2602,2202 2607,2207 2607,2216.13 2602,2221.13 v3(2590.83,2221.13)
  Bottom Layer w5: U17.D2@2334.02,1279.49 2348.51,1265 v3(2350,1265) ; U13.D4@2575.98,2235.98 v3(2590.83,2221.13)
FMC_D30: U13.E4 U17.D3 | length 2236.2
  L4_SIG w4: v3(2351,1231) 2349,1229 2349,1210 2354,1205 2362,1205 2367,1210 2367,1242 2372,1247 2489,1247 2505,1231 2505,1192 2510,1187 2520,1187 2525,1192 2525,1235 2513,1247 2513,1271 2530,1288 2530,1382 2525,1387 2493,1387 2488,1392 2488,1490 2493,1495 2532,1495 2537,1500 2537,1508 2532,1513 2391,1513 2386,1518 2386,1586 2286,1686 2286,1704 2273,1717 2243,1717 2197.95,1762.05 2169.93,1762.05 2163,1768.98 2163,1776.37 2161,1778.37 2161,1850 2156,1855 2130,1855 2125,1860 2125,2086 2152,2113 2252,2113 2263,2102 2263,2054 2269,2048 2288,2048 2294,2054 2294,2075 2299,2080 2321,2080 2326,2085 2326,2104 2332,2110 2538,2110 2543,2115 2543,2163 2560,2180 v3(2560,2188)
  Bottom Layer w5: U17.D3@2334.02,1247.99 v3(2351,1231) ; v3(2560,2188) 2560,2188.51 U13.E4@2575.98,2204.49
FMC_D31: U13.D5 U17.E2 | length 2253.8
  L4_SIG w4: v3(2350.66,1294.34) 2354,1291 2390,1291 2395,1296 2395,1307 2400,1312 2422,1312 2427,1307 2427,1275 2432,1270 2440,1270 2445,1275 2445,1307 2450,1312 2485,1312 2490,1307 2490,1294 2495,1289 2504,1289 2509,1294 2509,1320 2504,1325 2459,1325 2454,1330 2454,1353 2464,1363 2464,1413 2459,1418 2434,1418 2429,1413 2429,1403 2424,1398 2415,1398 2410,1403 2410,1428 2415,1433 2459,1433 2464,1438 2464,1448 2459,1453 2402,1453 2397,1458 2397,1465 2402,1470 2420,1470 2425,1475 2425,1483 2420,1488 2367,1488 2362,1493 2362,1576 2275,1663 2249,1663 2234,1678 2234,1688 2185,1737 2106,1737 2101,1742 2101,2097 2142,2138 2195.98,2138 2196.98,2139 2255,2139 2258,2142 2294,2142 2296,2144 2365.15,2144 2370.15,2139 2426,2139 2431,2144 2431,2175.02 2435.98,2180 2443.02,2180 2448,2175.02 2448,2138 2453,2133 2477,2133 2482,2138 2482,2168 2487,2173 2502,2173 2513.84,2184.84 2513.84,2193.64 2522.04,2201.84 2536.84,2201.84 2545,2210 2545,2245.83 2550,2250.83 v3(2559.34,2250.83)
  Bottom Layer w5: v3(2350.66,1294.34) U17.E2@2365.51,1279.49 ; U13.D5@2544.49,2235.98 v3(2559.34,2250.83)
FMC_NBL0: U13.A6 U17.K9 | length 2360.2
  L4_SIG w4: v3(2512.99,2356) 2508.99,2352 2332,2352 2303,2323 2064.41,2323 1860,2118.59 1860,1385 2230,1015 2504.99,1015 v3(2522.99,1033)
  Bottom Layer w4: U13.A6@2512.99,2330.47 v3(2512.99,2356)
  Bottom Layer w5: v3(2522.99,1033) U17.K9@2522.99,1059.02
FMC_NBL1: U13.A5 U17.K1 | length 2463.1
  L4_SIG w4: v3(2478,1201) 2411.36,1096.46 2398.25,1076.06 2391.15,1065 2391,1065 2388.5,1062.5 2381.75,1058.05 2329,1030 2234,1030 1872,1392 1872,2112.2 2070.8,2311 2306,2311 2522.89,2341.59 v3(2543.96,2352)
  Bottom Layer w4: v3(2478,1201) 2507,1246 2507,1280 U17.K1@2522.99,1310.98
  Bottom Layer w5: v3(2543.96,2352) 2543.96,2331 U13.A5@2544.49,2330.47
FMC_NBL2: U13.C3 U17.F8 | length 2303.6
  L4_SIG w4: v3(2380,1074) 2359,1074 2328,1043 2242,1043 2135,1150 2135,1187 2122,1200 2082,1200 1884,1398 1884,2102.98 2080.02,2299 2300,2299 2317,2282 2331.99,2267 2477,2267 2482,2272 2482,2291.33 2487,2296.33 2551.67,2296.33 2580,2268 2607,2268 v3(2623,2252)
  Bottom Layer w4: U13.C3@2607.48,2267.48 v3(2623,2252)
  Bottom Layer w5: v3(2380,1074) 2396.51,1090.51 U17.F8@2397.01,1090.51
FMC_NBL3: U13.D3 U17.F2 | length 2397.9
  L4_SIG w4: v3(2388,1207) 2388,1121 2322,1055 2247,1055 2150,1152 2150,1189 2127,1212 2087.02,1212 2086.02,1213 1896,1403 1896,2098 2083,2285 2298,2285 2325,2258 2325,2244 2334,2235 2475,2235 2506,2266 2563.97,2266 2577.97,2252 v3(2591,2252)
  Bottom Layer w4: v3(2591,2252) 2593,2250 2593.46,2250 U13.D3@2607.48,2235.98
  Bottom Layer w5: v3(2388,1207) 2412,1231 2412,1264.5 U17.F2@2397.01,1279.49
FMC_SDCKE0: U13.K4 U17.J2 | length 2218
  Top Layer w5: v1(2443,1475) 2443,1450 2448,1445 2460,1445 2465,1450 2465,1481 2478,1494 2542.22,1494 2546.22,1490 2665,1490 2670,1495 2670,1505 2665,1510 2645,1510 2640,1515 2640,1525 2645,1530 2665,1530 2670,1535 2670,1575 2665,1580 2438,1580 2433,1585 2433,1595 2438,1600 2476,1600 2480,1596 2665,1596 2670,1601 2670,1613 2665,1618 2425,1618 2420,1623 2420,1633.7 2425,1638.7 2450,1638.7 2455,1643.7 2455,1653.7 2450,1658.7 2425,1658.7 2420,1663.7 2420,1702.71 2425,1707.71 2450,1707.71 2455,1712.71 2455,1722.71 2450,1727.71 2425,1727.71 2420,1732.71 2420,1742.71 2425,1747.71 2441,1747.71 2446,1752.71 2446,1762.71 2441,1767.71 2425,1767.71 2420,1772.71 2420,1786 2423.5,1789.5 2431,1789.5 2436,1794.5 2436,1839 2430,1845 2420,1845 2415,1850 2415,1910 2439.5,1934.5 2439.5,1996.5 2460,2017 2470.2,2017 2481,2027.8 2481,2043 2486,2048 2555,2048 2560,2053 v3(2560,2062)
  Bottom Layer w4: v3(2560,2062) 2560.99,2062 U13.K4@2575.98,2047.01
  Bottom Layer w5: v1(2443,1475) 2448,1470 2448,1402 2453,1397 2514.18,1397 2530,1381.18 2530,1340 2507,1317 2507,1305 2491.5,1289.5 U17.J2@2491.5,1279.49
FMC_SDCLK: TP26.1 U13.H14 U17.J1 | length 2225
  L4_SIG w4: v3(2246.17,2095.15) 2249,2092.32 2249,2060 2244,2055 2234.74,2055 2230,2059.74 2230,2093 2225,2098 2213.85,2098 2208.85,2093 2208.85,2047.64 2204.21,2043 2197.64,2043 2193,2047.64 2193,2092 2188,2097 2159,2097 2141,2079 2141,1918 2145,1914 2204,1914 2208,1910 2208,1902 2204,1898 2146,1898 2141,1893 2141,1885 2146,1880 2203,1880 2208,1875 2208,1868 2203,1863 2182,1863 2177,1858 2177,1785 2182,1780 2192,1780 2197,1785 2197,1797 2202,1802 2212,1802 2217,1797 2217,1766 2250,1733 2284,1733 2302,1715 2302,1693 2422,1573 2422,1552 2427,1547 2448,1547 2453,1542 2453,1534 2448,1529 2407,1529 2402,1534 2402,1561 v1(2404,1563)
  Bottom Layer w4: v3(2246.17,2095.15) U13.H14@2261.02,2110
  Bottom Layer w5: v1(2404,1563) 2404,1583 2399,1588 2173,1588 2165,1580 2165,1539 2173,1531 TP26.1@2262,1531 2415,1531 2420,1526 2420,1382 2425,1377 2505,1377 2510,1372 2510,1337 2491.5,1318.5 U17.J1@2491.5,1310.98
FMC_SDNCAS: U13.B7 U17.K7 | length 2296.9
  Top Layer w5: v3(2497.35,2281.83) 2513.34,2265.84 2513.34,2150 2523.34,2140 2629.33,2140 2639.33,2150 2639.33,2162.36 2647.82,2170.85 2674.15,2170.85 2692,2153 2692,2063 2745,2010 2761.78,2010 2848.78,1923 2927,1923 2960,1890 2995,1890 3000,1885 3000,1650 3025,1625 3025,1034 3015,1024 2596,1024 2554,1066 2554,1121 v3(2537.98,1137)
  Bottom Layer w5: U13.B7@2481.5,2298.98 2481.5,2297.68 v3(2497.35,2281.83) ; U17.K7@2522.99,1122.01 v3(2537.98,1137)
FMC_SDNE0: U13.J4 U17.J8 | length 2252.7
  Top Layer w5: v3(2507,1105) 2507,1178 2512,1183 2564,1183 2580,1167 2721,1167 2726,1162 2726,1062 2731,1057 2740,1057 2745,1062 2745,1080 2750,1085 2864.95,1085 2869.95,1080 2869.95,1060 2874.95,1055 2884.95,1055 2889.95,1060 2889.95,1080 2894.95,1085 2904.95,1085 2909.95,1080 2909.95,1060 2914.95,1055 2990,1055 2995,1060 2995,1605 2965,1635 2965,1763 2960,1768 2910,1768 2905,1773 2905,1885 2900,1890 2750,1890 2745,1895 2745,1960 2740,1965 2712,1965 2707,1970 2707,2006 2702,2011 2669,2011 2664,2016 2664,2072 2659,2077 2644,2077 2639,2082 2639,2101 2630,2110 2576.13,2110 v3(2561,2094.87)
  Bottom Layer w4: v3(2561,2094.87) 2575.98,2079.89 U13.J4@2575.98,2078.5
  Bottom Layer w5: U17.J8@2491.5,1090.51 2492.51,1090.51 v3(2507,1105)
FMC_SDNRAS: U13.P8 U17.J9 | length 2227.6
  Top Layer w5: v3(2464.85,1906.17) 2464.85,1870 2469.85,1865 2480,1865 2485,1870 2485,1880 2490,1885 2500,1885 2505,1880 2505,1870 2510,1865 2550,1865 2555,1860 2555,1780 2560,1775 2655,1775 2660,1770 2660,1740 2665,1735 2675,1735 2680,1740 2680,1770 2685,1775 2700,1775 2705,1770 2705,1700 2715,1690 2785,1690 2790,1685 2790,1675 2785,1670 2720,1670 2715,1665 2715,1655 2720,1650 2785,1650 2790,1645 2790,1635 2785,1630 2720,1630 2715,1625 2715,1615 2720,1610 2785,1610 2790,1605 2790,1595 2785,1590 2720,1590 2715,1585 2715,1575 2720,1570 2785,1570 2790,1565 2790,1555 2785,1550 2720,1550 2715,1545 2715,1535 2720,1530 2785,1530 2790,1525 2790,1402 2785,1397 2453,1397 2448,1392 2448,1159 2470,1137 2470,1092 2460,1082 2460,1047 2466,1041 v3(2477.23,1041)
  Bottom Layer w5: U13.P8@2450,1921.02 v3(2464.85,1906.17) ; v3(2477.23,1041) 2477.23,1044.75 U17.J9@2491.5,1059.02
FMC_SDNWE: TP28.1 U13.J3 U17.K8 | length 2375
  Top Layer w5: v3(2508,1075.66) 2497,1075.66 2492,1080.66 2492,1197 2497,1202 2680,1202 2685,1197 2685,1185 2690,1180 2740,1180 2745,1175 2745,1105 2750,1100 2924.95,1100 2929.95,1095 2929.95,1075 2934.95,1070 2975,1070 2980,1075 2980,1595 2950,1625 2950,1705 2945,1710 2895,1710 2890,1715 2890,1725 2895,1730 2945,1730 2950,1735 2950,1745 2945,1750 2895,1750 2890,1755 2890,1870 2885,1875 2735,1875 2730,1880 2730,1945 2725,1950 2700,1950 2695,1955 2695,1960 2690,1965 2655,1965 2650,1970 2650,2042 2645,2047 2595.28,2047 2590.28,2052 v3(2590.28,2061)
  Bottom Layer w4: v3(2590.28,2061) 2590.28,2061.3 U13.J3@2607.48,2078.5
  Bottom Layer w5: TP28.1@2470,930 2508,1060 v3(2508,1075.66) 2508.15,1075.66 U17.K8@2522.99,1090.51
LCD_BL_CTRL: CN1.53 U13.H3 | length 1651.9
  Top Layer w5: v1(2985,2170) 2970,2185 2968,2185 2968,2384 3125,2541 v1(3125,2920) ; v1(3263.61,3206.39) CN1.53@3263.61,3276.53
  L4_SIG w4: v3(2622.33,2095.15) 2637.18,2110 2925,2110 v1(2985,2170)
  Bottom Layer w4: U13.H3@2607.48,2110 v3(2622.33,2095.15)
  Bottom Layer w5: v1(3125,2920) 3189,2984 3189,3131.78 v1(3263.61,3206.39)
LCD_INT: CN1.4 U13.G3 | length 1987.5
  Top Layer w5: CN1.4@3755.74,3050.55 3755.74,3105.74 v1(3765,3115)
  L4_SIG w4: v3(2622.33,2156.35) 2639.82,2173.84 2723.84,2173.84 2750,2200 2908,2200 2938,2230 3177,2230 v1(3185,2238)
  Bottom Layer w4: U13.G3@2607.48,2141.5 v3(2622.33,2156.35)
  Bottom Layer w5: v1(3185,2238) 3190,2243 3190,2590 3265,2665 3265,2838 3336,2909 3336,2986 3380,3030 3695,3030 3765,3100 v1(3765,3115)
LD_USER1: R62.1 U13.B9 | length 2862
  Top Layer w5: R62.1@1290,390 1315,390 v1(1355,430)
  L4_SIG w4: v1(1355,430) 1385,460 1496,460 1773,737 1773,2108 2083,2418 2281,2418 2296,2403 2296,2387 2314,2369 v1(2402.5,2369)
  Bottom Layer w5: v1(2402.5,2369) 2402.5,2314.98 U13.B9@2418.5,2298.98
LD_USER2: R63.1 U13.M14 | length 2146.4
  Top Layer w5: R63.1@1390,390 1390,425 v1(1395,430)
  L4_SIG w4: v1(1395,430) 1405,440 1500,440 1791,731 v1(1791,1618)
  Bottom Layer w5: v1(1791,1618) 1938,1765 1938,1893 1985,1940 2167.26,1940 2194.28,1967.02 2244.02,1967.02 U13.M14@2261.02,1984.02
LED_G_A: CN10.12 R28.2 U3.3 | length 1147
  Top Layer w5: U3.3@3664.84,1926.77 3664.84,1975.16 R28.2@3660,1980 3680,2000 3680,2070 3737.5,2127.5 4097.5,2127.5 4255,2285 4546.14,2285 CN10.12@4573.19,2257.95
LED_G_K: CN10.11 R105.2 | length 136.5
  Bottom Layer w5: R105.2@4455,2210 4533.77,2210 4553.77,2190 CN10.11@4573.19,2167.8
LED_STLINK: R60.1 R61.1 U19.30 | length 417.4
  Top Layer w5: R60.1@3420,385 R61.1@3480,385 3735,385 v1(3775,425)
  Bottom Layer w5: U19.30@3769.84,468.74 3769.84,430.16 v1(3775,425)
LED_Y_A: CN10.10 R29.2 U3.2 | length 1344.1
  Top Layer w5: U3.2@3684.53,1926.77 3684.53,1949.53 3700,1965 R29.2@3700,1980 3703,1980 v1(3723,2000)
  Bottom Layer w5: v1(3723,2000) 3725,2000 3740,1985 3740,1730 3880,1590 4340,1590 4415,1665 4445,1665 4572.2,1792.2 CN10.10@4573.19,1792.2
LED_Y_K: CN10.9 R113.2 | length 72.5
  Bottom Layer w5: CN10.9@4573.19,1702.05 4575.97,1630.97 R113.2@4575,1630
LRCLK: CN1.37 TP3.1 | length 113.2
  Top Layer w5: v1(3405,3210) 3405,3215 3421.09,3231.09 CN1.37@3421.09,3276.53
  Bottom Layer w5: TP3.1@3405,3170 v1(3405,3210)
MIC_CLK: TP105.1 U11.C6 | length 400.8
  L4_SIG w3.5: 950,2495 960,2485 960,2470 1014.44,2415.56 v4(1015.22,2415.56)
  L4_SIG w4: v1(760,2610) 795,2575 870,2575 950,2495
  Bottom Layer w3.5: U11.C6@1005.47,2425.31 v4(1015.22,2415.56)
  Bottom Layer w5: TP105.1@730,2640 v1(760,2610)
MIC_DATA1: TP106.1 U11.B9 | length 255.1
  Bottom Layer w5: TP106.1@850,2185 880,2215 880,2270 945,2335 975,2335 985.79,2345.79 U11.B9@985.79,2366.26
MIC_DATA2: TP107.1 U11.A9 | length 158
  Bottom Layer w5: TP107.1@850,2265 940,2355 954.84,2355 U11.A9@966.1,2366.26
MIC_VDD1: C79.2 TP108.1 U11.A7 | length 183.4
  Bottom Layer w5: TP108.1@845,2340 C79.2@845,2400 960.47,2400 U11.A7@966.1,2405.63
MIC_VDD2: C73.2 TP109.1 U11.B6 | length 360.2
  L4_SIG w4: v1(881.59,2455) 941.88,2455 975.94,2420.94 v4(975.94,2415.46)
  Bottom Layer w3.5: v4(975.94,2415.46) U11.B6@985.79,2425.31
  Bottom Layer w5: TP109.1@730,2565 730,2505 750,2485 815,2485 C73.2@845,2455 v1(881.59,2455)
NC1: TP17.1 U13.C6 | length 232
  Top Layer w4: v3(2527.84,2282.33) 2527.84,2359.25 2532.59,2364
  Top Layer w5: v1(2527.5,2440) 2527.5,2437.5 2541,2424 2541,2372.41 2532.59,2364
  Bottom Layer w5: TP17.1@2510,2475 2527.5,2457.5 v1(2527.5,2440) ; U13.C6@2512.99,2267.48 v3(2527.84,2282.33)
NC2: TP16.1 U13.C5 | length 220.2
  Bottom Layer w5: U13.C5@2544.49,2267.48 2560,2282.99 2560,2460 TP16.1@2575,2475
NC3: TP15.1 U13.C4 | length 332.7
  Top Layer w5: v3(2590.83,2282.33) 2647,2338.5 2647,2481 v1(2680,2514)
  Bottom Layer w4: U13.C4@2575.98,2267.48 v3(2590.83,2282.33)
  Bottom Layer w5: TP15.1@2670,2475 2680,2485 v1(2680,2514)
NC4: TP12.1 U13.C2 | length 347.6
  Bottom Layer w5: U13.C2@2638.98,2267.48 2653.83,2282.33 2674.33,2282.33 2697,2305 2697,2393 2725,2421 2725,2525 TP12.1@2755,2555
NC5: TP13.1 U13.E3 | length 438.9
  Top Layer w5: v3(2622.33,2219.34) 2622.33,2224.33 2655,2257 2655,2300 2709,2354 2709,2416 2725,2432 2725,2541 v1(2716,2550)
  Bottom Layer w4: U13.E3@2607.48,2204.49 v3(2622.33,2219.34)
  Bottom Layer w5: TP13.1@2675,2550 v1(2716,2550)
NC6: TP14.1 U13.D1 | length 311.9
  Bottom Layer w5: U13.D1@2670.47,2235.98 2681.45,2225 2700,2225 2717,2242 2717,2389 2755,2427 TP14.1@2755,2480
NC7: TP9.1 U13.D8 | length 472.5
  Bottom Layer w5: U13.D8@2450,2235.98 2435,2250.98 2435,2334.48 2432,2337.48 2432,2414 2440.5,2422.5 2452.5,2422.5 2470,2440 2470,2615 2490,2635 TP9.1@2525,2635
NC8: TP18.1 U13.D7 | length 324
  Top Layer w5: v1(2440,2440) 2440.53,2440 2443.06,2437.47 2461.53,2437.47 2477,2422 2477,2317 2450,2290 2450,2235 v3(2465,2220)
  Bottom Layer w4: v3(2465,2220) 2480.98,2235.98 U13.D7@2481.5,2235.98
  Bottom Layer w5: TP18.1@2435,2475 2435,2445 v1(2440,2440)
NETB1_2: B1.2 B1.3 R68.2 R70.2 | length 478.2
  Top Layer w5: B1.3@607.83,212.5 B1.2@962.17,212.5 1037.5,212.5 R70.2@1040,215 R68.2@1040,260
NETB2_1: B2.1 B2.4 C53.2 R67.1 SB10.2 | length 555.3
  Top Layer w5: 3985,270 R67.1@3985,325 C53.2@3985,395 4007.5,395 4015,387.5 B2.4@4057.83,387.5 B2.1@4412.17,387.5
NETC4_1: C4.1 C5.1 C8.1 C40.1 C122.1 D10.1 R1.1 R3.1 R48.2 U1.8 U1.17 | length 2365.9
  Top Layer w20: v1(4320,3265) C4.1@4360,3265 4356.14,3261.14 U1.8@4356.14,3209.57 ; C8.1@4510,3130 v1(4555,3130) ; C5.1@4510,3255 v1(4555,3255) ; R1.1@4510,3310 v1(4555,3310) ; R3.1@4515,3190 v1(4555,3190) ; C40.1@4525,1355 R48.2@4525,1435 4560,1470 v1(4565,1470)
  L4_SIG w20: v1(4555,3130) 4490,3065 4490,2854 4460,2824 4460,2200 4419,2159 4419,1831 4457,1793 4457,1656 4517,1596 4517,1518 v1(4565,1470)
  Bottom Layer w20: C122.1@4460,1565 4460,1499.8 D10.1@4485,1474.8 4489.8,1470 v1(4565,1470)
  other v1: 4195,3065 4240,3065 4285,3065 4195,3125 4240,3125 4285,3125 4195,3175 4240,3175 4285,3175
NETC5_2: C5.2 U1.6 | length 154.4
  Top Layer w10: U1.6@4356.14,3158.39 4388.39,3158.39 4411.14,3181.14 4411.14,3216.14 C5.2@4450,3255
NETC6_2: C6.2 C24.2 D3.2 R25.2 U1.11 | length 1106.7
  Top Layer w10: C6.2@4025,3205 v1(4062.5,3167.5) 4071.61,3158.39 U1.11@4123.86,3158.39
  L4_SIG w15: v1(3588,2585) 3588,2654 3719,2785 3790,2785 3905,2900 3905,2977 4030,3102 4030,3135 v1(4062.5,3167.5)
  Bottom Layer w15: R25.2@3570,2675 C24.2@3570,2620 3570,2615 3588,2597 v1(3588,2585) 3588,2582 3615,2555 D3.2@3644.29,2555
NETC7_2: C7.2 R25.1 U1.12 | length 822.2
  Top Layer w10: C7.2@4025,3155 4047.2,3132.8 v1(4065,3132.8) U1.12@4123.86,3132.8
  L4_SIG w15: v1(3670,2675) 3744.99,2749.99 3834.99,2749.99 3930,2845 3930,2968 4065,3103 v1(4065,3132.8)
  Bottom Layer w20: R25.1@3630,2675 v1(3670,2675)
NETC8_2: C8.2 R75.1 U1.4 | length 156.3
  Top Layer w10: U1.4@4356.14,3107.2 v1(4405,3107.2) 4427.2,3107.2 C8.2@4450,3130
  Bottom Layer w10: v1(4405,3107.2) 4412.2,3100 R75.1@4455,3100
NETC9_2: C9.2 R4.1 U1.13 | length 154.8
  Top Layer w10: R4.1@4025,3050 C9.2@4025,3105 4027.2,3107.2 U1.13@4123.86,3107.2
NETC10_1: C10.1 U1.3 | length 96.6
  Top Layer w10: U1.3@4356.14,3081.61 4443.39,3081.61 C10.1@4450,3075
NETC11_1: C11.1 U1.2 | length 108.8
  Top Layer w10: U1.2@4356.14,3056.02 4413.98,3056.02 C11.1@4450,3020
NETC12_2: C12.2 R5.1 | length 55
  Top Layer w5: C12.2@3965,2945 R5.1@3965,3000
NETC17_1: C17.1 C19.1 C200.2 R85.2 U2.3 | length 334.3
  Top Layer w20: C19.1@3955,2655 v1(3985,2685) C17.1@3955,2715 3955,2779.84 U2.3@3957.76,2782.6
  Bottom Layer w20: R85.2@3890,2800 C200.2@3890,2735 3940,2685 v1(3985,2685)
NETC17_2: C17.2 R11.1 R13.2 R14.2 R15.2 U2.4 | length 321.6
  Top Layer w20: U2.4@4052.24,2782.6 4032.6,2782.6 4015,2765 C17.2@4015,2715 R13.2@4070,2715 R14.2@4125,2715 R15.2@4180,2715 4185,2720 R11.1@4185,2775
NETC18_2: C18.2 C21.2 D2.2 R16.1 | length 424.7
  Top Layer w20: 4375,2671.98 C18.2@4375,2705 4405.52,2705 ; 4423.48,2709.49 R16.1@4455,2709.49 ; 4455,2676.97 R16.1@4455,2709.49 ; 4486.52,2709.49 R16.1@4455,2709.49
  Bottom Layer w20: 4471.98,2575.55 D2.2@4525,2575.55 ; 4525,2532.53 D2.2@4525,2575.55 ; 4525,2618.57 D2.2@4525,2575.55 ; 4578.02,2575.55 D2.2@4525,2575.55 ; 4624.48,2535 C21.2@4650,2535 ; 4650,2510.98 C21.2@4650,2535 ; 4650,2559.02 C21.2@4650,2535
  other v1: 4520,2630 4545,2630 4495,2645 4520,2655 4545,2655
NETC19_2: C19.2 R13.1 | length 55
  Top Layer w20: C19.2@4015,2655 R13.1@4070,2655
NETC21_1: C21.1 R22.2 | length 110
  Bottom Layer w20: R22.2@4710,2425 C21.1@4710,2535
NETC22_1: C22.1 R23.1 | length 94.9
  Bottom Layer w20: R23.1@3539,2385 3539,2341 C22.1@3575,2305
NETC26_1: C26.1 C32.1 C34.1 C37.1 C89.2 | length 905
  Top Layer w20: C89.2@4252,2180 4302,2130 v1(4335,2130) C26.1@4370,2095 ; v1(4340,1566) 4375,1601 C37.1@4375,1610 ; C34.1@4375,1815 C32.1@4375,1865 v1(4375,1900)
  L4_SIG w20: v1(4335,2130) 4391,2074 4391,1916 v1(4375,1900) 4340,1865 v1(4340,1566)
NETC26_2: C26.2 R26.1 | length 65
  Top Layer w5: R26.1@4310,2030 C26.2@4310,2095
NETC28_2: C28.2 C29.2 U3.6 | length 118.1
  Top Layer w5: C28.2@3530,1970 3540,1980 C29.2@3580,1980 3605.79,1954.21 U3.6@3605.79,1926.77
NETC30_2: C30.2 C35.2 C36.1 L2.1 U3.1 U3.19 | length 793.4
  Top Layer w10: U3.1@3704.21,1926.77 3704.21,1933.71 3750,1979.5 C30.2@3750,1980 ; U3.19@3731.77,1800.79 3739.21,1800.79 3757,1783 3757,1781
  Top Layer w20: L2.1@3745,1675 C35.2@3800,1675 ; C30.2@3750,1980 3755,1980 3784,2009 v2(3784,2018) ; 3757,1781 3800,1738 C35.2@3800,1675 ; v2(3833,1757) 3870,1720 C36.1@3870,1675 C35.2@3800,1675
  L4_SIG w20: v2(3784,2018) 3784,1995 3838,1941 3838,1762 v2(3833,1757)
NETC31_2: C31.2 U13.L11 | length 301.1
  Top Layer w15: C31.2@2098,1985 2138,1985 2204.5,2051.5 2262.24,2051.5 2281.74,2032 v3(2341,2032)
  Bottom Layer w15: v3(2341,2032) 2341,2030.02 U13.L11@2355.51,2015.51
NETC32_2: C32.2 R33.1 | length 75
  Top Layer w5: C32.2@4315,1865 R33.1@4315,1940
NETC34_2: C34.2 R42.1 | length 60
  Top Layer w5: R42.1@4315,1755 C34.2@4315,1815
NETC37_2: C37.2 R46.1 | length 60
  Top Layer w5: C37.2@4315,1610 R46.1@4315,1670
NETC39_1: C39.1 D4.2 D9.2 R48.1 | length 359.1
  Top Layer w20: v1(4366.26,1393.74) D4.2@4366.26,1513.43 4436.57,1513.43 C39.1@4445,1505 R48.1@4525,1505
  Bottom Layer w20: D9.2@4366.26,1316.57 v1(4366.26,1393.74)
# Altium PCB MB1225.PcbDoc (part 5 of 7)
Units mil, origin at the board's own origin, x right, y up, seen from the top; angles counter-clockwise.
Board outline 5000 x 3464.56 mil, 6 copper layers (Top Layer, L2_GND, L3_VCC, L4_SIG, L5_GND, Bottom Layer), stack 62.2 mil thick; 453 components, 378 nets, 1982 pads, 949 vias.

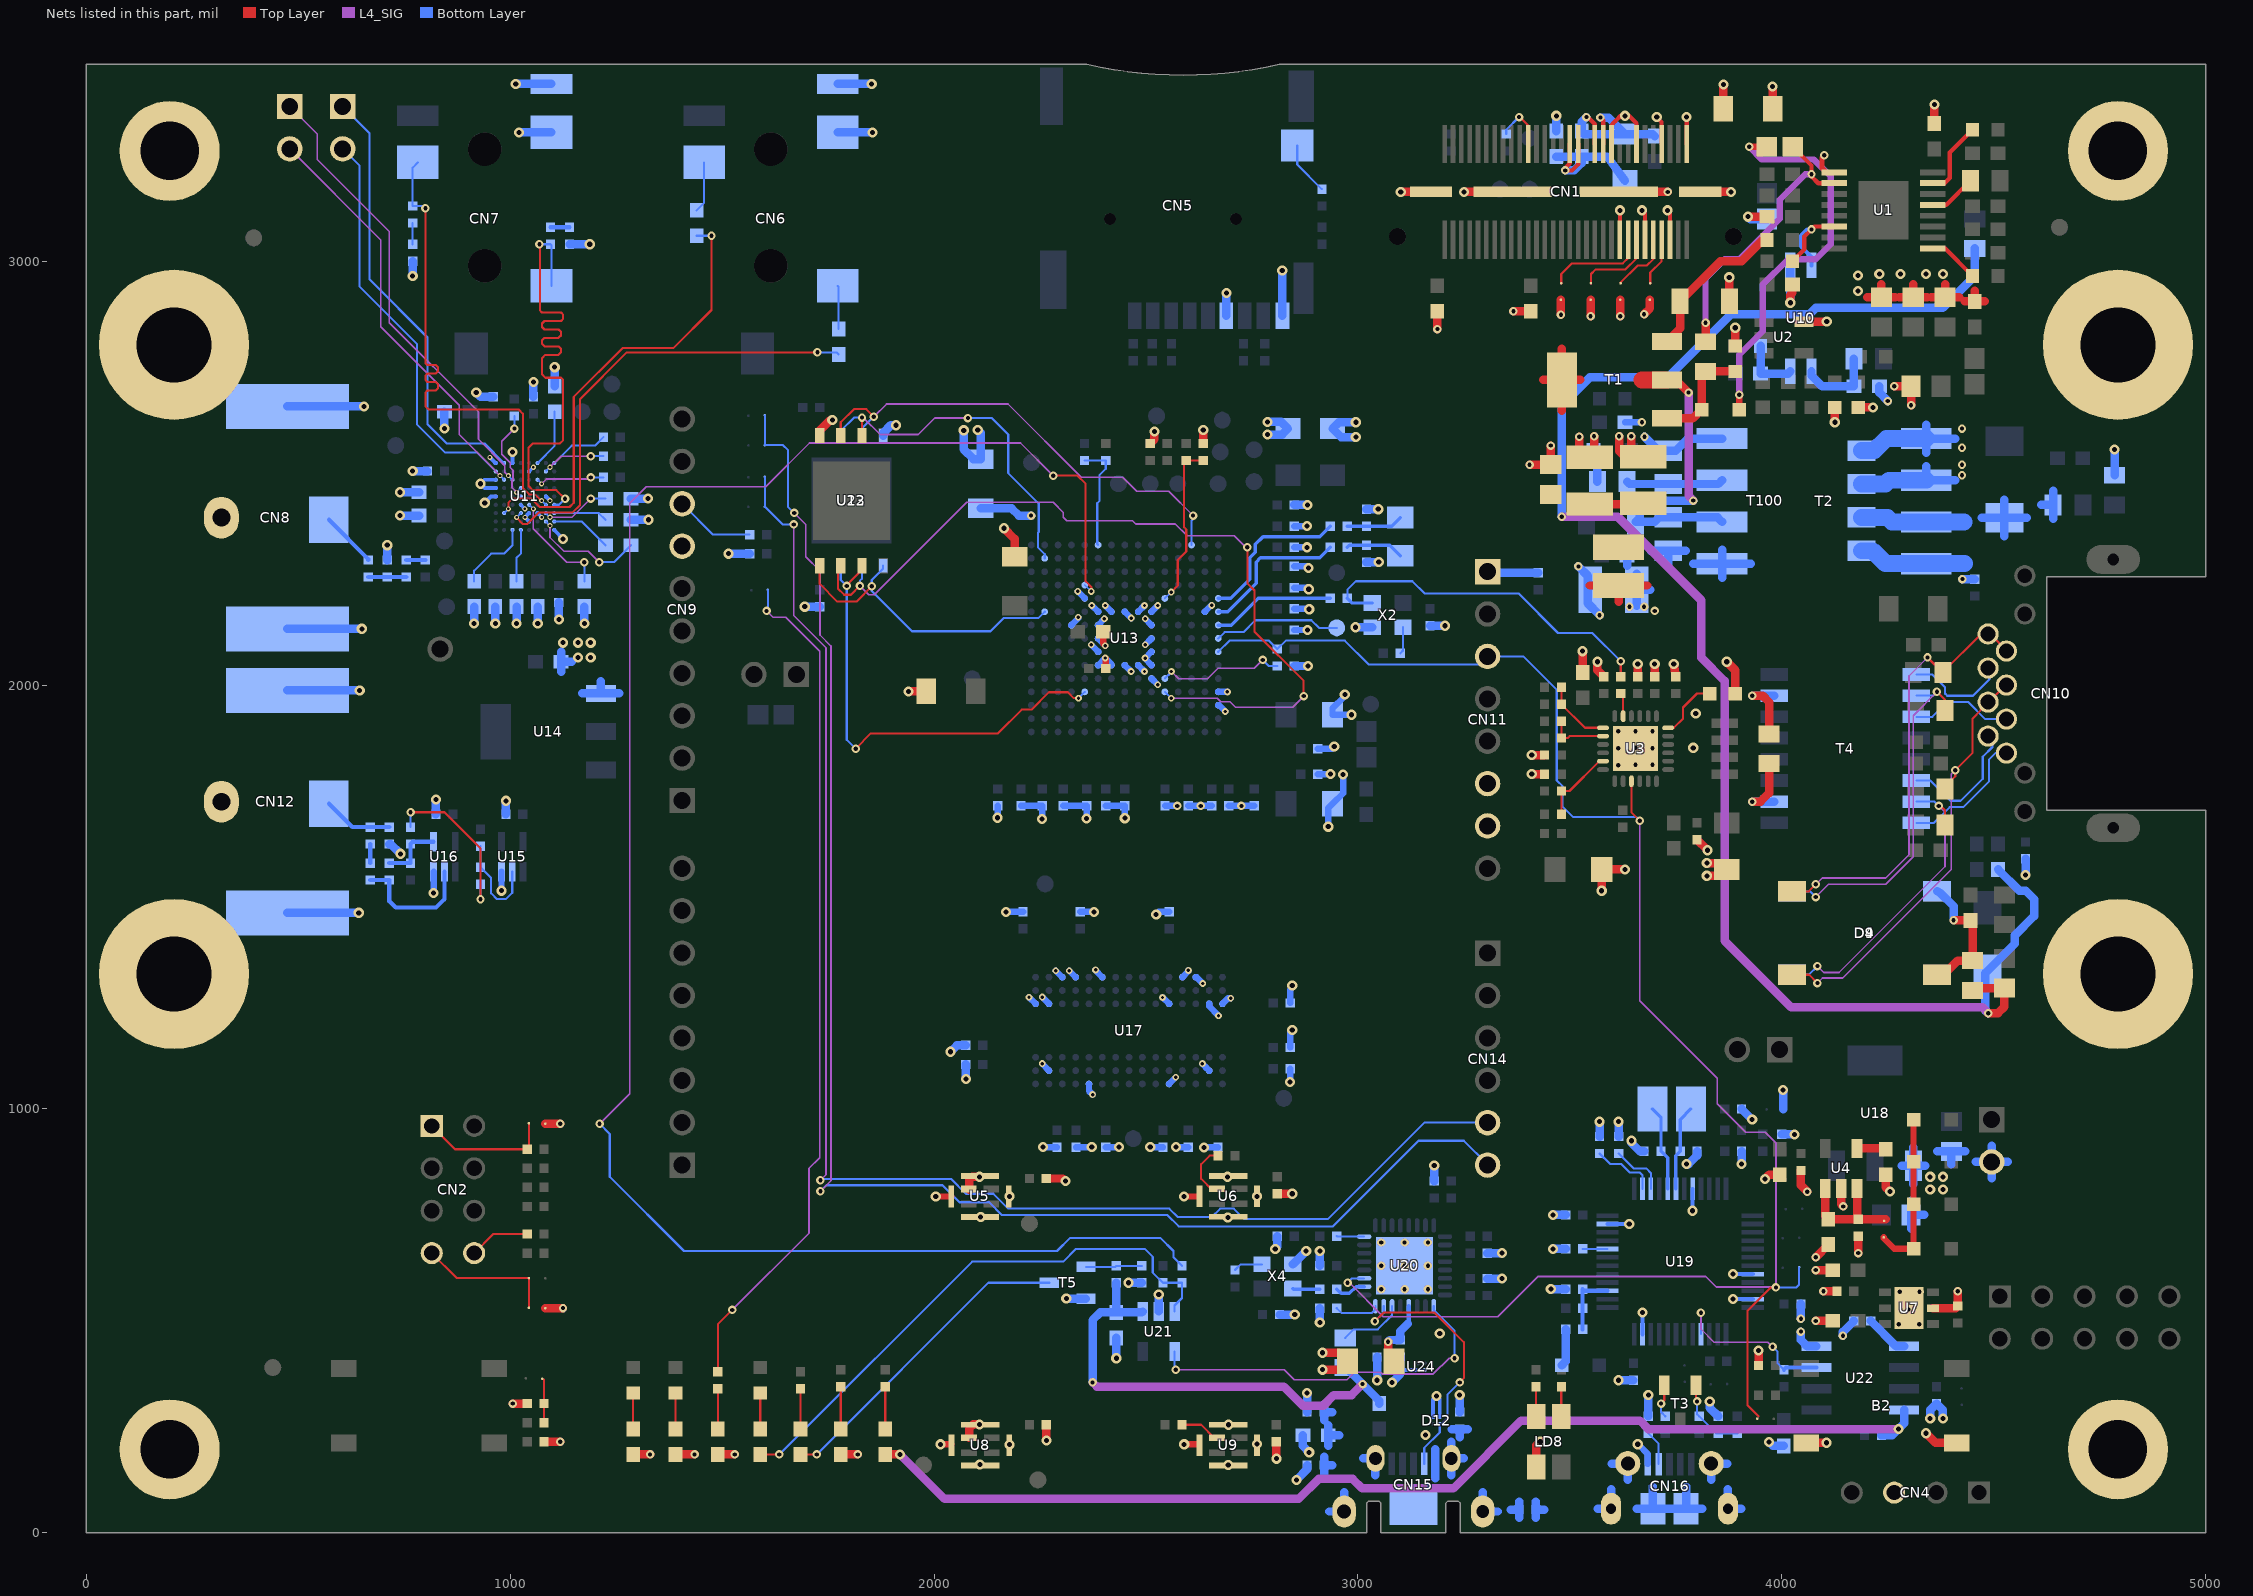
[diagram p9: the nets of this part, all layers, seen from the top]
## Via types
v1: diameter 20, hole 10, Top Layer to Bottom Layer, 354 vias
v2: diameter 24, hole 12, Top Layer to Bottom Layer, 347 vias
v3: diameter 16, hole 8, Top Layer to Bottom Layer, 221 vias
v4: diameter 12, hole 6, Top Layer to Bottom Layer, 27 vias

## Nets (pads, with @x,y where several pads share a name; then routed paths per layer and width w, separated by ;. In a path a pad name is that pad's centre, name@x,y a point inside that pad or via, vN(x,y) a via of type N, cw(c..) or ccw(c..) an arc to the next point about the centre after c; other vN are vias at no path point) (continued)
NETC39_2: C39.2 D4.1 D9.1 R49.1 | length 323.8
  Top Layer w20: D4.1@4366.26,1316.57 4376.57,1311.57 4415,1350 R49.1@4450,1350 4450,1440 C39.2@4445,1445 v1(4405,1445)
  Bottom Layer w20: D9.1@4366.26,1513.43 4375,1508.43 4405,1478.43 v1(4405,1445)
NETC40_2: C40.2 C70.2 C75.2 C81.2 C121.2 D10.2 L5.2 R49.2 R75.2 | length 4040.8
  Top Layer w20: C70.2@3586.98,2427 C75.2@3671.4,2427 ; R49.2@4450,1280 4455,1285 C40.2@4525,1285 4525,1241 4510,1226 v1(4487,1226)
  L4_SIG w20: v1(3481,2397) 3613,2397 3810,2200 3810,2065 3865,2010 3865,1397 4022,1240 4473,1240 v1(4487,1226)
  Bottom Layer w20: v1(3481,2397) 3481,2660 3547,2726 3731,2726 3880,2875 4065,2875 4080,2890 4380,2890 4455,2965 R75.2@4455,3030 ; v1(4487,1226) 4480,1233 4480,1320.2 D10.2@4485,1325.2 4549.8,1390 4549.8,1409.8 4595,1455 4595,1495 4575,1515 4560,1515 C121.2@4510,1565
NETC43_2: C43.2 U4.4 | length 68.5
  Top Layer w20: U4.4@4177.4,907.24 4242.76,907.24 C43.2@4245,905
NETC46_2: C46.2 C47.2 SB7.2 U4.1 U4.3 | length 286.7
  Top Layer w20: U4.1@4102.6,812.76 4102.6,747.4 C47.2@4110,740 C46.2@4180,740 ; U4.3@4177.4,812.76 4177.4,747.4 4182.4,742.4 C46.2@4180,740 ; 4245,740 C46.2@4180,740
NETC52_2: C52.2 C149.2 U20.20 | length 170.4
  Top Layer w20: v1(3071,451) 3071,419 C52.2@3085,405
  Bottom Layer w10: 3117,493 3119.84,495.84 U20.20@3119.84,534.72
  Bottom Layer w20: v1(3071,451) 3075,455 C149.2@3100,455 3100,476 3117,493
NETC54_2: C54.2 R68.1 SB9.2 | length 102.4
  Top Layer w5: 1079,362 1080,361 C54.2@1080,305 R68.1@1080,260
NETC57_1: C57.1 CN7.4 U11.G6 | length 1185
  Top Layer w5: v1(800,3125) 800,2759.98 805,2754.98 824.14,2754.98 830,2749.12 830,2740.84 824.14,2734.98 805,2734.98 800,2729.98 800,2719.98 805,2714.98 824.14,2714.98 830,2709.12 830,2700.84 824.14,2694.98 805,2694.98 800,2689.98 800,2658 808,2650 1020,2650 1030,2640 1030,2465 1045,2450 1058.12,2450 1072.96,2435.16 v4(1074.36,2435.16)
  Bottom Layer w5: CN7.4@782.52,3233.06 770,3220.54 C57.1@770,3130 795,3130 v1(800,3125) ; v4(1074.36,2435.16) U11.G6@1084.21,2425.31
NETC57_2: C57.2 R78.1 | length 50
  Bottom Layer w5: R78.1@770,3040 C57.2@770,3090
NETC58_1: C58.1 U11.B7 | length 1069.3
  Top Layer w5: v4(995.64,2415.48) 995.64,2430 1005.64,2440 1050,2440 1070,2420 1140,2420 1150,2430 1150,2680 1265,2795 1385,2795 1475,2885 v1(1475,3060)
  Bottom Layer w5: U11.B7@985.79,2405.63 v4(995.64,2415.48) ; C58.1@1440,3060 v1(1475,3060)
NETC58_2: C58.2 CN6.4 | length 120.3
  Bottom Layer w5: C58.2@1440,3120 1457.52,3137.52 CN6.4@1457.52,3233.06
NETC59_1: C59.1 CN7.6 U11.H6 | length 1184.2
  Top Layer w5: v1(1069,3040) 1070,3039 1070,2884 1075,2879 1120,2879 1125,2874 1125,2864 1120,2859 1080.86,2859 1075,2853.14 1075,2844.86 1080.86,2839 1114.14,2839 1120,2833.14 1120,2824.86 1114.14,2819 1080.86,2819 1075,2813.14 1075,2804.86 1080.86,2799 1114.14,2799 1120,2793.14 1120,2784.86 1114.14,2779 1083,2779 1075,2771 1075,2733 1083,2725 1120,2725 1125,2720 1125,2578 1117,2570 1053.2,2570 1043.2,2560 1043.2,2499 1042.97,2498.77 1042.97,2489.23 1043.19,2489.01 1043.19,2469.77 1052.96,2460 1109,2460 v1(1129.49,2439.51)
  Bottom Layer w5: v1(1069,3040) C59.1@1095,3040 1097.48,3037.52 CN7.6@1097.48,2941.73 ; U11.H6@1103.9,2425.31 1115.31,2425.31 v1(1129.49,2439.51)
NETC59_2: C59.2 R77.1 | length 45
  Bottom Layer w10: C59.2@1095,3080 R77.1@1140,3080
NETC60_1: C60.1 C61.2 CN1.27 CN1.29 L3.2 | length 404
  Top Layer w10: CN1.29@3499.83,3276.53 3499.83,3230.83 3489,3220 v1(3489,3214) 3505,3214 3519.52,3228.52 CN1.27@3519.52,3276.53
  Bottom Layer w20: L3.2@3467.51,3246.92 C60.1@3527.51,3246.92 ; v1(3489,3214) 3510,3214 3527.51,3231.51 C60.1@3527.51,3246.92 ; C61.2@3630,3190 3588.08,3246.92 C60.1@3527.51,3246.92
NETC60_2: C60.2 C61.1 CN1.21 CN1.23 L4.2 | length 428.1
  Top Layer w10: v1(3539,3340) 3542,3340 3558.89,3323.11 CN1.23@3558.89,3276.53 ; v1(3572,3339) 3578.57,3332.43 CN1.21@3578.57,3276.53
  Bottom Layer w20: v1(3539,3340) 3527.51,3328.51 C60.2@3527.51,3306.92 3534.43,3300 C61.1@3630,3300 ; v1(3572,3339) 3573,3338 3592,3338 C61.1@3630,3300 ; L4.2@3700,3295 3695,3300 C61.1@3630,3300
NETC62_1: C62.1 U11.D7 | length 1097.1
  Top Layer w5: v4(1015.3,2395.77) 1015.3,2394.7 1030,2380 1040,2380 1067.28,2407.28 1089.09,2407.28 1089.19,2407.38 1147.38,2407.38 1165,2425 1165,2675 1275,2785 v1(1725,2785)
  Bottom Layer w5: v4(1015.3,2395.77) U11.D7@1025.16,2405.63 ; v1(1725,2785) 1770,2785 C62.1@1775,2780
NETC62_2: C62.2 CN6.6 | length 102.8
  Bottom Layer w5: CN6.6@1772.48,2941.73 1775,2939.21 C62.2@1775,2840
NETC63_2: C63.2 U11.F1 | length 138
  Bottom Layer w5: U11.F1@1064.53,2523.74 1105,2564.21 C63.2@1105,2645
NETC66_1: C66.1 R84.1 U10.1 | length 185.3
  Bottom Layer w20: U10.1@4070,2739.92 4070,2730 4095,2705 C66.1@4170,2705 R84.1@4170,2770
NETC72_2: C72.2 U13.E11 | length 149.4
  Bottom Layer w15: v3(2339,2221) U13.E11@2355.51,2204.49
  Bottom Layer w20: C72.2@2110,2417 2183,2417 2200,2400 v1(2229,2400)
NETC74_1: C74.1 U11.G7 | length 163.1
  L4_SIG w3.5: v4(1093.96,2395.88) 1120,2395.88
  L4_SIG w4: 1120,2395.88 1145.88,2395.88 v1(1190,2440)
  Bottom Layer w3.5: U11.G7@1084.21,2405.63 v4(1093.96,2395.88)
  Bottom Layer w5: v1(1190,2440) C74.1@1225,2440
NETC77_2: C77.2 R97.1 X1.1 | length 133.4
  Bottom Layer w8: R97.1@2975,2375 C77.2@3020,2375 3079.72,2375 X1.1@3100,2395.28
NETC78_1: C78.1 U11.H7 | length 127.6
  Bottom Layer w5: U11.H7@1103.9,2405.63 1209.37,2405.63 C78.1@1225,2390
NETC82_1: C82.1 U11.H8 | length 144.3
  Bottom Layer w5: U11.H8@1103.9,2385.94 1169.06,2385.94 C82.1@1225,2330
NETC82_2: C82.2 U11.G8 | length 273.4
  L4_SIG w4: v4(1093.96,2376.19) 1093.96,2348.32 1126.87,2315.41 1184.59,2315.41 v1(1210,2290)
  Bottom Layer w3.5: U11.G8@1084.21,2385.94 v4(1093.96,2376.19)
  Bottom Layer w5: v1(1210,2290) 1245,2290 C82.2@1285,2330
NETC84_2: C84.2 R99.1 X1.2 | length 137.5
  Bottom Layer w8: R99.1@2975,2325 2980,2330 C84.2@3020,2330 3074.72,2330 X1.2@3100,2304.72
NETC87_1: C87.1 R101.2 R102.1 | length 90
  Bottom Layer w10: C87.1@665,2255 R102.1@710,2255 R101.2@755,2255
NETC87_2: C87.2 CN8.4 | length 133.4
  Bottom Layer w10: CN8.4@572.41,2390 665,2297.41 C87.2@665,2295
NETC90_1: C90.1 U11.E6 | length 258.4
  L4_SIG w4: v4(1054.59,2415.56) 1054.59,2369.13 1133.72,2290 v1(1175,2290)
  Bottom Layer w3.5: U11.E6@1044.84,2425.31 v4(1054.59,2415.56)
  Bottom Layer w5: C90.1@1175,2245 v1(1175,2290)
NETC93_1: C93.1 U11.D9 | length 125.5
  Bottom Layer w5: C93.1@1015,2245 1015,2300 1025.16,2310.16 U11.D9@1025.16,2366.26
NETC95_2: C95.2 U11.C9 | length 176.6
  Bottom Layer w5: C95.2@915,2245 915,2270 955,2310 985.47,2310 1005.47,2330 U11.C9@1005.47,2366.26
NETC119_1: C119.1 R114.1 R115.2 U16.4 | length 151.7
  Bottom Layer w10: R115.2@715,1580 R114.1@765,1580 C119.1@765,1625 770.43,1630.43 U16.4@819.41,1630.43
NETC119_2: C119.2 R117.1 | length 390.2
  Top Layer w5: v1(765,1700) 845,1700 930,1615 v1(930,1495)
  Bottom Layer w5: C119.2@765,1665 v1(765,1700) ; v1(930,1495) R117.1@930,1530
NETC120_1: C120.1 CN12.4 R111.2 | length 165.4
  Bottom Layer w10: CN12.4@572.41,1720 627.41,1665 C120.1@670,1665 R111.2@715,1665
NETC120_2: C120.2 R116.1 | length 45
  Bottom Layer w10: R116.1@670,1580 C120.2@670,1625
NETC148_1: C148.1 L7.1 R132.1 R142.2 U21.1 | length 1144.2
  L4_SIG w20: v1(2374,355) 2384,345 2825,345 2870,300 2918,300 2943,325 2985,325 v1(3011,351)
  Bottom Layer w20: v1(2374,355) 2374,502 2392,520 C148.1@2430,520 ; R132.1@2430,590 C148.1@2430,520 ; U21.1@2492.6,522.24 2490.36,520 C148.1@2430,520 ; R142.2@2970,390 2972,390 v1(3011,351) 3050,312 L7.1@3050,305
NETC153_2: C153.2 C154.2 C156.2 C157.2 CN15.5 CN15.6 CN15.7 CN15.8 CN15.9 CN15.10 L8.2 | length 709.5
  Bottom Layer w20: 2920,140.98 C156.2@2920,160 ; 2920,179.02 C156.2@2920,160 ; 2920,265.98 C153.2@2920,285 ; 2920,304.02 C153.2@2920,285 ; 2930,205.98 L8.2@2930,230 ; 2930,254.02 L8.2@2930,230 ; 2931.96,50.4 CN15.9@2967.48,50.4 2967.48,95.92 ; 2939.02,160 C156.2@2920,160 ; 2939.02,285 C153.2@2920,285 ; 2955.52,230 L8.2@2930,230 ; 3012.28,175.6 CN15.6@3041.3,175.6 3041.3,136.08 ; 3182.05,128.28 CN15.5@3182.05,162.8 3182.05,197.32 ; 3220.44,136.08 CN15.7@3220.44,175.6 ; 3220.44,215.12 CN15.7@3220.44,175.6 ; 3220.98,245 C154.2@3240,245 ; 3240,225.98 C154.2@3240,245 ; 3249.46,175.6 CN15.7@3220.44,175.6 ; 3259.02,245 C154.2@3240,245 ; 3294.26,95.92 CN15.8@3294.26,50.4 3329.78,50.4 ; 3360.98,55 C157.2@3380,55 ; 3380,35.98 C157.2@3380,55 ; 3380,74.02 C157.2@3380,55
NETC200_1: C200.1 R85.1 U10.2 | length 137
  Bottom Layer w20: R85.1@3950,2800 C200.1@3950,2735 4015.08,2735 U10.2@4020,2739.92
NETCN1_8: CN1.8 SB1.1 | length 113.6
  Top Layer w5: SB1.1@3689.67,2948.01 3689.67,2973.3 3716.37,3000 CN1.8@3716.37,3050.55
NETCN1_10: CN1.10 SB2.1 | length 145
  Top Layer w5: SB2.1@3620,2950 3660,2990 3681.68,2990 3696.68,3005 CN1.10@3696.68,3050.55
NETCN1_14: CN1.14 SB3.1 | length 188.1
  Top Layer w5: SB3.1@3549.67,2948.01 3549.67,2969.67 3560,2980 3630,2980 3657.31,3007.31 CN1.14@3657.31,3050.55
NETCN1_16: CN1.16 SB4.1 | length 238.3
  Top Layer w5: SB4.1@3479.67,2948.01 3479.67,2969.67 3505,2995 3625,2995 3637.63,3007.63 CN1.16@3637.63,3050.55
NETCN1_39: CN1.39 R7.2 | length 125.6
  Top Layer w5: v1(3380,3340) 3381.41,3340 3401.41,3320 CN1.39@3401.41,3276.53
  Bottom Layer w5: R7.2@3350,3300 3350,3310 v1(3380,3340)
NETCN2_1: CN2.1 R50.2 SB5.2 | length 310.7
  Top Layer w5: CN2.1@815,960 870,905 R50.2@1040,905 1044.17,909.17 SB5.2@1044.17,966.19
NETCN2_7: CN2.7 SB6.2 SB8.2 | length 323.5
  Top Layer w5: CN2.7@815,660 873.81,601.19 SB6.2@1044.17,601.19 SB8.2@1044.17,531.19
NETCN2_8: CN2.8 R57.1 | length 143.6
  Top Layer w5: CN2.8@915,660 960,705 R57.1@1040,705
NETCN5_10: CN5.10 R73.2 | length 126.8
  Bottom Layer w5: CN5.10@2856.93,3272.79 2856.93,3228.07 R73.2@2915,3170
NETCN9_8: CN9.8 R98.1 | length 189.3
  Bottom Layer w5: CN9.8@1405.8,2427.7 1478.5,2355 R98.1@1565,2355
NETCN10_1: CN10.1 T4.16 | length 310.8
  Bottom Layer w5.1: T4.16@4317.52,1675 4359,1675 4396,1712 4428,1712 4489,1773 4489,1824.78 4503.67,1839.45 CN10.1@4529.88,1839.45
NETCN10_2: CN10.2 T4.14 | length 313.2
  Bottom Layer w5.1: T4.14@4317.52,1775 4350,1775 4398,1727 4421.78,1727 4474,1779.22 4474,1831 4497,1854 4497,1871.97 CN10.2@4486.58,1879.61
NETCN10_3: CN10.3 T4.11 | length 243.5
  Bottom Layer w5.1: T4.11@4317.52,1925 4355,1925 4390,1960 4440,1960 4480.24,1919.76 CN10.3@4529.88,1919.76
NETCN10_4: CN10.4 CN10.5 D4.4 R42.2 | length 1038.5
  Top Layer w5: D4.4@4023.74,1316.57 4064.43,1316.57 v1(4084,1297) ; R42.2@4385,1755 4385,1761 4409,1785 v1(4409,1799) 4450,1840 4450,1920.56 CN10.4@4486.58,1959.92 4529.52,2000.08 CN10.5@4529.88,2000.08
  L4_SIG w4: v1(4084,1297) 4096,1309 4144,1309 4400,1565 4400,1790 v1(4409,1799)
NETCN10_6: CN10.6 T4.9 | length 244.3
  Bottom Layer w5.1: T4.9@4317.52,2025 4355,2025 4385,1995 4385,1980 4390,1975 4451.12,1975 4489.36,2013.24 CN10.6@4486.58,2040.24
NETCN10_7: CN10.7 CN10.8 D4.3 R26.2 | length 1051.2
  Top Layer w5: D4.3@4023.74,1513.43 4063.43,1513.43 v1(4080,1530) ; v1(4343.61,2065.18) 4378.79,2030 R26.2@4380,2030 4470.55,2120.55 CN10.8@4486.58,2120.55 4492.5,2120.55 CN10.7@4529.88,2080.39
  L4_SIG w4: v1(4080,1530) 4095,1545 4245,1545 4300,1600 4300,2021.57 v1(4343.61,2065.18)
NETCN11_1: CN11.1 R103.1 | length 120.3
  Bottom Layer w20: CN11.1@3305.8,2267.7 3308.5,2265 R103.1@3425,2265
NETCN14_5: CN14.5 SB13.2 SB14.2 | length 3464.8
  L4_SIG w4: v1(1669,2379) 1669,2164 1745,2088 1745,845 v1(1732,832)
  Bottom Layer w5: SB13.2@1600.83,2491.19 SB14.2@1600.83,2421.19 1643.02,2379 v1(1669,2379) ; v1(1732,832) 1735,835 2040,835 2075,800 2140,800 2175,765 2555,765 2575,745 2655,745 2675,765 2707,765 2732,740 2929,740 3156.7,967.7 CN14.5@3305.8,967.7
NETCN14_6: CN14.6 SB11.2 SB12.2 | length 3658.5
  L4_SIG w4: v1(1670,2406) 1697,2379 1697,2303 1731,2269 1731,2118 1757,2092 1757,831 v1(1732,806)
  Bottom Layer w5: SB11.2@1600.83,2636.19 SB12.2@1600.83,2566.19 1643.81,2566.19 1655,2555 1655,2421 v1(1670,2406) ; v1(1732,806) 1746,820 2020,820 2060,780 2130,780 2160,750 2550,750 2577,723 2941,723 3143,925 3250,925 3305.8,869.2 CN14.6@3305.8,867.7
NETCN15_4: CN15.4 D12.A2 U20.23 | length 621.1
  Top Layer w5: v1(3040,499) 3061,520 3180,520 3250,450 3250,365 v1(3240,355)
  Bottom Layer w5: v1(3040,499) 3060.79,519.79 U20.23@3060.79,534.72 ; CN15.4@3156.46,162.8 3156.46,200.46 3192.87,236.87 D12.A2@3192.87,257.13 3198.13,257.13 3211,270 3211,326 v1(3240,355)
NETCN16_4: CN16.4 R149.2 | length 82.7
  Bottom Layer w5: R149.2@3685,235 3709.41,210.59 CN16.4@3709.41,162.4
NETD1_1: D1.1 R10.2 R12.2 T1.1 | length 254.1
  Top Layer w20: T1.1@3729.02,2629.45 3790.16,2629.45 D1.1@3810.71,2650 3810.71,2730.71 R10.2@3820,2740 R12.2@3890,2740
NETD1_2: D1.2 R2.2 | length 939.9
  Top Layer w15: D1.2@3899.29,2650 v1(3899.29,2685) ; v1(3923,3270) R2.2@3964.49,3270
  L4_SIG w15: v1(3899.29,2685) 3899.29,2779.29 3955,2835 3955,2945 4015,3005 4080,3005 4115,3040 4115,3200 4075,3240 3953,3240 v1(3923,3270)
NETD3_1: D3.1 R24.1 | length 78.8
  Bottom Layer w20: D3.1@3555.71,2555 3565,2545.71 R24.1@3565,2480
NETD5_2: D5.2 D6.2 D7.2 D8.2 SB7.1 | length 387.9
  Top Layer w15: SB7.1@4240.33,696.99 4240.33,694.67 4265,670 D8.2@4310.71,670 D7.2@4310.71,775 D6.2@4310.71,875 D5.2@4310.71,975
NETD9_3: D9.3 R46.2 T4.15 | length 739.5
  Top Layer w5: v1(4370,1715) 4375,1715 4385,1705 R46.2@4385,1670
  L4_SIG w4: v1(4084,1337) 4099,1322 4135,1322 4385,1572 4385,1700 v1(4370,1715)
  Bottom Layer w5: D9.3@4023.74,1316.57 4063.57,1316.57 v1(4084,1337) ; T4.15@4317.52,1725 4360,1725 v1(4370,1715)
NETD9_4: D9.4 R33.2 T4.10 | length 847.4
  Top Layer w5: v1(4366,1984) 4385,1965 R33.2@4385,1940
  L4_SIG w4: v1(4080,1500) 4110,1530 4245,1530 4310,1595 4310,1928 v1(4366,1984)
  Bottom Layer w5: D9.4@4023.74,1513.43 4066.57,1513.43 v1(4080,1500) ; T4.10@4317.52,1975 4357,1975 v1(4366,1984)
NETD11_2: D11.2 R141.2 | length 88.8
  Bottom Layer w20: D11.2@3480.71,395 3490,404.29 R141.2@3490,480
NETJP2_1: JP2.1 U11.B1 | length 1051.4
  Bottom Layer w5: JP2.1@605,3365 668,3302 668,2957 805,2820 805,2615 850.21,2569.79 939.74,2569.79 U11.B1@985.79,2523.74
NETJP2_2: JP2.2 U11.A2 | length 954.5
  Bottom Layer w5: JP2.2@605,3265 645,3225 645,2940 780,2805 780,2615 845.96,2549.04 921.12,2549.04 U11.A2@966.1,2504.06
NETJP3_1: JP3.1 U11.C3 | length 1098.3
  L4_SIG w4: JP3.1@480,3365 545,3300 545,3240 715,3070 715,2855 925.35,2644.65 925.35,2580 987.54,2517.81 987.54,2502.3 v4(995.72,2494.12)
  Bottom Layer w3.5: v4(995.72,2494.12) U11.C3@1005.47,2484.37
NETJP3_2: JP3.2 U11.B3 | length 990.1
  L4_SIG w4: JP3.2@480,3265 695,3050 695,2845 880,2660 880,2591.23 965,2506.23 965,2505.16 v4(976.04,2494.12)
  Bottom Layer w3.5: v4(976.04,2494.12) U11.B3@985.79,2484.37
NETLD1_1: LD1.1 R62.2 | length 85
  Top Layer w5: LD1.1@1290,245 R62.2@1290,330
NETLD2_1: LD2.1 R63.2 | length 85
  Top Layer w5: LD2.1@1390,245 R63.2@1390,330
NETLD3_1: LD3.1 R64.1 | length 95
  Top Layer w5: LD3.1@1490,245 R64.1@1490,340
NETLD4_1: LD4.1 R65.1 | length 85
  Top Layer w5: LD4.1@1590,245 R65.1@1590,330
NETLD4_2: LD4.2 R129.1 R130.2 U21.3 | length 1325.8
  Top Layer w5: LD4.2@1590,185 v1(1635,185)
  Bottom Layer w5: v1(1635,185) 2090,640 2305,640 2335,670 2497,670 2516,651 2516,614 R130.2@2540,590 R129.1@2585,590 2585,554 2567.4,536.4 U21.3@2567.4,522.24
NETLD5_1: LD5.1 R66.1 | length 95
  Top Layer w5: LD5.1@1685,245 R66.1@1685,340
NETLD5_2: LD5.2 T5.3 | length 754.4
  Top Layer w5: LD5.2@1685,185 v1(1723,185)
  Bottom Layer w5: v1(1723,185) 2128,590 T5.3@2271.69,590
NETLD6_1: LD6.1 R58.2 | length 100
  Top Layer w5: LD6.1@1780,245 R58.2@1780,345
NETLD7_1: LD7.1 R59.1 | length 100
  Top Layer w5: LD7.1@1885,245 R59.1@1885,345
NETLD7_2: LD7.2 R150.1 U22.8 | length 2633.8
  Top Layer w20: LD7.2@1885,185 v2(1920,185)
  L4_SIG w20: v2(1920,185) 2025,80 2860,80 2907.49,127.49 2987.51,127.49 3010,105 3225,105 3385,265 3665,265 3685,245 v2(4275,245)
  Bottom Layer w20: R150.1@4235,230 4260,230 v2(4275,245) 4288.3,258.3 U22.8@4288.3,290
NETLD8_2: LD8.2 R60.2 | length 71.1
  Top Layer w5: R60.2@3420,345 3420.47,344.53 LD8.2@3420.47,274.06
NETLD8_3: LD8.3 R61.2 | length 71.1
  Top Layer w5: LD8.3@3479.53,274.06 3479.53,344.53 R61.2@3480,345
NETR1_2: R1.2 U1.7 | length 181.2
  Top Layer w10: U1.7@4356.14,3183.98 4383.98,3183.98 4396.14,3196.14 4396.14,3256.14 R1.2@4450,3310
NETR2_1: R2.1 R10.1 U1.10 | length 676.8
  Top Layer w10: R2.1@4025.51,3270 4070,3225.51 v1(4070,3205) 4070,3200 4086.02,3183.98 U1.10@4123.86,3183.98
  Top Layer w20: R10.1@3820,2810 v1(3820,2855)
  L4_SIG w15: v1(3820,2855) 3820,2960 3865,3005 3900,3005 3995,3100 3995,3145 4055,3205 v1(4070,3205)
NETR3_2: R3.2 U1.5 | length 112.6
  Top Layer w10: U1.5@4356.14,3132.8 4387.8,3132.8 R3.2@4445,3190
NETR4_2: R4.2 R9.2 T1.3 | length 372.3
  Top Layer w20: T1.3@3729.02,2810.55 3760,2841.53 R9.2@3760,2905 3855,3000 3905,3000 3955,3050 R4.2@3965,3050
NETR5_2: R5.2 U1.14 U10.4 | length 261.7
  Top Layer w10: R5.2@4025,3000 4053,3028 4053,3058 v1(4070,3075) 4076.61,3081.61 U1.14@4123.86,3081.61
  Bottom Layer w10: U10.4@4070,2990.08 4070,3010 4045,3035 4045,3060 4060,3075 v1(4070,3075)
NETR6_1: R6.1 U1.1 | length 121
  Top Layer w10: U1.1@4356.14,3030.43 4384.57,3030.43 R6.1@4450,2965
NETR20_2: R20.2 R21.2 U13.E5 | length 391
  Top Layer w5: v3(2559.34,2219.34) 2575,2235 2575,2295 2595,2315 2595,2367 2590,2372 2590,2492.25 2589.5,2492.75 2589.5,2507.25 2590,2507.75 2590,2525 R20.2@2595,2530 R21.2@2635,2530
  Bottom Layer w4: U13.E5@2544.49,2204.49 v3(2559.34,2219.34)
NETR27_2: R27.2 U3.5 | length 55.5
  Top Layer w5: R27.2@3620,1980 3625.47,1974.53 U3.5@3625.47,1926.77
NETR30_1: R30.1 R32.1 U3.7 | length 161.3
  Top Layer w5: R30.1@3480,1995 R32.1@3480,1955 3535.79,1899.21 U3.7@3578.23,1899.21
NETR31_1: R31.1 U3.24 | length 146.9
  Top Layer w5: U3.24@3731.77,1899.21 3745.21,1899.21 3767,1921 3767,1947 3800,1980 R31.1@3830,1980
NETR34_1: R34.1 R36.1 U3.8 | length 140.1
  Top Layer w5: R34.1@3480,1915 R36.1@3480,1875 3495,1875 3499.53,1879.53 U3.8@3578.23,1879.53
NETR38_1: R38.1 T4.7 | length 173.7
  Top Layer w20: v1(3930,1975) 3955,1975 3970,1960 R38.1@3970,1885
  Bottom Layer w20: v1(3930,1975) T4.7@3982.48,1975
NETR38_2: R38.2 T4.2 | length 170.8
  Top Layer w20: v1(3930,1725) 3950,1725 3970,1745 R38.2@3970,1815
  Bottom Layer w20: v1(3930,1725) T4.2@3982.48,1725
NETR43_1: R43.1 R44.1 U3.11 | length 182.4
  Top Layer w5: R44.1@3480,1695 R43.1@3480,1750 3499,1750 3569.47,1820.47 U3.11@3578.23,1820.47
NETR51_1: R51.1 U6.2 | length 131.4
  Top Layer w5: U6.2@2667.47,809.28 2655.72,809.28 2630,835 2630,870 2650,890 R51.1@2670,890
NETR64_2: R64.2 SB15.1 | length 2014.7
  Top Layer w5: R64.2@1490,380 1490,492 v1(1524,526)
  L4_SIG w4: v1(1524,526) 1705,707 1705,860 1730,885 1730,2080 1650,2160 1620,2160 v1(1605,2175)
  Bottom Layer w5: v1(1605,2175) 1608.01,2178.01 SB15.1@1608.01,2224.67
NETR71_1: R71.1 U9.2 | length 95
  Top Layer w5: R71.1@2585,255 2630,255 2660.33,224.67 U9.2@2667.46,224.67
NETR87_1: R87.1 U11.D4 U11.D5 | length 237
  L4_SIG w4: v1(1010,2605) 980,2575 980,2544.54 1000,2524.54 1000,2513.42 1006.72,2506.7 1006.72,2485 1004.45,2482.73 1004.45,2465.71 v4(1015.45,2454.71)
  Bottom Layer w3.5: U11.D5@1025.16,2445 v4(1015.45,2454.71) 1015.45,2454.98 U11.D4@1025.16,2464.69
  Bottom Layer w5: v1(1010,2605) R87.1@1010,2635
NETR88_2: R88.2 U11.H1 | length 141.5
  Bottom Layer w5: U11.H1@1103.9,2523.74 1145.16,2565 1200,2565 R88.2@1220,2585
NETR94_1: R94.1 U11.G2 | length 150.7
  L4_SIG w3.5: v4(1093.96,2513.81) 1120,2539.85
  L4_SIG w4: 1120,2539.85 1120.15,2540 v1(1190,2540)
  Bottom Layer w3.5: U11.G2@1084.21,2504.06 v4(1093.96,2513.81)
  Bottom Layer w5: v1(1190,2540) R94.1@1220,2540
NETR95_2: R95.2 U11.F3 | length 165.9
  L4_SIG w4: v4(1074.28,2474.62) 1085.66,2486 1186,2486 v1(1190,2490)
  Bottom Layer w3.5: U11.F3@1064.53,2484.37 v4(1074.28,2474.62)
  Bottom Layer w5: v1(1190,2490) R95.2@1220,2490
NETR100_2: R100.2 R101.1 | length 45
  Bottom Layer w10: R101.1@755,2295 R100.2@800,2295
NETR107_2: R107.2 X2.1 | length 64.1
  Bottom Layer w5: R107.2@3100,2075 3106.42,2081.42 X2.1@3106.42,2136.46
NETR108_2: R108.2 U13.L5 | length 304.4
  L4_SIG w4: v3(2560,2032) 2577,2015 2645,2015 2670,2040 2755.74,2040 2775.12,2059.38 2775.12,2059.31 v1(2775.21,2059.31)
  Bottom Layer w5: U13.L5@2544.49,2015.51 2560,2031.02 v3(2560,2032) ; v1(2775.21,2059.31) 2789.5,2045 R108.2@2810,2045
NETR112_1: R112.1 R117.2 U15.2 | length 232.9
  Bottom Layer w5: R112.1@930,1620 R117.2@930,1570 955,1545 955,1509 969,1495 990,1495 1005,1510 U15.2@1005,1559.57
NETR115_1: R115.1 R116.2 U16.2 | length 304.1
  Bottom Layer w10: R116.2@670,1540 R115.1@715,1540 715,1490 730,1475 825,1475 845,1495 U16.2@845,1559.57
NETR121_2: R121.2 U19.3 | length 132.8
  Bottom Layer w5: R121.2@3615,895 3650,860 3680,860 3691.1,848.9 U19.3@3691.1,811.26
NETR122_2: R122.2 U19.2 | length 155
  Bottom Layer w5: R122.2@3570,895 3594.5,870.5 3620.5,870.5 3641,850 3665,850 3671.42,843.58 U19.2@3671.42,811.26
NETR126_1: R126.1 U20.32 | length 65.2
  Bottom Layer w5: R126.1@2950,700 2951.1,698.9 U20.32@3014.72,698.9
NETR127_2: R127.2 U19.44 | length 58.9
  Bottom Layer w5: R127.2@3530,670 3530.47,669.53 U19.44@3588.74,669.53
NETR131_1: R131.1 R132.2 T5.1 | length 132.8
  Bottom Layer w5: T5.1@2358.31,627.4 2427.4,627.4 R132.2@2430,630 R131.1@2490,630
NETR134_2: R134.2 X4.1 | length 69.2
  Bottom Layer w5: R134.2@2710,620 2723.54,633.54 X4.1@2773.58,633.54
NETR136_2: R136.2 U20.26 | length 75.4
  Bottom Layer w8: R136.2@2950,575 2960,565 2980,565 2995.79,580.79 U20.26@3014.72,580.79
NETR139_1: R139.1 U20.24 | length 106.6
  Bottom Layer w5: R139.1@2950,530 2961,519 3033,519 3041.1,527.1 U20.24@3041.1,534.72
NETR140_1: R140.1 U22.5 | length 103.2
  Bottom Layer w20: R140.1@4210,500 4270,440 U22.5@4288.3,440
NETR142_1: R142.1 U20.22 | length 153.9
  Bottom Layer w5: R142.1@2970,460 2990,480 3047,480 3080.47,513.47 U20.22@3080.47,534.72
NETR145_1: R145.1 R146.2 R147.1 T3.1 | length 183
  Top Layer w5: T3.1@3797.4,348.31 3797.4,312.6 v1(3800,310)
  Bottom Layer w5: v1(3800,310) 3800,280 R147.1@3805,275 3845,235 R146.2@3850,235 R145.1@3895,235
NETR148_2: R148.2 T3.2 | length 80.6
  Top Layer w5: v1(3715,305) 3722.6,312.6 T3.2@3722.6,348.31
  Bottom Layer w5: v1(3715,305) 3715,285 R148.2@3725,275
NETU20_17: U20.17 U21.4 | length 879.3
  L4_SIG w4: v1(2570,385) 2826,385 2850,361 2974,361 2992,379 3053.23,379 3057.23,375 3178,375 3215,412 v1(3228,412)
  Bottom Layer w5: U21.4@2567.4,427.76 2567.4,387.6 v1(2570,385) ; U20.17@3178.9,534.72 3178.9,526.1 3228,477 v1(3228,412)
NRST: CN11.3 R106.1 SB10.1 SB20.2 U3.15 U13.J1 U20.27 | length 4315.3
  Top Layer w5: U3.15@3645.16,1773.23 3645.16,1699.84 v1(3665,1680) ; 3945,275 3919,301 3919,524 3974,579 v1(3986,579)
  L4_SIG w4: v1(2975.63,590) 2975,589.37 2980.63,589.37 3060,510 3330,510 3425,605 3820,605 3845,580 3985,580 v1(3986,579) 3986,920 3961,945 3915,945 3847.5,1012.5 3847.5,1072.5 3665,1255 v1(3665,1680)
  Bottom Layer w5: U13.J1@2670.47,2078.5 2696.97,2105 2790,2105 R106.1@2810,2085 2830,2105 2969,2105 3025,2049 3287.1,2049 CN11.3@3305.8,2067.7 3390.3,2067.7 3469,1989 3469,1775 3483,1761 3483,1713 3507,1689 3656,1689 v1(3665,1680) ; v1(2975.63,590) 2986.1,600.47 U20.27@3014.72,600.47 ; v1(3986,579) 4034,579 4040.83,585.83 SB20.2@4040.83,626.19
OSC_24M: R136.1 X4.3 | length 64.2
  Bottom Layer w8: X4.3@2846.42,576.46 2847.88,575 R136.1@2910,575
OSC_25M: R27.1 R104.1 X2.3 | length 850.9
  Top Layer w5: R27.1@3620,2020 v1(3620,2056)
  Bottom Layer w5: R104.1@2975,2205 2975,2225 2995,2245 3128.5,2245 3157.5,2216 3379,2216 3472,2123 3553,2123 v1(3620,2056)
  Bottom Layer w8: R104.1@2975,2205 2986.46,2193.54 X2.3@3033.58,2193.54
OSC_IN: C142.2 U19.5 X3.2 | length 203.5
  Bottom Layer w8: X3.2@3694.72,1000 3715,979.72 C142.2@3715,900 3730.47,884.53 U19.5@3730.47,811.26
OSC_OUT: C141.2 U19.6 X3.1 | length 203.3
  Bottom Layer w8: U19.6@3750.16,811.26 3750.16,890.16 C141.2@3760,900 3760,974.72 X3.1@3785.28,1000
OTG_HS_OverCurrent: R129.2 U13.D11 | length 4555.2
  Top Layer w5: v1(2281,2494) 2338.5,2494 2357.5,2475 2357.5,2244.98 2371,2231.48 v3(2371,2221)
  L4_SIG w4: v1(1211,965) 1282,1036 1282,2429 1321,2468 1603,2468 1706,2571 2204,2571 v1(2281,2494)
  Bottom Layer w4: U13.D11@2355.51,2235.98 2370.49,2221 v3(2371,2221)
  Bottom Layer w5: v1(1211,965) 1235,941 1235,840 1410,665 2290,665 2321,696 2534,696 2565,665 2565,650 R129.2@2585,630
PB3: R92.2 R93.2 U13.A10 | length 258.6
  Bottom Layer w5: R93.2@2355,2530 R92.2@2405,2530 2405,2510 2390,2495 2390,2434 2385,2429 2385,2332.48 U13.A10@2387.01,2330.47
PC14: R97.2 U13.E1 | length 375.6
  Bottom Layer w8: U13.E1@2670.47,2204.49 2699.49,2204.49 2745,2250 2745,2300 2758,2313 2758,2332 2776,2350 2910,2350 R97.2@2935,2375
PC15: R99.2 U13.F1 | length 356.8
  Bottom Layer w8: U13.F1@2670.47,2172.99 2692.99,2172.99 2760,2240 2760,2290 2770,2300 2910,2300 R99.2@2935,2325
PH0: R104.2 U13.G1 | length 290.8
  Bottom Layer w8: U13.G1@2670.47,2141.5 2701.5,2141.5 2765,2205 R104.2@2935,2205
PH1: TP21.1 U13.H1 | length 304.8
  Bottom Layer w5: U13.H1@2670.47,2110 2685.47,2125 2730,2125 2758,2153 2890,2153 2908,2135 TP21.1@2950,2135
POE1: C3.1 C4.2 C9.1 C12.1 C20.1 C24.1 C70.1 C75.1 C81.1 R9.1 R12.1 R74.1 T2.1 T100.4 U1.9 U10.3 | length 1168.6
  Top Layer w12: v1(4100,3250) 4095,3245 4095,3220 4105.43,3209.57 U1.9@4123.86,3209.57
  Top Layer w20: v1(3405,2520) C81.1@3455,2520 v1(3455,2565) ; v1(3522,2586) 3522,2561 3540,2543 3557,2560 v1(3557,2587) ; v1(3616,2587) 3616,2552 3625,2543 3645,2563 v1(3645,2587) ; R9.1@3876,2905 v2(3876,2962) ; R12.1@3890,2800 v2(3890,2843) ; v2(3920,3105) C9.1@3965,3105 ; C3.1@3978,3360 v2(3978,3412) ; v2(4020,2902) 4020,2920 4025,2925 C12.1@4025,2945 ; C4.2@4360,3325 v2(4360,3370)
  Bottom Layer w15: C24.1@3630,2620 v1(3670,2620)
  Bottom Layer w20: v1(3520,2280) 3542,2258 3542,2225 3542,2193 v1(3570,2165) ; v1(3676,2586) 3708.89,2553.11 T100.4@3732.05,2553.11 3750.11,2553.11 3778.64,2581.64 T2.1@3859.21,2581.64 ; v2(3920,3105) 3925.51,3099.49 R74.1@3965,3099.49 ; v2(4020,2902) U10.3@4020,2990.08
POE2: R24.2 T2.2 T100.3 | length 230.2
  Bottom Layer w20: R24.2@3635,2480 3640.63,2474.37 T100.3@3732.05,2474.37 3850.37,2474.37 T2.2@3859.21,2483.21
POE3: R23.2 T1.2 T1.4 T2.3 T100.2 | length 994.2
  Top Layer w20: 3437.46,2720 T1.4@3480.98,2720 ; 3480.98,2646.98 T1.4@3480.98,2720 ; 3480.98,2793.02 T1.4@3480.98,2720 ; 3524.5,2720 T1.4@3480.98,2720 ; T1.2@3729.02,2720 3750,2720 v1(3780,2690)
  Top Layer w40: 3670,2720 T1.2@3729.02,2720
  L4_SIG w20: v1(3780,2690) 3780,2446.6 v1(3791.19,2435.41)
  Bottom Layer w20: v1(3791.19,2435.41) v1(3791.19,2435.41) 3689.51,2435.37 3665,2410.86 3665,2395 R23.2@3655,2385 3700,2385 3710.63,2395.63 T100.2@3732.05,2395.63 3848.37,2395.63 T2.3@3859.21,2384.79
POE4: C20.2 C22.2 L5.1 T2.4 T100.1 | length 701.8
  Top Layer w20: 3546.98,2234.92 L5.1@3615,2234.92 ; 3615,2196.9 L5.1@3615,2234.92 ; 3683.02,2234.92 L5.1@3615,2234.92
  Bottom Layer w20: 3626.98,2225 C20.2@3658,2225 ; 3635,2280.98 C22.2@3635,2305 ; 3635,2329.02 C22.2@3635,2305 ; C20.2@3658,2186.98 C20.2@3658,2225 ; C20.2@3658,2263.02 C20.2@3658,2225 ; 3660.52,2305 C22.2@3635,2305 ; 3689.02,2225 C20.2@3658,2225 ; 3691.03,2316.89 T100.1@3732.05,2316.89 ; 3732.05,2284.87 T100.1@3732.05,2316.89 ; 3773.07,2316.89 T100.1@3732.05,2316.89 ; 3791.19,2286.36 T2.4@3859.21,2286.36 ; 3859.21,2253.34 T2.4@3859.21,2286.36 ; 3859.21,2319.38 T2.4@3859.21,2286.36 ; 3927.23,2286.36 T2.4@3859.21,2286.36
  other v1: 3700,2175 3640.63,2185 3675,2185
POE5: D2.1 R22.1 T2.5 T2.6 T100.7 T100.8 | length 788.5
  Bottom Layer w20: 4471.98,2394.45 D2.1@4525,2394.45 ; 4525,2351.43 D2.1@4525,2394.45 ; 4525,2437.47 D2.1@4525,2394.45 ; 4578.02,2394.45 D2.1@4525,2394.45 ; 4611.98,2425 R22.1@4640,2425 ; 4640,2391.98 R22.1@4640,2425 ; 4640,2458.02 R22.1@4640,2425
  Bottom Layer w40: T100.8@4187.95,2316.89 4214.47,2316.89 4245,2286.36 T2.5@4340.79,2286.36 4431.36,2286.36 ; T100.7@4187.95,2395.63 4249.37,2395.63 4260.21,2384.79 T2.6@4340.79,2384.79 4429.79,2384.79
POE7: B2.2 B2.3 C1.1 C2.1 C3.2 C13.1 C14.1 C15.1 C16.1 C18.1 C23.1 C25.1 C27.1 C28.1 C29.1 C30.1 C31.1 C33.1 C35.1 C36.2 C38.2 C41.2 C42.1 C43.1 C44.2 C45.2 C46.1 C47.1 C48.1 C49.1 C50.1 C51.1 C52.1 C53.1 C54.1 C55.2 C56.2 C63.1 C64.2 C65.2 C66.2 C67.1 C68.2 C69.2 C71.2 C72.1 C73.1 C74.2 C76.1 C77.1 C78.2 C79.1 C80.1 C83.1 C84.1 C85.1 C86.1 C88.1 C90.2 C91.2 C92.2 C93.2 C94.2 C95.1 C96.1 C97.1 C98.1 C99.1 C100.1 C101.2 C102.1 C103.1 C104.1 C105.1 C106.1 C107.1 C108.1 C109.1 C110.1 C111.1 C112.1 C113.1 C114.1 C115.1 C116.2 C117.1 C118.1 C123.1 C124.1 C125.1 C126.1 C127.1 C128.1 C129.1 C130.1 C131.1 C132.1 C133.1 C134.1 C135.1 C136.1 C137.1 C138.1 C139.1 C140.2 C141.1 C142.1 C143.1 C144.2 C145.1 C146.1 C147.2 C148.2 C149.1 C150.2 C151.1 C152.1 C153.1 C154.1 C155.1 C156.1 C157.1 CN1.1 CN1.6 CN1.7 CN1.12 CN1.13 CN1.18 CN1.19 CN1.61 CN1.62 CN1.63 CN1.64 CN4.3 CN5.6 CN5.9 CN6.2 CN6.3 CN7.2 CN7.3 CN8.1 CN8.2 CN8.3 CN9.7 CN11.6 CN11.7 CN12.1 CN12.2 CN12.3 CN16.5 CN16.6 CN16.7 CN16.8 CN16.9 CN16.10 CN16.11 D12.B1 D12.B2 H1.1 H2.1 H3.1 H4.1 H5.1 H6.1 H7.1 H8.1 JP1.2 L3.1 L8.1 LD1.2 LD2.2 LD3.2 LD6.2 LD8.1 R14.1 R15.1 R18.1 R21.1 R28.1 R29.1 R31.2 R40.1 R70.1 R77.2 R78.2 R96.2 R102.2 R105.1 R108.1 R111.1 R113.1 R119.1 R121.1 R122.1 R124.1 R127.1 R128.1 R131.2 R133.1 R135.1 R139.2 R140.2 R146.1 R149.1 SB1.2 SB2.2 SB3.2 SB4.2 SB5.1 SB8.1 SB16.1 T2.7 T2.8 T5.2 T100.5 T100.6 U2.5 U3.25 U4.2 U5.2 U5.5 U5.6 U5.7 U5.8 U6.5 U6.6 U6.7 U6.8 U7.2 U7.7 U8.2 U8.5 U8.6 U8.7 U8.8 U9.5 U9.6 U9.7 U9.8 U11.A1 U11.A3 U11.A4 U11.A5 U11.C1 U11.D6 U11.E2 U11.E7 U11.E8 U11.F7 U11.G5 U11.H9 U12.4 U13.F2 U13.F6 U13.F7 U13.F8 U13.F9 U13.F10 U13.G6 U13.G10 U13.G12 U13.H6 U13.H10 U13.J6 U13.J10 U13.K6 U13.K7 U13.K8 U13.K9 U13.K10 U13.L6 U13.M1 U13.N1 U14.1 U15.3 U16.3 U17.A3 U17.B3 U17.B8 U17.C1 U17.D1 U17.E9 U17.F1 U17.L3 U17.L9 U17.M1 U17.N1 U17.P3 U17.P8 U17.R3 U18.1 U19.8 U19.20 U19.23 U19.35 U19.47 U20.33 U21.2 U22.4 U23.4 U24.A1 U24.A2 X2.2 X4.2 | length 13547.8
  Top Layer w10: CN1.19@3598.26,3276.53 3598.26,3321.26 3602.44,3325.44 3602.44,3325.68 3608.29,3331.53 3608.53,3331.53 3620,3343 v2(3630,3343) 3639.62,3343 3657.31,3325.31 CN1.13@3657.31,3276.53 ; CN1.18@3617.94,3050.55 v2(3617.94,3120) ; v2(3670,3120) 3677,3113 CN1.12@3677,3050.55 ; v2(3705,3340) 3716.37,3328.63 CN1.7@3716.37,3276.53 ; v2(3730,3120) 3736.05,3113.95 CN1.6@3736.05,3050.55
  Top Layer w11: CN1.1@3775.42,3276.53 v2(3775.42,3340)
  Top Layer w15: v2(2004,793.55) U5.6@2040.43,793.55 ; v2(2015.06,208.94) U8.6@2040.43,208.94 ; C25.1@2399,2126 2399,2098 v3(2404,2093) ; v3(2404,2064) 2405,2063 C27.1@2405,2039 ; v2(2590,793.55) U6.6@2625.04,793.55 ; v2(2590.06,208.94) U9.6@2625.04,208.94
  Top Layer w20: v1(1006,305) C54.1@1040,305 ; R70.1@1080,215 v1(1118,215) ; SB8.1@1083.01,530.33 v1(1124.67,530.33) ; SB5.1@1083.01,965.33 v1(1118.01,965.33) ; LD1.2@1290,185 v1(1330,185) ; LD2.2@1390,185 v1(1435,185) ; LD3.2@1490,185 v1(1530,185) ; U23.4@1730,2588.98 1730,2600 1755,2625 v2(1760,2625) ; LD6.2@1780,185 v1(1820,185) ; v2(1940,1985) C31.1@1982,1985 ; U8.2@2082.85,224.67 2082.86,245.86 2093,256 v2(2107,256) ; U5.2@2082.86,809.28 2082.86,832.86 2090,840 v2(2107,840) ; v2(2165,2370) 2190,2345 C23.1@2190,2303 ; v2(2265,218) C55.2@2265,255 ; C44.2@2265,836 2304,836 v2(2310,830) ; R18.1@2510,2570 2519.76,2579.76 v2(2519.76,2598) ; R21.1@2635,2570 v2(2635,2602) ; v2(2807.57,175) C56.2@2807.57,215 ; C45.2@2810,800 v2(2845,800) ; v2(2916,385) 2955,385 C52.1@2975,405 2955,425 v2(2916,425) ; v2(3101,3163.54) CN1.64@3172.47,3163.54 ; v1(3187.51,2840) C2.1@3187.51,2881.92 ; v2(3250,3163.54) CN1.63@3364.99,3163.54 ; v1(3366.92,2881.92) C1.1@3407.51,2881.92 ; v2(3410,1790) R40.1@3440,1790 ; v2(3410,1835) C33.1@3440,1835 ; LD8.1@3420.47,155.94 3420.47,206.47 3429,215 v2(3430,215) ; v1(3478.81,2873.81) SB4.2@3478.81,2909.17 ; C28.1@3530,2030 v2(3530,2080) ; v1(3548.81,2870) SB3.2@3548.81,2909.17 ; v2(3565,2055) 3565,2035 C29.1@3580,2020 ; v2(3575,1514.9) C38.2@3575,1565 v2(3630,1565) ; CN1.62@3614.99,3163.54 v1(3731,3163.54) ; v1(3618.81,2870) SB2.2@3618.81,2909.17 ; R28.1@3660,2020 v2(3660,2050) ; v1(3675,2875) 3688.81,2888.81 SB1.2@3688.81,2909.17 ; R29.1@3700,2020 v2(3700,2050) ; v2(3745,2050) C30.1@3750,2020 ; C35.1@3800,1635 3824.3,1610.7 v2(3824.3,1610.4) ; CN1.61@3807.51,3163.54 v2(3880,3163.54) ; v2(3823,1550) 3855,1550 C36.2@3870,1565 3855,1580 v2(3823,1580) ; C3.2@3862,3360 v2(3862,3417) ; v2(3870,2055) 3890,2035 R31.2@3890,1980 ; C53.1@3945,395 v2(3945,430) ; v2(3960,835) 3970,845 C41.2@3995,845 ; C42.1@4045,855 4045,820 v1(4060,805) ; U2.5@4052.24,2857.4 v2(4106,2857.4) ; B2.3@4057.83,212.5 v2(4105,212.5) ; v1(4080,500) C51.1@4120,500 ; v1(4080,620) C48.1@4120,620 ; v1(4080,650) C47.1@4110,680 ; v1(4098,570) C49.1@4130,570 ; v2(4125,2620) R14.1@4125,2655 ; U4.2@4140,812.76 4140,775 v1(4145,770) ; v1(4180,660) C46.1@4180,700 ; R15.1@4180,2655 v2(4215,2655) ; 4201.98,2915 C13.1@4235,2915 ; 4235,2945.52 C13.1@4235,2915 ; C43.1@4245,845 4245,815 v2(4255,805) ; v1(4265,2705) C18.1@4305,2705 v1(4305,2660) ; 4268.02,2915 C13.1@4235,2915 ; 4276.98,2915 C14.1@4310,2915 ; 4310,2945.52 C14.1@4310,2915 ; v2(4340,235) 4362.5,212.5 B2.2@4412.17,212.5 ; 4343.02,2915 C14.1@4310,2915 ; 4351.98,2915 C15.1@4385,2915 ; U7.2@4356.52,530 4410,530 C50.1@4415,535 v1(4415,570) ; 4385,2945.52 C15.1@4385,2915 ; 4418.02,2915 C15.1@4385,2915 ; 4430.98,2905 C16.1@4455,2905 ; 4455,2930.52 C16.1@4455,2905 ; 4479.02,2905 C16.1@4455,2905
  Bottom Layer w5: 3100,375 3109.25,384.25 ; U24.A1@3141.87,384.25 U24.A2@3157.62,384.25
  Bottom Layer w9: v2(930,2475) 939.37,2484.37 U11.A3@966.1,2484.37 ; U11.C1@1005.47,2523.74 v2(1005.47,2549.6) ; U11.D6@1025.16,2425.31 v4(1034.91,2415.56) ; U11.E8@1044.84,2385.94 v4(1035,2395.79) U11.E7@1044.84,2405.63 ; U11.E2@1044.84,2504.06 1049.88,2509.1 v4(1054.7,2513.9) ; U11.F7@1064.53,2405.63 v4(1074.38,2395.78) ; U11.G5@1084.21,2445 v4(1093.96,2435.25) ; U11.H9@1103.9,2366.26 1103.9,2366.1 v2(1125,2345) ; D12.B1@3177.13,272.87 3177.13,314.46 v2(3185.67,323) 3192.87,315.8 D12.B2@3192.87,272.87
  Bottom Layer w10: v2(930,2475) 940.31,2464.69 U11.A4@966.1,2464.69 ; v2(940,2430) 955,2445 U11.A5@966.1,2445 ; v4(952.26,2537.36) 952.26,2536.48 965,2523.74 U11.A1@966.1,2523.74 ; 3109.25,384.25 U24.A1@3141.87,384.25 ; U19.47@3588.74,728.58 v2(3640,728.58) ; U19.35@3671.42,468.74 v2(3671.42,520) ; v2(3789.53,760) U19.8@3789.53,811.26 ; v2(3885,551.42) U19.23@3931.26,551.42 ; v2(3885,610.47) U19.20@3931.26,610.47
  Bottom Layer w15: v2(819.41,1509.41) U16.3@819.41,1559.57 ; v2(979.41,1515) U15.3@979.41,1559.57 ; v2(2150,1687) C115.1@2150,1715 ; v2(2170,1465) C125.1@2210,1465 ; C114.1@2205,1715 C113.1@2255,1715 v2(2255,1684) ; v3(2224,1263.51) U17.A3@2239.53,1247.99 ; v3(2255,1107) 2255,1106.53 U17.B8@2271.02,1090.51 ; v3(2255,1264) U17.B3@2271.02,1247.99 ; v2(2257,910) C138.1@2290,910 ; v3(2287,1326) 2287,1326.5 U17.C1@2302.52,1310.98 ; C112.1@2305,1715 C111.1@2360,1715 v2(2360,1685) ; v3(2319,1325.99) U17.D1@2334.02,1310.98 ; U13.G12@2324.02,2141.5 2340,2157.48 v3(2340,2159.84) ; C137.1@2335,910 v2(2372,910) ; C124.1@2345,1465 v2(2377,1465) ; U17.E9@2365.51,1059.02 2365.51,1042.49 v3(2374,1034) ; v3(2371,2095) 2387.01,2078.99 U13.J10@2387.01,2078.5 ; v3(2372.16,2187.84) U13.F10@2387.01,2172.99 ; v3(2381,1328) 2380,1328 U17.F1@2397.01,1310.98 ; U13.K10@2387.01,2047.01 v3(2404,2064) 2418.5,2049.5 U13.K9@2418.5,2047.01 ; U13.H10@2387.01,2110 v3(2404,2093) ; U13.G10@2387.01,2141.5 v3(2401.86,2156.35) ; v3(2403.65,2187.84) U13.F9@2418.5,2172.99 ; C136.1@2405,910 v2(2436,910) ; C110.1@2405,1715 C109.1@2450,1715 v2(2450,1686) ; U13.K8@2450,2047.01 v3(2464.85,2032.16) ; U13.F8@2450,2172.99 v3(2465,2157.99) ; U13.K7@2481.5,2047.01 v3(2496.35,2032.16) ; U13.F7@2481.5,2172.99 v3(2496.35,2187.84) ; v3(2498,2156.49) U13.G6@2512.99,2141.5 ; v3(2498.14,2095.15) U13.H6@2512.99,2110 ; v2(2510,910) C135.1@2540,910 ; U13.L6@2512.99,2015.51 v3(2527.84,2000.66) ; U13.K6@2512.99,2047.01 2497.84,2062.16 v3(2497.84,2063.65) 2512.69,2078.5 U13.J6@2512.99,2078.5 ; U13.F6@2512.99,2172.99 v3(2527.84,2187.84) ; v2(2524,1459) 2530,1465 C123.1@2555,1465 ; v3(2539,1263) 2539,1263.48 U17.L3@2554.49,1247.99 ; C108.1@2545,1715 v1(2574,1715) ; U17.L9@2554.49,1059.02 2554.49,1059.49 v3(2570,1075) ; v2(2571,910) C134.1@2600,910 ; U17.M1@2585.98,1310.98 2600,1325 v3(2600,1327) ; C107.1@2600,1715 v1(2629,1715) C106.1@2655,1715 ; U17.N1@2617.48,1310.98 2619.02,1310.98 v3(2634,1296) ; v3(2633,1107) 2640.53,1099.47 2640.53,1098.96 U17.P8@2648.98,1090.51 ; v2(2637,909) 2638,910 C133.1@2670,910 ; U13.F2@2638.98,2172.99 2654,2188.01 v3(2655,2188.01) ; U17.P3@2648.98,1247.99 2648.98,1242.02 v3(2671,1220) ; U13.N1@2670.47,1952.52 2672.48,1952.52 2686.99,1938.01 v3(2686.99,1937.67) ; U13.M1@2670.47,1984.02 v3(2692,1984.02) ; U17.R3@2680.47,1247.99 2693.48,1261 v3(2700,1261) ; C105.1@2695,1715 v1(2725,1715) C104.1@2755,1715 ; v2(2840,1064) C131.1@2840,1095 ; C128.1@2840,1145 2840,1181 v2(2845,1186) ; C126.1@2840,1250 2840,1282 2845,1287 v2(2845,1291) ; C99.1@2850,2130 v2(2881,2130) ; C97.1@2850,2180 2884,2180 v2(2885,2179) ; C88.1@2850,2230 2880,2230 v2(2884,2226) ; C86.1@2850,2280 2879,2280 v2(2883,2276) ; C83.1@2850,2325 v2(2880,2325) ; C80.1@2850,2375 v2(2880,2375) ; C103.1@2905,1790 v2(2935,1790) ; C102.1@2905,1850 2940,1850 2944,1854 v2(2944,1855) ; v2(2930,1666) 2930,1710 C116.2@2940,1720 2965,1745 v2(2965,1789) ; v2(2969,1978) 2969,1974 2940,1945 C101.2@2940,1930 v2(2985,1930) ; v2(3660,209) 3661,209 3683.82,186.18 CN16.5@3683.82,162.4
  Bottom Layer w20: CN12.2@474.65,1462.72 v2(642.72,1462.72) ; CN12.3@474.65,1987.28 v2(645.03,1987.32) v2(645.03,1987.32) ; CN8.2@474.65,2132.72 v2(650,2132.72) ; CN8.3@474.65,2657.28 v2(655,2657.28) ; R102.2@710,2295 v2(710,2330) ; R111.1@715,1625 718,1625 v2(741,1602) ; v2(740,2400) C79.1@785,2400 ; v2(740,2455) C73.1@785,2455 ; v2(770,2505) C71.2@805,2505 ; v2(770,2965) R78.2@770,3000 ; C118.1@825,1695 v2(825,1730) ; v2(845,2605) C67.1@845,2645 ; v2(915,2145) C95.1@915,2185 ; v2(920,2690) 930,2680 C65.2@960,2680 ; v2(965,2145) C94.2@965,2185 ; C117.1@990,1695 v2(990,1727) ; v2(1013.1,3418.1) CN7.2@1097.48,3418.1 ; v2(1015,2145) C93.2@1015,2185 ; v2(1021.07,3303.93) CN7.3@1097.48,3303.93 ; C64.2@1055,2680 v2(1055,2715) ; v2(1065,2145) C92.2@1065,2185 ; C63.1@1105,2705 v2(1105,2750) ; v2(1115,2155) C91.2@1115,2195 ; 1120,2030.98 C100.1@1120,2055 ; 1120,2079.02 C100.1@1120,2055 ; R77.2@1140,3040 v2(1187.7,3040) ; 1145.52,2055 C100.1@1120,2055 ; 1170.5,1980.55 U14.1@1214.02,1980.55 ; v2(1175,2145) C90.2@1175,2185 ; 1214.02,2008.57 U14.1@1214.02,1980.55 ; 1257.54,1980.55 U14.1@1214.02,1980.55 ; C78.2@1285,2390 v2(1326,2390) ; C74.2@1285,2440 v2(1325,2440) ; v2(1515,2310) C85.1@1565,2310 ; v2(1695,2185) C96.1@1730,2185 ; CN6.3@1772.48,3303.93 v2(1854.93,3303.93) ; CN6.2@1772.48,3418.1 v2(1852.9,3418.1) ; U12.4@1880,2588.54 1880,2595 1898,2613 v2(1910,2613) ; v2(2039,1135) 2054,1150 C127.1@2075,1150 ; v2(2070,2601) 2070,2556 2093,2533 C72.1@2110,2533 2110,2595 v2(2103,2602) ; v2(2075,1071) C130.1@2075,1105 ; v2(2312,552.6) T5.2@2358.31,552.6 ; v2(2430,412) C148.2@2430,460 ; v2(2459,590) R131.2@2490,590 ; U21.2@2530,522.24 v2(2530,562) ; CN5.6@2689.61,2871.21 v2(2689.61,2925) ; v2(2787,2591) 2821,2591 C69.2@2835,2605 2819,2621 v2(2787,2621) ; v2(2805,670) 2810,675 C144.2@2810,700 ; C147.2@2815,515 v2(2851,515) ; CN5.9@2821.5,2871.21 v2(2821.5,2978) ; X4.2@2846.42,633.54 v2(2877.88,665.04) ; R108.1@2850,2045 v2(2882,2045) ; C76.1@2850,2425 v2(2880.86,2425) ; v2(2855,125) 2880,150 C156.1@2880,160 ; L8.1@2870,230 2870,205 v2(2885,190) ; C153.1@2880,285 v2(2880,330) ; v2(2910,496) R139.2@2910,530 ; C145.1@2910,630 v2(2910,665) ; v2(2994,2136.46) X2.2@3033.58,2136.46 ; v2(2995,2585) 2960,2585 C68.2@2940,2605 2955,2620 v2(2995,2620) ; C84.1@3020,2290 v2(3049,2290) ; C77.1@3020,2415 v2(3048,2415) ; C150.2@3045,415 3045.36,414.64 v2(3045.36,360) ; v2(3080,355) 3100,375 C149.1@3100,415 ; C98.1@3170,2140 v2(3205,2140) ; R124.1@3180,830 v2(3180,867) ; C154.1@3240,285 v2(3240,325) ; R133.1@3305,600 v2(3340,600) ; R128.1@3305,660 v2(3340,660) ; 3420,35.98 C157.1@3420,55 ; 3420,74.02 C157.1@3420,55 ; 3439.02,55 C157.1@3420,55 ; v2(3455,575) R135.1@3490,575 ; v2(3460,670) R127.1@3490,670 ; v2(3460,750) C143.1@3490,750 ; L3.1@3467.51,3306.92 3467.51,3342.51 v2(3468,3343) ; 3565.68,57.09 CN16.7@3597.2,57.09 3597.2,102.61 ; R122.1@3570,935 v2(3570,970) ; 3599.05,163.39 CN16.9@3636.57,163.39 3636.57,125.87 ; v2(3615,360) C151.1@3650,360 ; R121.1@3615,935 v2(3615,970) ; v2(3645,925) 3645,920 3665,900 C142.1@3675,900 ; 3657.91,57.09 CN16.11@3695.63,57.09 ; R149.1@3685,275 v2(3685,325) ; 3695.63,109.37 CN16.11@3695.63,57.09 ; 3774.37,109.37 CN16.10@3774.37,57.09 ; v2(3775,870) 3780,870 3800,890 C141.1@3800,900 ; 3812.09,57.09 CN16.10@3774.37,57.09 ; v2(3830,310) 3830,295 R146.1@3850,275 ; 3833.43,125.87 CN16.8@3833.43,163.39 3870.95,163.39 ; 3872.8,102.61 CN16.6@3872.8,57.09 3904.32,57.09 ; v2(3905,870) C140.2@3905,900 ; C132.1@3905,1000 v2(3930,975) ; v2(3970,214) 3979,205 C155.1@4005,205 ; R119.1@4000,940 v2(4030,940) ; SB16.1@4003.01,999.67 v2(4003.01,1045) ; v1(4045,475) 4045,455 4060,440 U22.4@4081.7,440 ; v1(4045,505) C146.1@4045,540 ; v1(4144,465) 4144,474 R140.2@4170,500 ; C66.2@4230,2705 4230,2690 v1(4250,2670) ; 4282.53,865.98 U18.1@4310.55,865.98 ; 4305,716.98 C129.1@4305,750 ; 4305,783.02 C129.1@4305,750 ; 4310.55,822.46 U18.1@4310.55,865.98 ; 4310.55,909.5 U18.1@4310.55,865.98 ; 4335.52,750 C129.1@4305,750 ; 4338.57,865.98 U18.1@4310.55,865.98 ; 4340.79,2516.23 T2.7@4340.79,2483.21 4408.81,2483.21 ; 4340.79,2548.62 T2.8@4340.79,2581.64 ; 4340.79,2614.66 T2.8@4340.79,2581.64 ; v2(4350,270) 4350,290 C152.1@4365,305 4380,290 v2(4380,270) ; 4366.98,900 C139.1@4400,900 ; 4400,869.48 C139.1@4400,900 ; 4408.81,2581.64 T2.8@4340.79,2581.64 ; v1(4426,2250) R105.1@4455,2250 ; 4433.02,900 C139.1@4400,900 ; 4456.98,875 JP1.2@4495,875 ; 4495,836.98 JP1.2@4495,875 ; 4495,913.02 JP1.2@4495,875 ; 4533.02,875 JP1.2@4495,875 ; v2(4575,1551.8) R113.1@4575,1590 ; R96.2@4785,2495 v2(4785,2556) ; CN16.11@3695.63,57.09 CN16.10@3774.37,57.09
  Bottom Layer w40: T100.6@4187.95,2474.37 4244.37,2474.37 4253.21,2483.21 T2.7@4340.79,2483.21 ; T100.5@4187.95,2553.11 4218.11,2553.11 4246.64,2581.64 T2.8@4340.79,2581.64
  other v1: 4276,492 4324,492 4299,527 4278,569 4325,569 3055,575 3110,575 3165,575 3055,630 3110,630 3165,630 3055,685 3110,685 3165,685 3614,1811 3655,1812 3695,1812 3614,1851 3695,1851 3655,1852 3614,1891 3655,1891 3695,1891 4425,2495 4425,2520 4425,2560 4425,2605
  other v2: 2694,160 2108,161 2178,208 2762,210 3159,231 2695,255 3193,470 2693,744 2110,745 2178,794 2762,794 4350,810 4380,810 2692,840 4350,840 4380,840 3791,1852 3797,1933 1160,2065 1190,2065 1125,2100 1160,2100 1190,2100 4180,2930 4180,2966 4230,2970 4280,2970 4340,2970 4380,2970
PWR_ENN: R144.1 U19.28 U22.3 | length 418.9
  L4_SIG w4: v1(3809.21,519.21) 3809.21,480.79 3840,450 3967,450 v1(3978,439)
  Bottom Layer w5: U19.28@3809.21,468.74 v1(3809.21,519.21) ; v1(3978,439) 3990,427 3990,400 R144.1@4005,385
  Bottom Layer w10: R144.1@4005,385 4010,390 U22.3@4081.7,390
PWR_EXT: R135.2 R138.1 R141.1 U19.39 | length 155.4
  Bottom Layer w10: R141.1@3530,480 R138.1@3530,530 R135.2@3530,575 3533.9,571.1 U19.39@3588.74,571.1
QSPI_CLK: U12.6 U13.M5 U23.6 | length 1996
  Top Layer w5: U23.6@1780,2281.9 1773,2274.9 1773,2227.85 1787.85,2213 1804,2213 v1(1825,2234) ; v1(2739,2325) 2739,2240 2756,2223 2756,2126 2872,2010 v1(2872,1974)
  L4_SIG w4: v1(1825,2234) 1846,2213 1859,2213 2077,2431 2281,2431 2305,2407 2305,2396 2313,2388 2468,2388 2476,2380 2569,2380 2597,2352 2708,2352 2735,2325 v1(2739,2325) ; v3(2559.34,1969.17) 2667.83,1969.17 2676,1961 2698,1961 2711,1948 2846,1948 v1(2872,1974)
  Bottom Layer w5: v1(1825,2234) 1825,2246 1830,2251 U12.6@1830,2281.46 ; U13.M5@2544.49,1984.02 v3(2559.34,1969.17)
QSPI_D0: U12.5 U13.F14 U23.5 | length 735.3
  Top Layer w5: U23.5@1730,2281.9 1730,2239 1772,2197 1817,2197 v1(1853,2233)
  Bottom Layer w5: U12.5@1880,2281.46 1880,2275 1853,2248 v1(1853,2233) 1853,2222 1948,2127 2133,2127 2164,2158 2246.03,2158 U13.F14@2261.02,2172.99
QSPI_D1: U12.2 U13.B14 U23.2 | length 839.5
  Top Layer w5: U23.2@1830,2588.98 v1(1830,2631)
  L4_SIG w4: v1(1830,2631) 1833,2631 1873,2591 1963,2591 2002,2630 v1(2080,2630)
  Bottom Layer w5: U12.2@1780,2588.54 1780,2600 1811,2631 v1(1830,2631) ; v1(2080,2630) 2136,2630 2175,2591 2175,2500 2247,2428 2247,2361 2245,2359 2245,2325 2261.02,2308.98 U13.B14@2261.02,2298.98
QSPI_D2: U12.3 U13.A3 U23.3 | length 1131.3
  Top Layer w5: U23.3@1780,2588.98 1780,2620 1811,2651 1840,2651 v1(1858,2633)
  L4_SIG w4: v1(1858,2633) 1888,2663 2174.27,2663 2347.27,2490 2445,2490 2478,2457 2554,2457 v1(2611,2400)
  Bottom Layer w5: U12.3@1830,2588.54 1830,2606 1857,2633 v1(1858,2633) ; U13.A3@2607.48,2330.47 2607.48,2387.48 2611,2391 v1(2611,2400)
QSPI_D3: U12.7 U13.M11 U23.7 | length 1116.2
  Top Layer w5: v1(1794,2234) 1794,2236 1828.46,2270.46 1830,2272 U23.7@1830,2281.9 ; v1(1815,1850) 1851,1886 2151,1886 2207,1942 2229.99,1942 2270.99,1983 2316,1983 2329.83,1969.17 v3(2340.66,1969.17)
  Bottom Layer w5: U12.7@1780,2281.46 1780,2248 v1(1794,2234) 1794,1871 v1(1815,1850) ; v3(2340.66,1969.17) U13.M11@2355.51,1984.02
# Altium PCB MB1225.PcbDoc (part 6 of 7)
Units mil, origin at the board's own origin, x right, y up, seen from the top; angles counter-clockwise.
Board outline 5000 x 3464.56 mil, 6 copper layers (Top Layer, L2_GND, L3_VCC, L4_SIG, L5_GND, Bottom Layer), stack 62.2 mil thick; 453 components, 378 nets, 1982 pads, 949 vias.

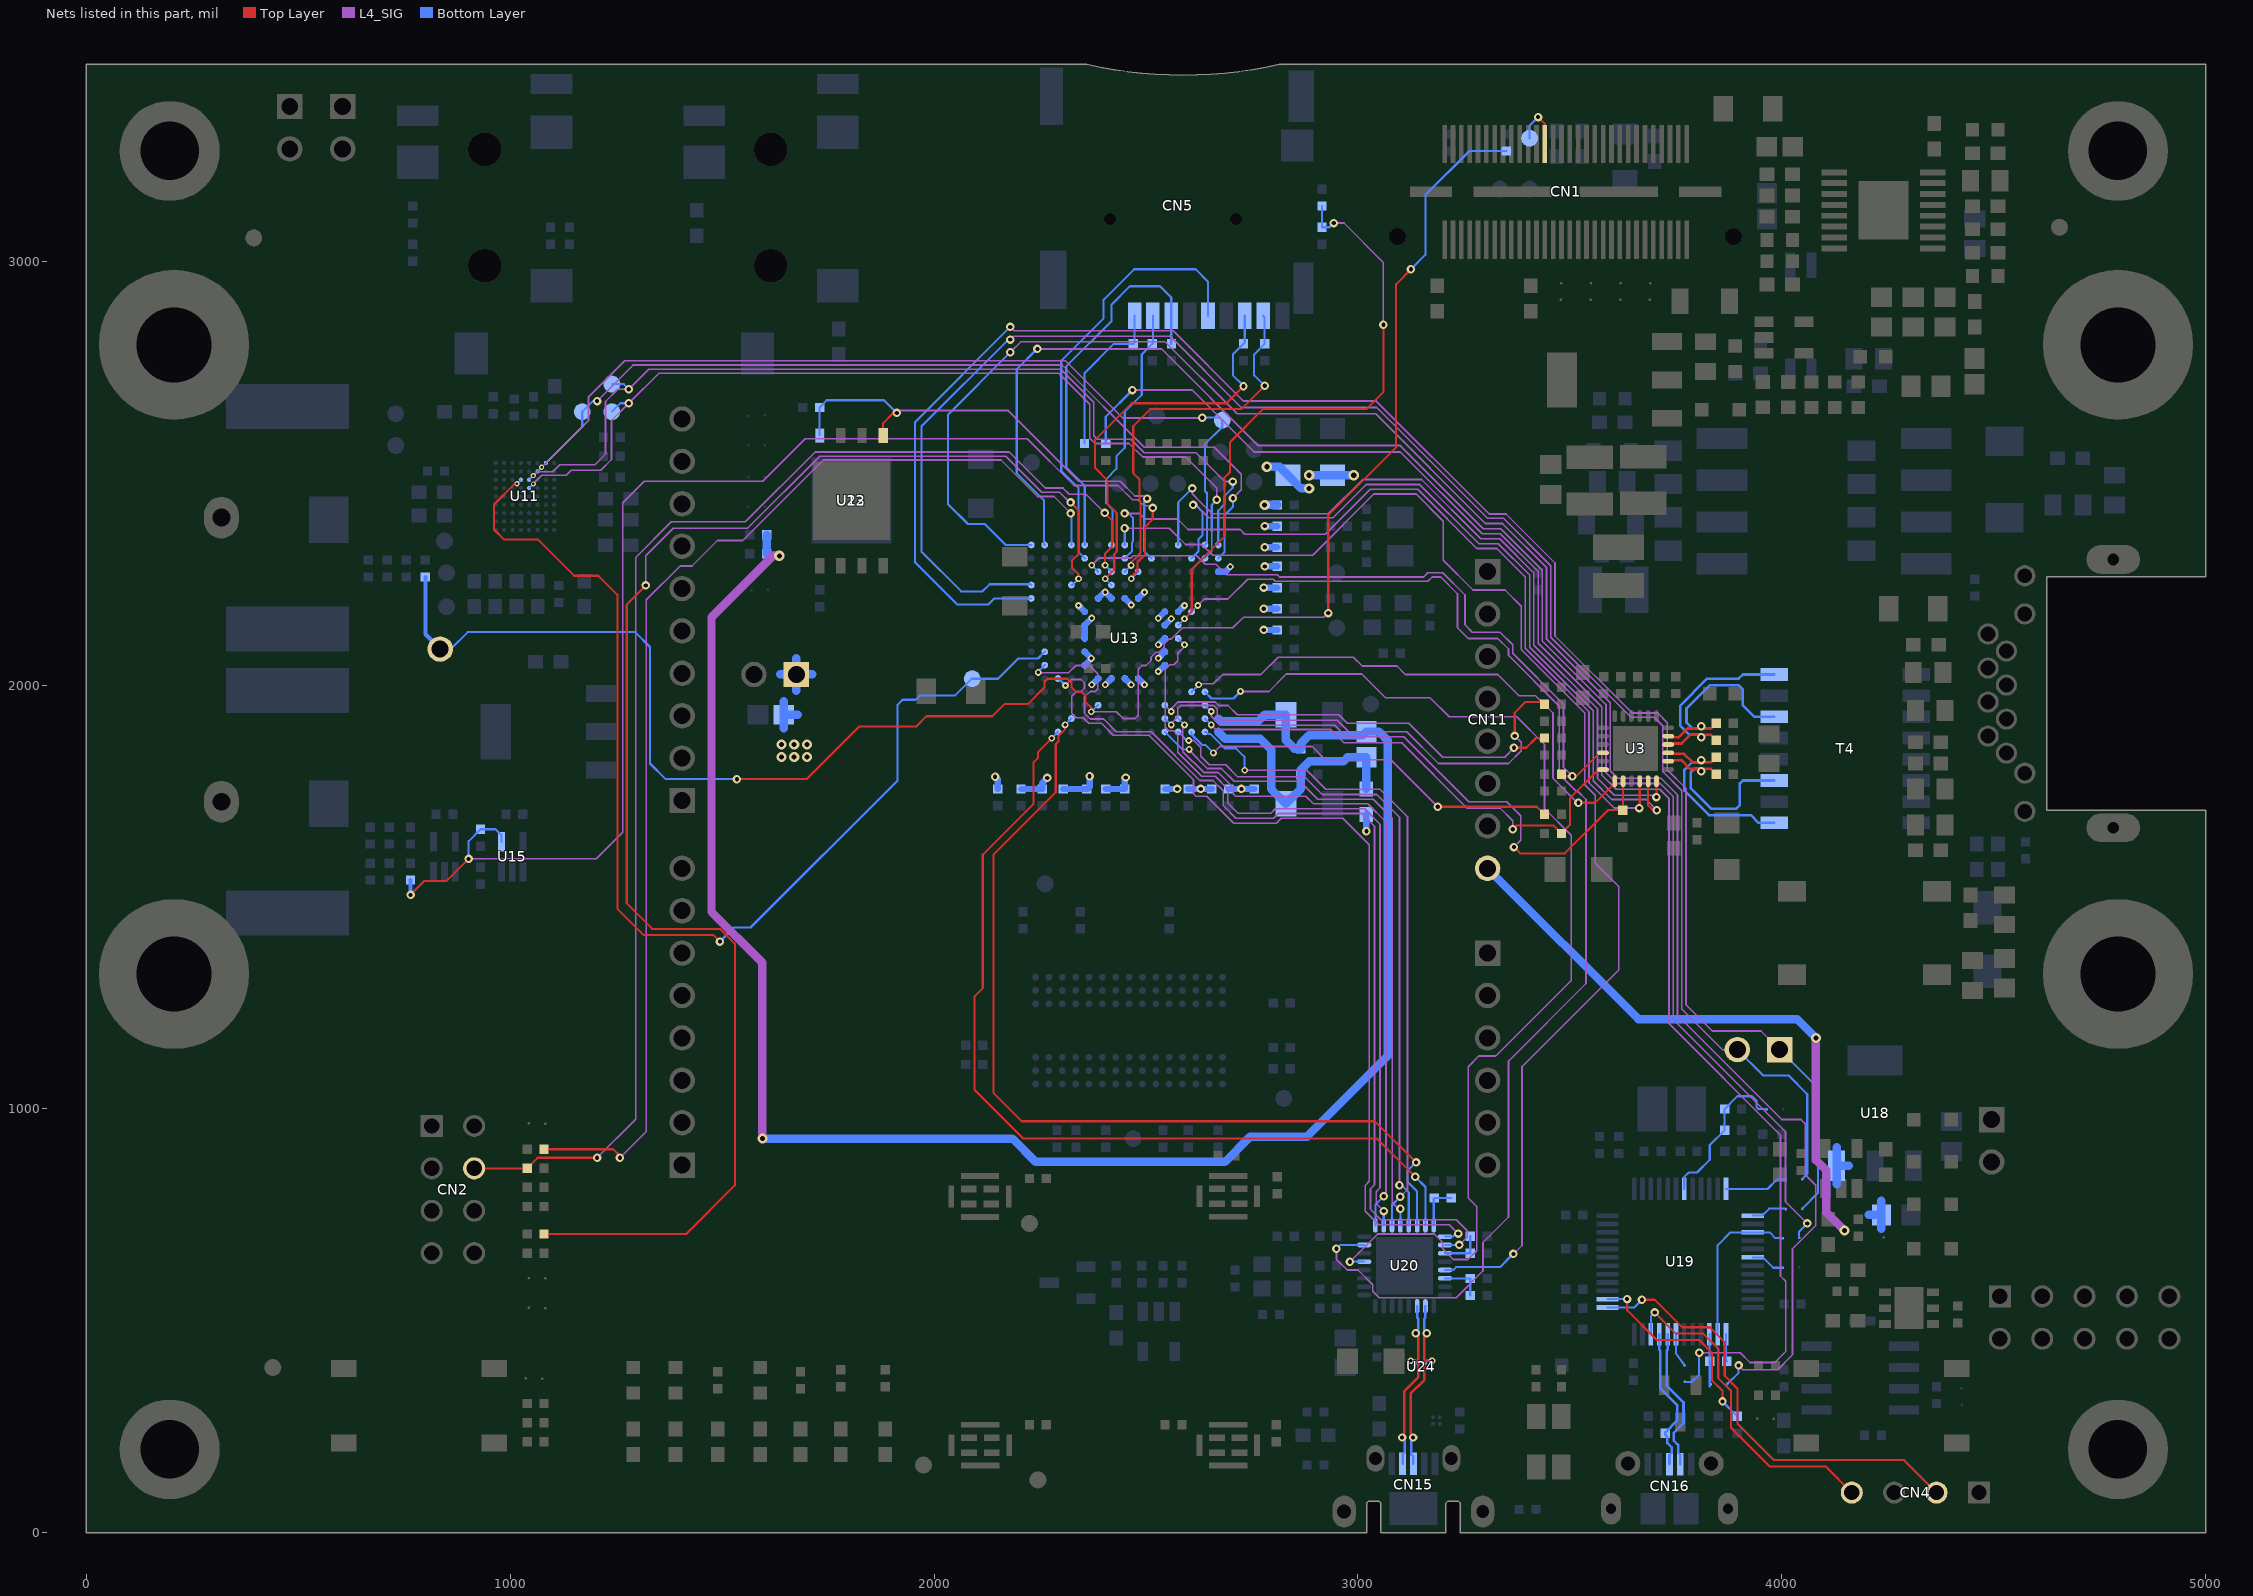
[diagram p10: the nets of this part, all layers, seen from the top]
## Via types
v1: diameter 20, hole 10, Top Layer to Bottom Layer, 354 vias
v2: diameter 24, hole 12, Top Layer to Bottom Layer, 347 vias
v3: diameter 16, hole 8, Top Layer to Bottom Layer, 221 vias
v4: diameter 12, hole 6, Top Layer to Bottom Layer, 27 vias

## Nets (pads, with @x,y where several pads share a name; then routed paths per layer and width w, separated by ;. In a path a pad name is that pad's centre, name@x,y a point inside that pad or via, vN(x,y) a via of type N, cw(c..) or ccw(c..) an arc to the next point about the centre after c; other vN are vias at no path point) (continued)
QSPI_NCS: R86.1 U12.1 U13.B6 U23.1 | length 1168.8
  Top Layer w5: U23.1@1880,2588.98 1880,2618 1904,2642 v1(1912,2642)
  L4_SIG w4: v1(1912,2642) 1918,2648 2174,2648 2341,2481 2439,2481 2474,2446 2496.5,2446 v1(2502.5,2440)
  Bottom Layer w5: U12.1@1730,2588.54 R86.1@1730,2655 1747,2672 1882,2672 v1(1912,2642) ; v1(2502.5,2440) 2496,2433.5 2496,2315.98 U13.B6@2512.99,2298.98
RD_N: R37.2 T4.8 U3.22 | length 493
  Top Layer w6.1: U3.22@3731.77,1859.84 3742.65,1859.84 3745,1862.19 3763.41,1862.19 3783.72,1882.5 3804.31,1882.5 v1(3809.81,1877) 3815.31,1882.5 3832.5,1882.5 R37.2@3845,1870
  Bottom Layer w6.1: v1(3809.81,1877) 3804.31,1882.5 3782.5,1882.5 3760,1905 3760,1951.22 3823.78,2015 3898,2015 3908,2025 T4.8@3982.48,2025
RD_P: R35.2 T4.6 U3.23 | length 492.5
  Top Layer w6.1: U3.23@3731.77,1879.53 3742.66,1879.53 3745,1877.19 3757.19,1877.19 3777.5,1897.5 3804.31,1897.5 v1(3809.81,1903) 3815.31,1897.5 3832.5,1897.5 R35.2@3845,1910
  Bottom Layer w6.1: v1(3809.81,1903) 3804.31,1897.5 3788.72,1897.5 3775,1911.22 3775,1945 3830,2000 3898,2000 3908,1990 3908,1952 3935,1925 T4.6@3982.48,1925
REFSEL0: R123.1 R124.2 U20.8 | length 105.2
  Bottom Layer w5: U20.8@3178.9,725.28 3178.9,788.9 R124.2@3180,790 R123.1@3220,790
REFSEL1: R125.1 R128.2 U20.11 | length 99.9
  Bottom Layer w5: U20.11@3205.28,659.53 3264.53,659.53 R128.2@3265,660 R125.1@3265,700
REFSEL2: R133.2 R137.1 U20.14 | length 99.9
  Bottom Layer w5: U20.14@3205.28,600.47 3264.53,600.47 R133.2@3265,600 R137.1@3265,560
RMII_CRS_DV: R44.2 U13.R3 | length 929
  Top Layer w5: v1(3188,1713) 3422,1713 R44.2@3440,1695
  L4_SIG w4: v3(2659,1840) 2674,1855 2892,1855 2923,1824 3077,1824 v1(3188,1713)
  Bottom Layer w5: U13.R3@2607.48,1889.53 2607.48,1883.52 2632,1859 2640,1859 v3(2659,1840)
RMII_MDC: U3.13 U13.M3 | length 1289
  Top Layer w5: v1(3520,1722.5) 3559.5,1722.5 3605.79,1768.79 U3.13@3605.79,1773.23
  L4_SIG w4: v3(2624,2001) 2626,2003 2659,2003 2681,2025 2771,2025 2812,2066 2989,2066 3010,2045 3092,2045 3112,2025 3330,2025 3380,1975 3419,1975 3460,1934 3460,1780 3517.5,1722.5 v1(3520,1722.5)
  Bottom Layer w5: U13.M3@2607.48,1984.02 2608.02,1984.02 2624,2000 v3(2624,2001)
RMII_MDIO: R47.1 U3.12 U13.P2 | length 1170
  Top Layer w5: v1(3365,1660) 3374,1669 3461,1669 R47.1@3480,1650 3500,1670 3500,1733 3567.79,1800.79 U3.12@3578.23,1800.79
  L4_SIG w4: v3(2653.83,1906.17) 2665,1895 2936,1895 2967,1864 3103,1864 3257,1710 3335,1710 3365,1680 v1(3365,1660)
  Bottom Layer w5: U13.P2@2638.98,1921.02 v3(2653.83,1906.17)
RMII_REF_CLK: R45.1 U3.14 U13.N2 | length 1314.2
  Top Layer w5: v1(3368,1618) 3383,1603 3488,1603 3590,1705 R45.1@3625,1705 3625.47,1705.47 U3.14@3625.47,1773.23
  L4_SIG w4: v3(2653.83,1937.67) 2653.83,1926.17 2675,1905 2945,1905 2972,1878 3108,1878 3261,1725 3351,1725 3384,1692 3384,1634 v1(3368,1618)
  Bottom Layer w5: U13.N2@2638.98,1952.52 v3(2653.83,1937.67)
RMII_RXD0: R36.2 U13.N5 | length 987.3
  Top Layer w5: v1(3367.97,1852.03) 3397.03,1852.03 3420,1875 R36.2@3440,1875
  L4_SIG w4: v3(2559.34,1937.67) 2559.34,1944.34 2575,1960 2662.62,1960 2670.95,1951.67 2693.33,1951.67 2715,1930 2955,1930 2975,1910 3120,1910 3200,1830 3345.94,1830 v1(3367.97,1852.03)
  Bottom Layer w4: U13.N5@2544.49,1952.52 v3(2559.34,1937.67)
RMII_RXD1: R32.2 U13.P5 | length 1135.7
  Top Layer w5: v1(3370,1880) 3370,1935 3395,1960 3435,1960 R32.2@3440,1955
  L4_SIG w4: v3(2559.34,1906.17) 2559.34,1909.34 2575,1925 2575,1945 2581.67,1951.67 2659.63,1951.67 2668,1943.3 2668,1928 2679,1917 2951,1917 2978,1890 3115,1890 3190,1815 3355,1815 3385,1845 3385,1865 v1(3370,1880)
  Bottom Layer w5: U13.P5@2544.49,1921.02 v3(2559.34,1906.17)
RMII_RXER: R40.2 U3.10 U13.C10 | length 1651.4
  Top Layer w5: R40.2@3480,1790 3485,1785 v1(3506,1785) 3515,1785 3570.16,1840.16 U3.10@3578.23,1840.16
  L4_SIG w4: v3(2372,2282.49) 2389.51,2300 2465,2300 2470,2305 2620,2305 2640,2285 2665,2285 2690,2260 2810,2260 2815,2255 3155,2255 3165,2265 3200,2265 3252.5,2212.5 3252.5,2142.5 3270,2125 3335,2125 3365,2095 3365,2075 3485,1955 3485,1806 v1(3506,1785)
  Bottom Layer w5: v3(2372,2282.49) U13.C10@2387.01,2267.48
RMII_TX_EN: U3.16 U13.B8 | length 1977.4
  Top Layer w5: v1(3663.68,1710) 3664.84,1711.16 U3.16@3664.84,1773.23
  L4_SIG w4: v1(2449.5,2405) 2484,2405 2497,2392 2497.27,2392 2497.43,2391.84 2574.16,2391.84 2599,2367 2722,2367 2733,2356 2923,2356 3029,2462 3141,2462 3281,2322 3328,2322 3395,2255 3395,2086.73 3545,1936.73 3545,1770 3605,1710 v1(3663.68,1710)
  Bottom Layer w5: v1(2449.5,2405) 2459,2405 2469,2395 2469,2338.48 2467,2336.48 2467,2315.98 U13.B8@2450,2298.98
RMII_TXD0: U3.17 U13.B3 | length 1884.6
  Top Layer w5: U3.17@3684.53,1773.23 3684.53,1716.42 3695.95,1705 v1(3705,1705)
  L4_SIG w4: v1(2611,2425) 2618,2425 2648,2395 2941,2395 3019,2473 3146,2473 3285.44,2333.56 3331,2333.56 3405,2259.56 3405,2089.46 3555,1939.46 3555,1774 3599,1730 3680,1730 v1(3705,1705)
  Bottom Layer w5: U13.B3@2607.48,2298.98 2624,2315.5 2624,2344 2633,2353 2633,2409 2619,2423 2613,2423 v1(2611,2425)
RMII_TXD1: U3.18 U13.A4 | length 1852.2
  Top Layer w5: v1(3704.21,1735.79) U3.18@3704.21,1773.23
  L4_SIG w4: v1(2609,2464) 2609,2451.05 2628,2432.05 ; 2628,2432 2656,2404 2930,2404 3011,2485 3150,2485 3290,2345 3334.56,2345 3415,2264.56 3415,2094 3565,1944 3565,1780 3605,1740 3700,1740 v1(3704.21,1735.79)
  Bottom Layer w5: U13.A4@2575.98,2330.47 2575.98,2430.98 v1(2609,2464)
SAI1_FSA: TP6.1 U11.E3 U13.A1 | length 2205.1
  L4_SIG w3.5: v4(1054.47,2494) 1063.47,2503 1100,2503 1117,2520 1120,2520
  L4_SIG w4: 1120,2520 1200,2520 1225,2545 1225,2669 1254,2698 v1(1280,2698) 1327,2745 2299,2745 2376.79,2667.21 2376.79,2588.21 2385,2580 2464,2580 2496,2548 2618,2548 2685.9,2480.1 v1(2704.63,2480.1)
  Bottom Layer w3.5: U11.E3@1044.84,2484.37 v4(1054.47,2494)
  Bottom Layer w5: TP6.1@1240,2710 1268,2710 v1(1280,2698) ; U13.A1@2670.47,2330.47 2670.47,2411.47 2685,2426 2685,2445.75 2704.63,2465.38 v1(2704.63,2480.1)
SAI1_MCLKA: TP22.1 U11.D3 U13.J14 | length 2670
  Top Layer w5: v4(1015.73,2474.94) 1010.94,2474.94 962,2426 962,2367 986,2343 1066,2343 1151,2258 1208,2258 1253,2213 1253,1472 1315,1410 1480,1410 v1(1495,1395)
  Bottom Layer w3.5: v4(1015.73,2474.94) U11.D3@1025.16,2484.37
  Bottom Layer w5: v1(1495,1395) 1528,1428 1567,1428 1914,1775 1914,1954 1925.5,1965.5 1956.5,1965.5 1966,1975 2049,1975 2089,2015 TP22.1@2090,2015 2151,2015 2198.8,2062.8 2245.32,2062.8 U13.J14@2261.02,2078.5
SAI1_SCKA: TP8.1 U11.G1 U13.B1 | length 2084.8
  L4_SIG w4: v1(1205,2670) 1290,2755 2302,2755 2496,2561 2661,2561 2725,2497 2725,2461 v1(2705,2441)
  Bottom Layer w5: U11.G1@1084.21,2523.74 1170,2609.53 TP8.1@1170,2645 1195,2670 v1(1205,2670) ; U13.B1@2670.47,2298.98 2685,2313.51 2685,2400 2705,2420 v1(2705,2441)
SAI1_SDA: TP7.1 U11.E4 U13.B2 | length 2173.5
  L4_SIG w3.5: v4(1054.69,2474.54) 1055.94,2475.79 1055.94,2475.94 1075,2495 1120,2495
  L4_SIG w4: 1120,2495 1132,2495 1144,2507 1214,2507 1239,2532 1239,2624 v1(1280,2665) 1351,2736 2294,2736 2367.5,2662.5 2367.5,2582.5 2380,2570 2460,2570 2492,2538 2594,2538 2667,2465 v1(2667,2437)
  Bottom Layer w3.5: U11.E4@1044.84,2464.69 v4(1054.69,2474.54)
  Bottom Layer w4: U13.B2@2638.98,2298.98 2655,2315 2655,2364
  Bottom Layer w5: TP7.1@1240,2645 1260,2665 v1(1280,2665) ; 2655,2364 2655,2425 v1(2667,2437)
SAI1_SDB: TP11.1 U11.F2 U13.A2 | length 2130.5
  L4_SIG w3.5: v4(1074.28,2513.81) 1100.47,2540
  L4_SIG w4: 1100.47,2540 1185,2624.53 1185,2680 1270,2765 2310,2765 2445,2630 2631.99,2630 v1(2632.92,2630.93)
  Bottom Layer w3.5: U11.F2@1064.53,2504.06 v4(1074.28,2513.81)
  Bottom Layer w5: v1(2632.92,2630.93) 2674.07,2630.93 TP11.1@2680,2625 2680,2609 2638.98,2567.98 2638.98,2458.02 2644,2453 2644,2335.49 U13.A2@2638.98,2330.47
SCLK_MCLK: CN1.35 TP1.1 | length 128.3
  Top Layer w5: v1(3425,3340) 3440.78,3324.22 CN1.35@3440.78,3276.53
  Bottom Layer w5: TP1.1@3405,3290 3405,3320 v1(3425,3340)
SPDIF_I2S: R7.1 R100.1 TP20.1 U13.N10 | length 4278.9
  Top Layer w5: v1(1535,1778) 1699,1778 1823,1902 1957.25,1902 1981.75,1926.5 2137.5,1926.5 2166,1955 2221.02,1955 2260.67,1994.65 2260.67,2007.67 2268,2015 2314.51,2015 2324.5,2005.01 2324.5,1994.99 2335.49,1984 2348,1984 2357,1975 2357,1961 2371,1947 v3(2371,1937) ; v1(2930,2170) 2930,2401 3090,2561 3090,2946 v1(3125,2981)
  L4_SIG w4: v3(2371,1937) 2430,1937 2446,1921 2474,1921 2482,1929 2482,2037.61 2490.55,2046.16 2500.15,2046.16 2511.84,2057.85 2511.84,2065.95 2523.54,2077.65 2531.64,2077.65 2543.34,2089.35 2543.34,2097.01 2555.2,2108.87 2559.87,2108.87 2586,2135 2705,2135 2730,2160 2920,2160 v1(2930,2170)
  Bottom Layer w5: TP20.1@835,2085 860,2085 900,2125 1295,2125 1330,2090 1330,1815 1367,1778 v1(1535,1778) ; v3(2371,1937) 2386.52,1952.52 U13.N10@2387.01,1952.52 ; v1(3125,2981) 3159,3015 3159,3156 3263,3260 R7.1@3350,3260
  Bottom Layer w10: R100.1@800,2255 800,2120 TP20.1@835,2085
SPDIF_RX: R112.2 R114.2 U13.C7 U15.4 | length 3118.9
  Top Layer w5: v1(765,1505) 798,1538 850,1538 v1(902,1590) ; v3(2465,2250.98) 2465,2255 2480,2270 2480,2290 2498,2308 2498,2373 2516,2391 2516,2417.84 v1(2515.91,2417.84)
  L4_SIG w4: v1(902,1590) 1203,1590 1265.5,1652.5 1265.5,2430.5 1316,2481 1596,2481 1696,2581 2220,2581 2330,2471 2434,2471 2468,2437 2481.45,2437 2495.45,2423 2511,2423 2516,2418 2516,2417.84 v1(2515.91,2417.84)
  Bottom Layer w5: v1(902,1590) 902,1632 R112.2@930,1660 965,1660 965.76,1659.24 966.1,1659.24 979.41,1645.93 U15.4@979.41,1630.43 ; v3(2465,2250.98) U13.C7@2481.5,2267.48
  Bottom Layer w10: v1(765,1505) R114.2@765,1540
STLINK_RX: SB18.2 U19.13 | length 85.3
  Bottom Layer w5: U19.13@3931.26,748.27 3953.27,748.27 3970,765 4007.98,765 SB18.2@4009.17,763.81
STLINK_TX: SB17.2 U19.12 | length 150.2
  Bottom Layer w5: U19.12@3868.27,811.26 3966.26,811.26 3988.81,833.81 SB17.2@4009.17,833.81
STM_JTCK: CN4.2 U19.37 | length 1067.2
  Top Layer w5: v1(3670,550) 3700,550 3765,485 3830,485 3865.39,449.61 3865.39,370.28 3895,340.67 3895,258 3981,172 4288,172 CN4.2@4365,95
  Bottom Layer w5: U19.37@3588.74,531.73 3651.73,531.73 v1(3670,550)
STM_JTMS: CN4.4 U19.34 | length 788
  Top Layer w5: v1(3700,520) 3750,470 3815,470 3850,435 3850,365 3880,335 3880,248 3971,157 4103,157 CN4.4@4165,95
  Bottom Layer w5: U19.34@3691.1,468.74 3691.1,511.1 v1(3700,520)
STM_RST: C132.2 R118.1 SB16.2 U19.7 | length 373.2
  Bottom Layer w5: U19.7@3769.84,811.26 3769.84,839.84 3780,850 3800,850 3830,880 3830,915 R118.1@3865,950 C132.2@3865,1000 3895,1030 3930,1030 3940,1020 3940,1005 3945,1000 3962.98,1000 SB16.2@3964.17,998.81
SWCLK: SB19.2 U13.A14 | length 3819.9
  L4_SIG w4: v1(2244,2793) 2537,2793 2765,2565 3100,2565 3296,2369 3336.9,2369 3435,2270.9 3435,2104 3585,1954 3585,1793 3610,1768 3713,1768 3744,1737 3744,1211 4008.5,946.5 4008.5,781.5 v1(4060,730)
  Bottom Layer w5: v1(2244,2793) 2243,2793 2195,2745 2195,2500 2259,2436 2259,2332.49 U13.A14@2261.02,2330.47 ; SB19.2@4040.83,696.19 4040.83,710.83 v1(4060,730)
SWDIO: SB22.2 U13.A15 | length 4581.4
  L4_SIG w4: v1(2180,2785) 2205,2810 2545,2810 2715,2640 3042,2640 3301,2381 3341,2381 3445,2277 3445,2108 3595,1958 3595,1798 3613,1780 3715,1780 3754,1741 3754,1221 4000,975 4045,975 4055,965 4055,845 4080,820 4080,725 4025,670 4025,420 3990,385 3908,385 v1(3898,395)
  Bottom Layer w5: v1(2180,2785) 2033,2638 2033,2427 2080,2380 2120,2380 2169.53,2330.47 U13.A15@2229.53,2330.47 ; SB22.2@3870.83,351.19 3871.19,351.19 3898,378 v1(3898,395)
SWO: R92.1 SB21.2 | length 3745.7
  L4_SIG w4: v1(2468,2696) 2609,2696 2755,2550 3100,2550 3293,2357 3336.02,2357 3425,2268.02 3425,2099 3575,1949 3575,1788 3609,1754 3712,1754 3734,1732 3734,1201 3997,938 3997,606 4009,594 4009,428 3983,402 3925,402 3902,425 v1(3805,425)
  Bottom Layer w5: R92.1@2405,2570 2405,2633 v1(2468,2696) ; SB21.2@3771.19,356.17 3788.17,356.17 3805,373 v1(3805,425)
T_JTCK: SB19.1 U19.15 U19.26 | length 381.4
  Bottom Layer w5: U19.26@3848.58,468.74 3848.58,678.58 3878.9,708.9 U19.15@3931.26,708.9 3971.1,708.9 3984.67,695.33 SB19.1@4001.99,695.33
T_JTMS: R143.1 SB22.1 U19.27 | length 124.2
  Bottom Layer w5: U19.27@3828.9,468.74 3828.9,406.1 R143.1@3830,405 3830,345
T_NRST: SB20.1 U19.18 | length 80.9
  Bottom Layer w5: U19.18@3931.26,649.84 3955.16,649.84 3979.67,625.33 SB20.1@4001.99,625.33
T_SWDIO_IN: R143.2 U19.25 | length 64.5
  Bottom Layer w5: U19.25@3868.27,468.74 3868.27,406.73 R143.2@3870,405
T_SWO: SB21.1 U19.31 | length 80.2
  Bottom Layer w5: U19.31@3750.16,468.74 3750.16,423.18 SB21.1@3770.33,395.01
TD_N: R41.2 T4.3 U3.20 | length 475.1
  Top Layer w6.1: U3.20@3731.77,1820.47 3742.65,1820.47 3745,1822.82 3762.96,1822.82 3783.78,1802 3804.81,1802 v1(3809.81,1797) 3815.31,1802.5 3832.5,1802.5 R41.2@3845,1790
  Bottom Layer w6.1: v1(3809.81,1797) 3804.31,1802.5 3793.72,1802.5 3785,1793.78 3785,1757.22 3834.22,1708 3892,1708 3901,1717 3901,1768 3908,1775 T4.3@3982.48,1775
TD_P: R39.2 T4.1 U3.21 | length 475.1
  Top Layer w6.1: U3.21@3731.77,1840.16 3740,1840.16 3742.34,1837.82 3769.18,1837.82 3790,1817 3803.81,1817 v1(3809.81,1823) 3815.31,1817.5 3832.5,1817.5 R39.2@3845,1830
  Bottom Layer w6.1: v1(3809.81,1823) 3804.31,1817.5 3787.5,1817.5 3770,1800 3770,1751 3828,1693 3927,1693 3945,1675 T4.1@3982.48,1675
ULPI_CK: U13.P4 U20.1 | length 1604.4
  L4_SIG w4: v3(2590.83,1906.17) 2590.83,1905.83 2586.89,1901.89 2586.89,1843.11 2636,1794 2670,1794 2705.5,1758.5 2705.5,1743.5 2711,1738 2877,1738 2895,1720 3023,1720 3066,1677 3066,799 v1(3061,794)
  Bottom Layer w4: U13.P4@2575.98,1921.02 v3(2590.83,1906.17)
  Bottom Layer w5: U20.1@3041.1,725.28 3041.1,774.1 v1(3061,794)
ULPI_D0: U13.R2 U20.3 | length 1558.1
  L4_SIG w4: v3(2733,1799) 2879,1799 2924,1754 3052,1754 3117,1689 3117,810 v1(3100,793)
  Bottom Layer w5: U13.R2@2638.98,1889.53 2641.47,1889.53 2646,1885 2651.66,1885 2685.66,1851 2712,1851 2732,1831 2732,1800 v3(2733,1799) ; U20.3@3080.47,725.28 3080.47,773.47 v1(3100,793)
ULPI_D1: U13.R5 U20.4 | length 1593.6
  L4_SIG w4: v3(2601.88,1848.23) 2601.88,1846.12 2645,1803 2678,1803 2708,1773 2863,1773 2905,1731 3036,1731 3081,1686 3081,779 3095.16,764.84 v1(3100.16,764.84)
  Bottom Layer w5: U13.R5@2544.49,1889.53 2585.77,1848.23 v3(2601.88,1848.23) ; U20.4@3100.16,725.28 v1(3100.16,764.84)
ULPI_D2: U13.R4 U20.5 | length 1592.5
  L4_SIG w4: v3(2600.89,1869.21) 2612.79,1869.21 2629,1853 2629,1832 2649,1812 2688,1812 2716,1784 2874,1784 2916,1742 3044,1742 3098,1688 v1(3098,820)
  Bottom Layer w5: U13.R4@2575.98,1889.53 2596.3,1869.21 v3(2600.89,1869.21) ; v1(3098,820) 3103,820 3119.84,803.16 U20.5@3119.84,725.28
ULPI_D3: U13.P12 U20.6 | length 2190.5
  Top Layer w5: v3(2309.17,1906.17) 2309.17,1896.17 2294,1881 2294,1868 2287,1861 2287,1747 2140,1600 2140,1038 2207,971 3040,971 v1(3137,874)
  Bottom Layer w5: v3(2309.17,1906.17) U13.P12@2324.02,1921.02 ; v1(3137,874) 3117,854 3117,828 3139.53,805.47 U20.6@3139.53,725.28
ULPI_D4: U13.R13 U20.7 | length 2175.4
  Top Layer w5: v3(2277.67,1874.68) 2245.5,1842.51 2245.5,1828.5 2235,1818 2235,1720 2115,1600 2115,1285 2095,1265 2095,1046 2211,930 3045,930 v1(3135,840)
  Bottom Layer w5: v3(2277.67,1874.68) U13.R13@2292.52,1889.53 ; v1(3135,840) 3159.21,815.79 U20.7@3159.21,725.28
ULPI_D5: U13.L13 U20.9 | length 2171.7
  L4_SIG w4: v3(2310,1999) 2324,2013 2346.8,2013 2355,2004.8 2355,1993.2 2346.8,1985 2336.69,1985 2325,1973.31 2325,1933.2 2335.2,1923 2352,1923 2365,1910 2395,1910 2423,1882 2507,1882 2612,1777 2612,1744 2618,1738 2643,1738 2707,1674 2807,1674 2819,1686 2964,1686 3027,1623 3027,829.15 3017.39,819.54 3017.39,758.61 3049,727 3215.54,727 v1(3236.54,706)
  Bottom Layer w5: U13.L13@2292.52,2015.51 2293.48,2015.51 v3(2310,1999) ; U20.9@3205.28,698.9 3223.9,698.9 3231,706 v1(3236.54,706)
ULPI_D6: U13.K14 U20.10 | length 2348.4
  L4_SIG w4: v3(2246,2030) 2247,2029 2317,2029 2334,2046 2367,2046 2386.16,2026.84 2386.16,1991.16 2380,1985 2368.19,1985 2355,1971.81 2355,1933.2 2368.2,1920 2400,1920 2430,1890 2512,1890 2627,1775 2658,1775 2682,1751 2682,1716 2712,1686 2801,1686 2812,1697 3009,1697 3039.02,1666.98 3039.02,821.05 3029.61,811.64 3029.61,763.39 3053.98,739.02 3231.98,739.02 3258,713 3258,698 v1(3239.21,679.21)
  Bottom Layer w5: v3(2246,2030) 2246,2031.99 U13.K14@2261.02,2047.01 ; U20.10@3205.28,679.21 v1(3239.21,679.21)
ULPI_D7: U13.A8 U20.13 | length 3129.2
  L4_SIG w4: v1(2449.5,2370) 2555,2370 2593.22,2331.78 2631.75,2331.78 2657.53,2306 2893,2306 3038,2451 3137,2451 3201.34,2386.66 3201.34,2294.34 3271.5,2224.18 3347.03,2224.18 3385,2186.21 3385,2084 3535,1934 3535,1765 3560,1740 3560,1580 3615,1525 3615,1328 3387,1100 3387,677.99 v1(3366.93,657.92)
  Bottom Layer w5: v1(2449.5,2370) 2450,2369.5 U13.A8@2450,2330.47 ; U20.13@3205.28,620.16 3225.16,620.16 3232,627 3335,627 3365.92,657.92 v1(3366.93,657.92)
ULPI_DIR: U13.F3 U20.31 | length 3059.9
  L4_SIG w4: v3(2622.33,2187.84) 2637.49,2203 2693.16,2203 2740.16,2250 2800,2250 2805,2245 3165,2245 3175,2255 3195,2255 3235,2215 3235,2135 3260,2110 3330,2110 3355,2085 3355,2070 3475,1950 3475,1790 3516.5,1748.5 3519.5,1748.5 3538,1730 3538,1296 3355,1113 3355,745 3295,685 3295,618 3232,555 3050,555 3035,570 3035,585 3000,620 2975,620 2949.21,645.79 v1(2949.21,670)
  Bottom Layer w4: U13.F3@2607.48,2172.99 v3(2622.33,2187.84)
  Bottom Layer w5: v1(2949.21,670) 2958.42,679.21 U20.31@3014.72,679.21
ULPI_NXT: U13.H4 U20.2 | length 1850.7
  L4_SIG w4: v3(2590.83,2095.15) 2590.83,2090.83 2575,2075 2575,2057.2 2565.6,2047.8 2556,2047.8 2545.34,2037.14 2545.34,1900.37 2553.54,1892.17 2564.83,1892.17 2575,1882 2575,1841.54 2631.54,1785 2663,1785 2693,1755 2693,1722 2717,1698 2795,1698 2805,1708 3016,1708 3052.13,1671.87 3052.13,814.1 3043,804.97 3043,777 v1(3060.79,759.21)
  Bottom Layer w4: U13.H4@2575.98,2110 v3(2590.83,2095.15)
  Bottom Layer w5: U20.2@3060.79,725.28 v1(3060.79,759.21)
ULPI_STP: U13.M2 U20.29 | length 2654.4
  L4_SIG w4: v3(2723,1985) 2790,1985 2831,2026 3009,2026 3065,1970 3170,1970 3215,1925 3375,1925 3440,1860 3440,1709 3503,1646 3503,1303 3325,1125 3285,1125 3260,1100 3260,790 3280,770 3280,665.75 3259.25,645 3225,645 3200,670 3200,685 3180,705 3046.33,705 v1(2981.17,639.84)
  Bottom Layer w5: U13.M2@2638.98,1984.02 2654.61,1968.4 2706.4,1968.4 v3(2723,1985) ; v1(2981.17,639.84) U20.29@3014.72,639.84
USB_HS_N: CN15.2 U20.19 U24.B1 | length 435.3
  Top Layer w6.1: v1(3104,225) 3109.5,230.5 3109.5,334.5 3141.87,366.87 3141.87,406.18 ; v3(3124.5,405.91) 3124.77,406.18 3141.87,406.18 ; v1(3136.37,470.81) 3141.87,465.31 3141.87,406.18
  Bottom Layer w6.1: v1(3104,225) 3110.57,218.43 3110.57,190.29 3105.28,185 CN15.2@3105.28,162.8 ; v3(3124.5,405.91) 3124.8,405.61 3136.26,405.61 U24.B1@3141.87,400 ; v1(3136.37,470.81) 3141.87,476.31 3141.87,505.35 3139.53,507.69 U20.19@3139.53,534.72
USB_HS_P: CN15.3 U20.18 U24.B2 | length 435.7
  Top Layer w6.1: v1(3130,225) 3124.5,230.5 3124.5,328.28 3156.87,360.65 3156.87,405 ; v1(3162.37,470.81) 3156.87,465.31 3156.87,405 ; v3(3175,406.18) 3158.05,406.18 3156.87,405
  Bottom Layer w6.1: v1(3130,225) 3125.57,220.57 3125.57,185 3130.87,179.7 CN15.3@3130.87,162.8 ; U24.B2@3157.62,400 3163.37,405.75 3174.57,405.75 v3(3175,406.18) ; U20.18@3159.21,534.72 3159.21,507.69 3156.87,505.35 3156.87,476.31 v1(3162.37,470.81)
USB_RENUMN: R145.2 U19.38 | length 489
  Top Layer w5: v1(3635,551.42) 3635,525 3705,455 3805,455 3835,425 3835,360 3860,335 v1(3860,310)
  Bottom Layer w5: U19.38@3588.74,551.42 v1(3635,551.42) ; v1(3860,310) R145.2@3895,275
USB_STLK_N: CN16.2 U19.32 | length 339.8
  Bottom Layer w6.1: U19.32@3730.47,468.74 3730.47,432.21 3728.13,429.87 3728.13,347.87 3768,308 3768,259 3745,236 3745,218 3755.3,207.7 3755.3,189 3760.59,183.71 CN16.2@3760.59,162.4
USB_STLK_P: CN16.3 R148.1 U19.33 | length 344
  Bottom Layer w6.1: U19.33@3710.79,468.74 3710.79,432.21 3713.13,429.87 3713.13,341.65 3753,301.78 3753,265.22 3725,237.22 R148.1@3725,235 3725,231 3730,226 3730,211.78 3740.3,201.48 3740.3,189 3735,183.7 CN16.3@3735,162.4
uSD_CLK: CN5.5 U13.B11 | length 1043.2
  Bottom Layer w5: U13.B11@2355.51,2298.98 2341,2313.49 2341,2464 2300,2505 2300,2765 2400,2865 2400,2909 2472,2981 2617,2981 2646.3,2951.7 CN5.5@2646.3,2871.21
uSD_CMD: CN5.3 R81.1 U13.A11 | length 908.9
  Bottom Layer w5: U13.A11@2355.51,2330.47 2355.51,2470 2312,2513.51 2312,2752 2419,2859 2419,2898 2462,2941 2533,2941 2559.69,2914.31 CN5.3@2559.69,2871.21 2559.69,2805.31 R81.1@2560,2805
uSD_D0: CN5.7 R80.1 U13.D9 | length 972
  Top Layer w5: v3(2403.65,2250.83) 2403.83,2250.83 2425,2272 2425,2309 2431,2315 2431,2406 2409,2428 2409,2483 2380,2512 2380,2579 2466,2665 2690,2665 v1(2730,2705)
  Bottom Layer w4: v3(2403.65,2250.83) U13.D9@2418.5,2235.98
  Bottom Layer w5: v1(2730,2705) 2730,2706 2705,2731 2705,2780 R80.1@2730,2805 2732.91,2807.91 CN5.7@2732.91,2871.21
uSD_D1: CN5.8 R79.1 U13.C8 | length 902.7
  Top Layer w5: v3(2464.85,2282.33) 2464.85,2289.85 2487,2312 2487,2430.75 2485,2432.75 2485,2485 2470,2500 2470,2611 2510,2651 2725,2651 v1(2780,2706)
  Bottom Layer w5: U13.C8@2450,2267.48 v3(2464.85,2282.33) ; CN5.8@2776.22,2871.21 2780,2867.43 R79.1@2780,2805 2755,2780 2755,2731 v1(2780,2706)
USD_D2: CN5.1 R83.1 R93.1 | length 377.1
  Bottom Layer w5: R93.1@2355,2570 2355,2736 2424,2805 R83.1@2470,2805 2473.07,2808.07 CN5.1@2473.07,2871.21
uSD_D3: CN5.2 R82.1 U13.A9 | length 593.7
  Bottom Layer w5: U13.A9@2418.5,2330.47 2421,2332.97 2421,2415 2406,2430 2406,2486 2429.97,2509.97 2429.97,2539.97 2450,2560 2450,2645 2490,2685 2490,2780 R82.1@2515,2805 2516.38,2806.38 CN5.2@2516.38,2871.21
uSD_Detect: R73.1 R76.1 U13.G4 | length 1436.6
  Top Layer w5: v3(2590.83,2156.35) 2607.83,2173.35 2607.83,2272.83 2685,2350 2685,2489 2698,2502 2698,2573 2776.5,2651.5 3020.5,2651.5 3060,2691 v1(3060,2850)
  L4_SIG w4: v1(2943,3090) 2967,3090 3060,2997 v1(3060,2850)
  Bottom Layer w4: U13.G4@2575.98,2141.5 v3(2590.83,2156.35)
  Bottom Layer w5: R73.1@2915,3130 R76.1@2915,3080 2933,3080 v1(2943,3090)
VCP_RX: JP5.2 SB17.1 U13.D15 | length 4189.3
  L4_SIG w4: v1(2180,2815) 2188,2823 2557,2823 2725,2655 3044.15,2655 3305.59,2393.56 3343.28,2393.56 3455,2281.84 3455,2113 3644,1924 3699,1924 3719,1904 3719,1796 3764,1751 3764,1236 3860,1140 JP5.2@3895,1140
  Bottom Layer w5: v1(2180,2815) 2175,2815 1970,2610 1970,2315 2064,2221 2114.22,2221 2131.22,2238 2227.51,2238 U13.D15@2229.53,2235.98 ; JP5.2@3895,1140 3956,1079 4016,1079 4060,1035 4060,846.66 SB17.1@4048.01,834.67
VCP_TX: JP5.1 SB18.1 U13.E15 | length 4383.9
  L4_SIG w4: v1(2180,2845) 2189,2836 2564,2836 2730,2670 3043.3,2670 3309.74,2403.56 3349.28,2403.56 3465,2287.84 3465,2115.73 3646.73,1934 3707,1934 3730,1911 3730,1800 3774,1756 3774,1246 3836,1184 3951,1184 JP5.1@3995,1140
  Bottom Layer w4: 2191,2204.49 U13.E15@2229.53,2204.49
  Bottom Layer w5: v1(2180,2845) 1955,2620 1955,2290 2055,2190 2128.22,2190 2142.71,2204.49 2191,2204.49 ; JP5.1@3995,1140 4085,1050 4085,801.66 SB18.1@4048.01,764.67
VDD: C68.1 C69.1 C76.2 C80.2 C83.2 C86.2 C88.2 C97.2 C99.2 C104.2 C105.2 C106.2 C107.2 C108.2 C109.2 C110.2 C111.2 C112.2 C113.2 C114.2 C115.2 JP4.1 L6.1 R109.1 U13.C1 U13.E7 U13.E8 U13.E9 U13.E10 U13.F4 U13.F5 U13.F11 U13.G5 U13.G11 U13.H5 U13.H11 U13.J5 U13.J11 U13.K5 U13.K11 U13.L7 U13.L8 U13.L9 U13.L10 | length 1600.3
  Bottom Layer w15: v1(2144,1784) 2150,1778 C115.2@2150,1755 ; C114.2@2205,1755 C113.2@2255,1755 2255,1769 v1(2267,1781) ; C112.2@2305,1755 C111.2@2360,1755 2362,1755 2367,1760 v1(2367,1785) ; v3(2340.66,2187.84) U13.F11@2355.51,2172.99 ; U13.K11@2355.51,2047.01 2371,2062.5 v3(2371,2063) U13.J11@2355.51,2078.5 ; U13.H11@2355.51,2110 U13.G11@2355.51,2141.5 2362,2147.99 v3(2372,2158) ; v3(2372.16,2000.66) U13.L10@2387.01,2015.51 ; U13.E10@2387.01,2204.49 2401.86,2219.34 v3(2403.65,2219.34) U13.E9@2418.5,2204.49 ; v3(2403.65,2000.66) U13.L9@2418.5,2015.51 ; C110.2@2405,1755 C109.2@2450,1755 2450,1780 v1(2452,1782) ; U13.L8@2450,2015.51 v3(2464.85,2000.66) ; U13.E8@2450,2204.49 2465,2189.49 v3(2465,2189) ; U13.L7@2481.5,2015.51 v3(2496.35,2000.66) ; U13.E7@2481.5,2204.49 v3(2496.35,2219.34) ; v3(2529,2032) 2544.01,2047.01 U13.K5@2544.49,2047.01 ; v3(2529,2157.5) U13.F5@2544.49,2172.99 ; v3(2529.34,2063.65) 2529.64,2063.65 U13.J5@2544.49,2078.5 ; v3(2529.34,2095.15) 2529.64,2095.15 U13.H5@2544.49,2110 ; U13.G5@2544.49,2141.5 v3(2559.34,2156.35) ; C108.2@2545,1755 v1(2574,1755) ; U13.F4@2575.98,2172.99 v3(2590.83,2187.84) ; C107.2@2600,1755 v1(2629,1755) C106.2@2655,1755 ; U13.C1@2670.47,2267.48 2687.48,2267.48 v3(2699,2279) ; C105.2@2695,1755 v1(2725,1755) C104.2@2755,1755 ; v1(2778,2130) C99.2@2810,2130 ; v1(2778,2180) C97.2@2810,2180 ; v1(2778,2230) C88.2@2810,2230 ; v1(2780,2280) C86.2@2810,2280 ; v1(2780,2325) C83.2@2810,2325 ; v1(2780,2375) C80.2@2810,2375 ; v1(3020,1655) L6.1@3020,1695
  Bottom Layer w20: 1636.98,2025 JP4.1@1675,2025 ; 1645.51,1898.48 R109.1@1645.51,1930 ; 1645.51,1961.52 R109.1@1645.51,1930 ; 1675,1986.98 JP4.1@1675,2025 ; 1675,2063.02 JP4.1@1675,2025 ; 1678.03,1930 R109.1@1645.51,1930 ; 1713.02,2025 JP4.1@1675,2025 ; v2(2780,2425) C76.2@2810,2425 ; v2(2785,2515) 2815,2515 C69.1@2835,2495 2866,2464 v2(2885,2464) ; v2(2885,2495) C68.1@2940,2495 v2(2990,2495)
  other v2: 1640,1830 1670,1830 1700,1830 1640,1860 1670,1860 1700,1860
VDDA: C103.2 C116.1 L6.2 R110.1 U13.R1 | length 620.4
  Bottom Layer w20: U13.R1@2670.47,1889.53 2687,1873 2770,1873 2795,1848 2795,1755 C116.1@2830,1720 2865,1755 C103.2@2865,1790 2865,1800 2885,1820 2965.51,1820 2975,1829.49 R110.1@3020,1829.49 L6.2@3020,1755
VIN: C129.2 CN11.8 U18.3 | length 1634.5
  L4_SIG w20: v2(4080.51,1167.49) 4080.51,879.49 4105,855 4105,756 v2(4148,713)
  Bottom Layer w20: CN11.8@3305.8,1567.7 3661.5,1212 4036,1212 v2(4080.51,1167.49) ; 4129.45,822.46 U18.3@4129.45,865.98 ; 4129.45,909.5 U18.3@4129.45,865.98 ; 4157.47,865.98 U18.3@4129.45,865.98 ; 4204.48,750 C129.2@4235,750 ; 4235,716.98 C129.2@4235,750 ; 4235,783.02 C129.2@4235,750
VREF+: C85.2 C101.1 C102.2 R98.2 R110.2 U13.P1 | length 4432
  L4_SIG w20: v2(1595,930) 1595,1345 1475,1465 1475,2160 1620,2305 v2(1635,2305)
  Bottom Layer w20: v2(1595,930) 2185,930 2240,875 2686,875 2746,935 2880,935 3070,1125 3070,1870 3049.49,1890.51 R110.2@3020,1890.51 3011.49,1882 2885,1882 2865,1862 C102.2@2865,1850 2850,1850 2830,1870 C101.1@2830,1930 2780,1930 2765,1915 2676.49,1915 U13.P1@2670.47,1921.02 ; R98.2@1605,2355 C85.2@1605,2310 1610,2305 v2(1635,2305)
WIFI_RST: CN2.4 R200.2 U13.C9 | length 3182.2
  Top Layer w5: CN2.4@915,860 R200.2@1040,860 1065,885 v1(1205,885) ; v1(2402.5,2406) 2402.5,2405 2420,2387.5 2420,2327 2403.49,2310.49 v3(2403.49,2282.49)
  L4_SIG w4: v1(1205,885) 1296,976 1296,2301 1380,2385 1555,2385 1720,2550 2177,2550 2262,2465 2304,2465 2319,2450 2358.5,2450 v1(2402.5,2406)
  Bottom Layer w5: v3(2403.49,2282.49) U13.C9@2418.5,2267.48
WIFI_RX: R50.1 U13.A12 | length 2797.1
  Top Layer w5: R50.1@1080,905 1243,905 1259,889 v1(1259,885)
  L4_SIG w4: v1(1259,885) 1321,947 1321,2201 1401,2281 1429,2281 1489,2341 1549,2341 1739,2531 2158,2531 2244,2445 2283,2445 2322,2406 v1(2322,2405)
  Bottom Layer w5: v1(2322,2405) 2324.02,2402.98 U13.A12@2324.02,2330.47
WIFI_TX: R57.2 U13.D12 | length 3570.3
  Top Layer w5: R57.2@1080,705 1415,705 1530,820 1530,1390 1495,1425 1335,1425 1275,1485 1275,2190 v1(1320,2235) ; v1(2322,2431) 2342,2411 2342,2310 2325,2293 2325,2277.49 2341,2261.49 v3(2341,2251)
  L4_SIG w4: v1(1320,2235) 1320,2305 1385,2370 1560,2370 1730,2540 2169,2540 2254,2455 2296,2455 2320,2431 v1(2322,2431)
  Bottom Layer w5: U13.D12@2324.02,2235.98 2325.98,2235.98 v3(2341,2251)
pads on no net: "CN1. " "CN5. " "CN6. " "CN7. " CN1.2 CN1.20 CN1.22 CN1.24 CN1.25 CN1.26 CN1.28 CN1.30 CN1.31 CN1.32 CN1.33 CN1.34 CN1.38 CN1.41 CN1.42 CN1.43 CN1.46 CN1.48 CN1.50 CN1.51 CN1.52 CN1.54 CN1.55 CN1.56 CN1.58 CN1.59 CN5.11 CN5.12 CN5.13 CN5.14 CN6.5 CN6.7 CN7.5 CN7.7 Designator1.1 T4.4 T4.5 T4.12 T4.13 U2.1 U2.2 U3.4 U7.3 U7.5 U11.A6 U11.A8 U11.B4 U11.B5 U11.B8 U11.C4 U11.C5 U11.C7 U11.C8 U11.E1 U11.E5 U11.F4 U11.F5 U11.F6 U11.F8 U11.F9 U11.G4 U11.H2 U11.H3 U11.H4 U11.H5 U12.9 U15.1 U16.1 U17.E7 U17.H3 U17.H7 U17.K2 U17.K3 U19.4 U19.11 U19.14 U19.16 U19.17 U19.19 U19.21 U19.22 U19.29 U19.40 U19.41 U19.42 U19.43 U19.45 U19.46 U20.12 U20.15 U20.16 U20.25 U23.9
copper on no net: | length 2640
  Top Layer w10: 530,1220 585,1220 ; 530,1220 530,1275 ; 530,1220 585,1220 ; 530,1220 530,1275 ; 530,1275 585,1275 ; 530,1275 585,1275 ; 530,1300 585,1300 ; 530,1300 530,1355 ; 530,1300 585,1300 ; 530,1300 530,1355 ; 530,1355 585,1355 ; 530,1355 585,1355 ; 585,1220 585,1275 ; 585,1220 585,1275 ; 585,1300 585,1355 ; 585,1300 585,1355
  L4_SIG w10: 740,1220 740,1275 ; 740,1220 740,1275 ; 740,1220 795,1220 ; 740,1220 795,1220 ; 740,1275 795,1275 ; 740,1275 795,1275 ; 740,1300 740,1355 ; 740,1300 740,1355 ; 740,1300 795,1300 ; 740,1300 795,1300 ; 740,1355 795,1355 ; 740,1355 795,1355 ; 795,1220 795,1275 ; 795,1220 795,1275 ; 795,1300 795,1355 ; 795,1300 795,1355
  Bottom Layer w10: 880,1220 935,1220 ; 880,1220 880,1275 ; 880,1220 935,1220 ; 880,1220 880,1275 ; 880,1275 935,1275 ; 880,1275 935,1275 ; 880,1300 935,1300 ; 880,1300 880,1355 ; 880,1300 935,1300 ; 880,1300 880,1355 ; 880,1355 935,1355 ; 880,1355 935,1355 ; 935,1220 935,1275 ; 935,1220 935,1275 ; 935,1300 935,1355 ; 935,1300 935,1355

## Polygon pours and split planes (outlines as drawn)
no net on LAY4 (solid): 23 vertices, not listed, extent -100,0 0,100
no net on LAY4 (solid): 23 vertices, not listed, extent 0,-100 100,0
no net on LAY4 (solid): 4715,3080 ccw(c4655,3080) 4655,3140 ccw(c4655,3080) 4595,3080 ccw(c4655,3080) 4655,3020 ccw(c4655,3080) 4715,3080
no net on LAY4 (solid): 4715,3080 ccw(c4655,3080) 4655,3140 ccw(c4655,3080) 4595,3080 ccw(c4655,3080) 4655,3020 ccw(c4655,3080) 4715,3080
no net on LAY4 (solid): 500,390 ccw(c440,390) 440,450 ccw(c440,390) 380,390 ccw(c440,390) 440,330 ccw(c440,390) 500,390
no net on LAY4 (solid): 500,390 ccw(c440,390) 440,450 ccw(c440,390) 380,390 ccw(c440,390) 440,330 ccw(c440,390) 500,390
no net on LAY4 (solid): 455,3055 ccw(c395,3055) 395,3115 ccw(c395,3055) 335,3055 ccw(c395,3055) 395,2995 ccw(c395,3055) 455,3055
no net on LAY4 (solid): 455,3055 ccw(c395,3055) 395,3115 ccw(c395,3055) 335,3055 ccw(c395,3055) 395,2995 ccw(c395,3055) 455,3055
no net on LAY4 (solid): 23 vertices, not listed, extent -100,0 0,100
no net on LAY4 (solid): 23 vertices, not listed, extent 0,-100 100,0
POE4 on Bottom Layer "BOTTOM-POE4" (solid, pour order 14): 45 vertices, not listed, extent 3615,2155 3945,2335
POE7 on Bottom Layer "BOTTOM-POE7 3" (solid, pour order 0): 439 vertices, not listed, extent 3400,21 3935,195
POE7 on Bottom Layer "BOTTOM-POE7 2" (solid, pour order 2): 24 vertices, not listed, extent 4275,690 4570,925
POE7 on Bottom Layer "BOTTOM-POE7 1" (solid, pour order 4): 18 vertices, not listed, extent 1100.92,1951.78 1270.71,2111.79
POE7 on Bottom Layer "BOTTOM-POE7" (solid, pour order 6): 4406.8,2460 4406.8,2514.22 4280,2514.22 4280,2550.62 4406.8,2550.62 4406.8,2612.66 4280,2612.66 4280,2625 4420,2625 4435,2610 4435,2475 4420,2460 4406.8,2460
POE5 on Bottom Layer "BOTTOM-POE5" (solid, pour order 16): 49 vertices, not listed, extent 4405,2270 4665,2465
NETC18_2 on Bottom Layer "BOTTOM-NETC18_2" (solid, pour order 22): 4475,2495 4460,2510 4460,2660 4470,2670 4615,2670 4660,2625 4660,2557.02 4626.48,2557.02 4626.48,2512.98 4660,2512.98 4660,2505 4650,2495 4475,2495
3V3 on Bottom Layer "BOTTOM-3V3 1" (solid, pour order 28): 1160,1715 1140,1735 1140,1820 1149.04,1829.04 1172.5,1829.04 1172.5,1773.44 1255.54,1773.44 1255.54,1829.04 1270.96,1829.04 1280,1820 1280,1725 1270,1715 1160,1715
3V3 on Bottom Layer "BOTTOM-3V3" (solid, pour order 30): 127 vertices, not listed, extent 1475,1810 1605,2085
1V8 on Bottom Layer "BOTTOM-1V8" (solid, pour order 34): 20 vertices, not listed, extent 907.02,1800.15 1273.86,2112.48
AGND on Bottom Layer "BOTTOM-AGND" (solid, pour order 38): 120 vertices, not listed, extent 3900,2935 4595,3305
NETC153_2 on Bottom Layer "BOTTOM-NETC153_2" (solid, pour order 40): 410 vertices, not listed, extent 2905,20.4 3390,325
5V_ST_LINK on Bottom Layer "BOTTOM-5V_ST_LINK" (solid, pour order 42): 21 vertices, not listed, extent 4335,330 4455,405
5V_USB_CHARGER on Bottom Layer "BOTTOM-5V_USB_CHARGER" (solid, pour order 44): 107 vertices, not listed, extent 3960,155 4475,360
VDD on Bottom Layer "BOTTOM-VDD" (solid, pour order 46): 1635,1810 1625,1820 1625,1900.48 1676.02,1900.48 1676.02,1959.52 1625,1959.52 1625,2060 1640,2075 1760,2075 1775,2060 1775,1820 1765,1810 1635,1810
VIN on Bottom Layer "BOTTOM-VIN" (solid, pour order 48): 67 vertices, not listed, extent 4095,625 4255,933
E5V on Bottom Layer "BOTTOM-E5V" (solid, pour order 50): 24 vertices, not listed, extent 4135,916 4575,1175
NETC40_2 on Top Layer "TOP-NETC40_2" (solid, pour order 52): 3413,2475.56 3413.56,2476.11 3745.49,2476.11 3745.49,2285.67 3745.21,2285.39 3539.11,2285.39 3524.5,2300 3499.83,2300 3415,2384.83 3415,2473.56
POE7 on Top Layer "TOP-POE7" (solid, pour order 8): 34 vertices, not listed, extent 4160,2889.15 4495,2985
POE3 on Top Layer "TOP-POE3" (solid, pour order 10): 3440,2635 3425,2650 3425,2790 3445,2810 3520,2810 3590,2740 3687.5,2740 3687.5,2700 3590,2700 3525,2635 3440,2635
POE4 on Top Layer "TOP-POE4" (solid, pour order 12): 95 vertices, not listed, extent 3535,2155 3715,2265
NETC18_2 on Top Layer "TOP-NETC18_2" (solid, pour order 20): 17 vertices, not listed, extent 4350,2600 4570,2730
NETC72_2 on Top Layer "TOP-NETC72_2" (solid, pour order 26): 300 vertices, not listed, extent 2217,2198 2358,2426
5V on Top Layer "TOP-5V" (solid, pour order 32): 21 vertices, not listed, extent 4330,390 4955,510
5V_POE on Top Layer "TOP-5V_POE" (solid, pour order 36): 94 vertices, not listed, extent 4170,2735 4485,2875
NETC4_1 on L4_SIG "L4_SIG-NETC4_1" (solid, pour order 24): 4160,3325 4180,3345 4575,3345 4590,3330 4590,3135 4560,3105 4530,3105 4490,3145 4340,3145 4330,3135 4330,3025 4315,3010 4180,3010 4160,3030 4160,3325
POE1 on L2_GND (split plane): 49 vertices, not listed, extent 3380.09,2125.09 4574.91,3444.46
POE7 on L2_GND (split plane): 649.9,1225.1 637.66,1225.1 637.66,1268.99 605.1,1268.99 605.1,1269.9 649.9,1269.9
POE7 on L2_GND (split plane): 649.9,1305.1 639.36,1305.1 639.36,1347.29 606.7,1347.29 606.7,1305.1 605.1,1305.1 605.1,1349.9 649.9,1349.9
POE7 on L2_GND (split plane): 154 vertices, not listed, extent 20.1,20.1 4979.9,3444.46
VDD on L3_VCC (split plane): 40 vertices, not listed, extent 1630.09,1610.09 3089.91,2559.91
3V3 on L3_VCC (split plane): 719.9,1305.1 709.36,1305.1 709.36,1347.29 676.7,1347.29 676.7,1305.1 675.1,1305.1 675.1,1349.9 719.9,1349.9
5V on L3_VCC (split plane): 45 vertices, not listed, extent 3110.09,20.1 4979.9,1909.91
3V3_ST_LINK on L3_VCC (split plane): 29 vertices, not listed, extent 3420.09,20.1 4564.91,949.91
1V8 on L3_VCC (split plane): 49 vertices, not listed, extent 620.09,1960.09 1244.91,2914.91
3V3 on L3_VCC (split plane): 719.9,1225.1 707.66,1225.1 707.66,1268.99 675.1,1268.99 675.1,1269.9 719.9,1269.9
3V3 on L3_VCC (split plane): 243 vertices, not listed, extent 20.1,20.1 4979.9,3444.46
POE1 on L5_GND (split plane): 49 vertices, not listed, extent 3380.09,2125.09 4574.91,3444.46
POE7 on L5_GND (split plane): 859.9,1225.1 855,1225.1 855,1268.99 822.34,1268.99 822.34,1225.1 815.1,1225.1 815.1,1269.9 859.9,1269.9
POE7 on L5_GND (split plane): 859.9,1348.99 827.34,1348.99 827.34,1305.1 815.1,1305.1 815.1,1349.9 859.9,1349.9
POE7 on L5_GND (split plane): 154 vertices, not listed, extent 20.1,20.1 4979.9,3444.46

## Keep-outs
Top Layer:
  circle w1: c4655,3080 r65
  circle w1: c4655,3080 r60
  circle w1: c440,390 r65
  circle w1: c440,390 r60
  circle w1: c395,3055 r60
  circle w1: c395,3055 r65
  circle w1: c4655,3080 r65
  circle w1: c4655,3080 r60
  circle w1: c440,390 r65
  circle w1: c440,390 r60
  circle w1: c395,3055 r60
  circle w1: c395,3055 r65
Bottom Layer:
  circle w1: c4655,3080 r60
  circle w1: c4655,3080 r65
  circle w1: c440,390 r60
  circle w1: c440,390 r65
  circle w1: c395,3055 r65
  circle w1: c395,3055 r60
  circle w1: c4655,3080 r60
  circle w1: c4655,3080 r65
  circle w1: c440,390 r60
  circle w1: c440,390 r65
  circle w1: c395,3055 r65
  circle w1: c395,3055 r60
Keep-Out Layer:
  lines w1: 0,0 3020.63,0 ; 0,0 0,3464.56 ; 0,0 0,3464.56 ; 0,0 3020.63,0 ; 0,0 0,3464.56 ; 0,0 3020.63,0 ; 0,0 0,3464.56 ; 0,0 3020.63,0 ; 0,0 3020.63,0 ; 0,0 0,3464.56 ; 0,0 3020.63,0 ; 0,0 0,3464.56 ; 0,0 3020.63,0 ; 0,0 0,3464.56 ; 0,0 0,3464.56 ; 0,0 3020.63,0 ; 0,3464.56 2360,3464.56 ; 0,3464.56 2360,3464.56 ; 0,3464.56 2360,3464.56 ; 0,3464.56 2360,3464.56 ; 0,3464.56 2360,3464.56 ; 0,3464.56 2360,3464.56 ; 0,3464.56 2360,3464.56 ; 0,3464.56 2360,3464.56 ; 2360,3464.56 ccw(c2587.5,4472.06) 2815,3464.56 ; 2360,3464.56 ccw(c2587.5,4472.06) 2815,3464.56 ; 2360,3464.56 ccw(c2587.5,4472.06) 2815,3464.56 ; 2360,3464.56 ccw(c2587.5,4472.06) 2815,3464.56 ; 2360,3464.56 ccw(c2587.5,4472.06) 2815,3464.56 ; 2360,3464.56 ccw(c2587.5,4472.06) 2815,3464.56 ; 2360,3464.56 ccw(c2587.5,4472.06) 2815,3464.56 ; 2360,3464.56 ccw(c2587.5,4472.06) 2815,3464.56 ; 2360,3464.56 ccw(c2587.5,4472.06) 2815,3464.56 ; 2360,3464.56 ccw(c2587.5,4472.06) 2815,3464.56 ; 2360,3464.56 ccw(c2587.5,4472.06) 2815,3464.56 ; 2360,3464.56 ccw(c2587.5,4472.06) 2815,3464.56 ; 2360,3464.56 ccw(c2587.5,4472.06) 2815,3464.56 ; 2360,3464.56 ccw(c2587.5,4472.06) 2815,3464.56 ; 2360,3464.56 ccw(c2587.5,4472.06) 2815,3464.56 ; 2360,3464.56 ccw(c2587.5,4472.06) 2815,3464.56 ; 2815,3464.56 5000,3464.56 ; 2815,3464.56 5000,3464.56 ; 2815,3464.56 5000,3464.56 ; 2815,3464.56 5000,3464.56 ; 2815,3464.56 5000,3464.56 ; 2815,3464.56 5000,3464.56 ; 2815,3464.56 5000,3464.56 ; 2815,3464.56 5000,3464.56 ; 3020.63,0 3020.63,70.28 ; 3020.63,0 3020.63,70.28 ; 3020.63,0 3020.63,70.28 ; 3020.63,0 3020.63,70.28 ; 3020.63,0 3020.63,70.28 ; 3020.63,0 3020.63,70.28 ; 3020.63,0 3020.63,70.28 ; 3020.63,0 3020.63,70.28 ; 3020.63,70.28 3024.57,74.22 ; 3020.63,70.28 3024.57,74.22 ; 3020.63,70.28 3024.57,74.22 ; 3020.63,70.28 3024.57,74.22 ; 3020.63,70.28 3024.57,74.22 ; 3020.63,70.28 3024.57,74.22 ; 3020.63,70.28 3024.57,74.22 ; 3020.63,70.28 3024.57,74.22 ; 3024.57,74.22 3050.16,74.22 ; 3024.57,74.22 3050.16,74.22 ; 3024.57,74.22 3050.16,74.22 ; 3024.57,74.22 3050.16,74.22 ; 3024.57,74.22 3050.16,74.22 ; 3024.57,74.22 3050.16,74.22 ; 3024.57,74.22 3050.16,74.22 ; 3024.57,74.22 3050.16,74.22 ; 3050.16,74.22 3054.1,70.28 ; 3050.16,74.22 3054.1,70.28 ; 3050.16,74.22 3054.1,70.28 ; 3050.16,74.22 3054.1,70.28 ; 3050.16,74.22 3054.1,70.28 ; 3050.16,74.22 3054.1,70.28 ; 3050.16,74.22 3054.1,70.28 ; 3050.16,74.22 3054.1,70.28 ; 3054.1,0 3207.64,0 ; 3054.1,0 3054.1,70.28 ; 3054.1,0 3054.1,70.28 ; 3054.1,0 3207.64,0 ; 3054.1,0 3054.1,70.28 ; 3054.1,0 3207.64,0 ; 3054.1,0 3054.1,70.28 ; 3054.1,0 3207.64,0 ; 3054.1,0 3207.64,0 ; 3054.1,0 3054.1,70.28 ; 3054.1,0 3207.64,0 ; 3054.1,0 3054.1,70.28 ; 3054.1,0 3207.64,0 ; 3054.1,0 3054.1,70.28 ; 3054.1,0 3054.1,70.28 ; 3054.1,0 3207.64,0 ; 3207.64,0 3207.64,70.28 ; 3207.64,0 3207.64,70.28 ; 3207.64,0 3207.64,70.28 ; 3207.64,0 3207.64,70.28 ; 3207.64,0 3207.64,70.28 ; 3207.64,0 3207.64,70.28 ; 3207.64,0 3207.64,70.28 ; 3207.64,0 3207.64,70.28 ; 3207.64,70.28 3211.58,74.22 ; 3207.64,70.28 3211.58,74.22 ; 3207.64,70.28 3211.58,74.22 ; 3207.64,70.28 3211.58,74.22 ; 3207.64,70.28 3211.58,74.22 ; 3207.64,70.28 3211.58,74.22 ; 3207.64,70.28 3211.58,74.22 ; 3207.64,70.28 3211.58,74.22 ; 3211.58,74.22 3237.17,74.22 ; 3211.58,74.22 3237.17,74.22 ; 3211.58,74.22 3237.17,74.22 ; 3211.58,74.22 3237.17,74.22 ; 3211.58,74.22 3237.17,74.22 ; 3211.58,74.22 3237.17,74.22 ; 3211.58,74.22 3237.17,74.22 ; 3211.58,74.22 3237.17,74.22 ; 3237.17,74.22 3241.11,70.28 ; 3237.17,74.22 3241.11,70.28 ; 3237.17,74.22 3241.11,70.28 ; 3237.17,74.22 3241.11,70.28 ; 3237.17,74.22 3241.11,70.28 ; 3237.17,74.22 3241.11,70.28 ; 3237.17,74.22 3241.11,70.28 ; 3237.17,74.22 3241.11,70.28 ; 3241.11,0 5000,0 ; 3241.11,0 3241.11,70.28 ; 3241.11,0 3241.11,70.28 ; 3241.11,0 5000,0 ; 3241.11,0 3241.11,70.28 ; 3241.11,0 5000,0 ; 3241.11,0 3241.11,70.28 ; 3241.11,0 5000,0 ; 3241.11,0 5000,0 ; 3241.11,0 3241.11,70.28 ; 3241.11,0 5000,0 ; 3241.11,0 3241.11,70.28 ; 3241.11,0 5000,0 ; 3241.11,0 3241.11,70.28 ; 3241.11,0 3241.11,70.28 ; 3241.11,0 5000,0 ; 4625,1705 4625,2255 ; 4625,1705 5000,1705 ; 4625,1705 5000,1705 ; 4625,1705 4625,2255 ; 4625,1705 5000,1705 ; 4625,1705 4625,2255 ; 4625,1705 5000,1705 ; 4625,1705 4625,2255 ; 4625,1705 4625,2255 ; 4625,1705 5000,1705 ; 4625,1705 4625,2255 ; 4625,1705 5000,1705 ; 4625,1705 4625,2255 ; 4625,1705 5000,1705 ; 4625,1705 5000,1705 ; 4625,1705 4625,2255 ; 4625,2255 5000,2255 ; 4625,2255 5000,2255 ; 4625,2255 5000,2255 ; 4625,2255 5000,2255 ; 4625,2255 5000,2255 ; 4625,2255 5000,2255 ; 4625,2255 5000,2255 ; 4625,2255 5000,2255 ; 5000,0 5000,1705 ; 5000,0 5000,1705 ; 5000,0 5000,1705 ; 5000,0 5000,1705 ; 5000,0 5000,1705 ; 5000,0 5000,1705 ; 5000,0 5000,1705 ; 5000,0 5000,1705 ; 4999.99,255 5000,255 ; 4999.99,255 5000,255 ; 4999.99,255 5000,255 ; 4999.99,255 5000,255 ; 4999.99,255 5000,255 ; 4999.99,255 5000,255 ; 4999.99,255 5000,255 ; 4999.99,255 5000,255 ; 5000,2255 5000,3464.56 ; 5000,2255 5000,3464.56 ; 5000,2255 5000,3464.56 ; 5000,2255 5000,3464.56 ; 5000,2255 5000,3464.56 ; 5000,2255 5000,3464.56 ; 5000,2255 5000,3464.56 ; 5000,2255 5000,3464.56
Multi-Layer:
  region: 3,1088 3,527 555,527 555,1088 3,1088
  region: 4025,2105 4025,1597 4273,1597 4273,2105 4025,2105

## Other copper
Top Layer:
  pour cut-out: 2290.95,2250.83 2289.93,2255.91 2287.06,2260.22 2282.75,2263.09 2277.67,2264.11 2272.59,2263.09 2268.28,2260.22 2265.41,2255.91 2264.39,2250.83 2265.41,2245.75 2268.28,2241.44 2272.59,2238.57 2277.67,2237.55 2282.75,2238.57 2287.06,2241.44 2289.93,2245.75 2290.95,2250.83
  pour cut-out: 2323.28,2251 2322.26,2256.08 2319.39,2260.39 2315.08,2263.26 2310,2264.28 2304.92,2263.26 2300.61,2260.39 2297.74,2256.08 2296.72,2251 2297.74,2245.92 2300.61,2241.61 2304.92,2238.74 2310,2237.72 2315.08,2238.74 2319.39,2241.61 2322.26,2245.92 2323.28,2251
  pour cut-out: 2294.33,2396 2293.09,2402.25 2289.55,2407.55 2284.25,2411.09 2278,2412.33 2271.75,2411.09 2266.45,2407.55 2262.91,2402.25 2261.67,2396 2262.91,2389.75 2266.45,2384.45 2271.75,2380.91 2278,2379.67 2284.25,2380.91 2289.55,2384.45 2293.09,2389.75 2294.33,2396
  pour cut-out: 2322.45,2219.34 2321.43,2224.42 2318.56,2228.73 2314.25,2231.6 2309.17,2232.62 2304.09,2231.6 2299.78,2228.73 2296.91,2224.42 2295.89,2219.34 2296.91,2214.26 2299.78,2209.95 2304.09,2207.08 2309.17,2206.06 2314.25,2207.08 2318.56,2209.95 2321.43,2214.26 2322.45,2219.34
  pour cut-out: 4646.52,458 4645.42,466.36 4642.19,474.15 4637.06,480.84 4630.37,485.97 4622.58,489.2 4614.22,490.3 4605.86,489.2 4598.07,485.97 4591.38,480.84 4586.25,474.15 4583.02,466.36 4581.92,458 4583.02,449.64 4586.25,441.85 4591.38,435.16 4598.07,430.03 4605.86,426.8 4614.22,425.7 4622.58,426.8 4630.37,430.03 4637.06,435.16 4642.19,441.85 4645.42,449.64 4646.52,458
  pour cut-out: 4546.52,458 4545.42,466.36 4542.19,474.15 4537.06,480.84 4530.37,485.97 4522.58,489.2 4514.22,490.3 4505.86,489.2 4498.07,485.97 4491.38,480.84 4486.25,474.15 4483.02,466.36 4481.92,458 4483.02,449.64 4486.25,441.85 4491.38,435.16 4498.07,430.03 4505.86,426.8 4514.22,425.7 4522.58,426.8 4530.37,430.03 4537.06,435.16 4542.19,441.85 4545.42,449.64 4546.52,458
  pour cut-out: 4846.52,458 4845.42,466.36 4842.19,474.15 4837.06,480.84 4830.37,485.97 4822.58,489.2 4814.22,490.3 4805.86,489.2 4798.07,485.97 4791.38,480.84 4786.25,474.15 4783.02,466.36 4781.92,458 4783.02,449.64 4786.25,441.85 4791.38,435.16 4798.07,430.03 4805.86,426.8 4814.22,425.7 4822.58,426.8 4830.37,430.03 4837.06,435.16 4842.19,441.85 4845.42,449.64 4846.52,458
  pour cut-out: 4746.52,458 4745.42,466.36 4742.19,474.15 4737.06,480.84 4730.37,485.97 4722.58,489.2 4714.22,490.3 4705.86,489.2 4698.07,485.97 4691.38,480.84 4686.25,474.15 4683.02,466.36 4681.92,458 4683.02,449.64 4686.25,441.85 4691.38,435.16 4698.07,430.03 4705.86,426.8 4714.22,425.7 4722.58,426.8 4730.37,430.03 4737.06,435.16 4742.19,441.85 4745.42,449.64 4746.52,458
  pour cut-out: 4946.52,458 4945.42,466.36 4942.19,474.15 4937.06,480.84 4930.37,485.97 4922.58,489.2 4914.22,490.3 4905.86,489.2 4898.07,485.97 4891.38,480.84 4886.25,474.15 4883.02,466.36 4881.92,458 4883.02,449.64 4886.25,441.85 4891.38,435.16 4898.07,430.03 4905.86,426.8 4914.22,425.7 4922.58,426.8 4930.37,430.03 4937.06,435.16 4942.19,441.85 4945.42,449.64 4946.52,458
  text "1" at 541.7,1308.3 h34
  text "1" at 541.7,1308.3 h34
  text "B" at 540,1230 h34
  text "B" at 540,1230 h34
L4_SIG:
  text "4" at 785,1310 h34
  text "4" at 785,1310 h34
  text "B" at 785,1230 h34
  text "B" at 785,1230 h34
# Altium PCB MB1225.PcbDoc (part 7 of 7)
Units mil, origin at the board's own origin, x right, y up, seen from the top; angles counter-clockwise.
Board outline 5000 x 3464.56 mil, 6 copper layers (Top Layer, L2_GND, L3_VCC, L4_SIG, L5_GND, Bottom Layer), stack 62.2 mil thick; 453 components, 378 nets, 1982 pads, 949 vias.

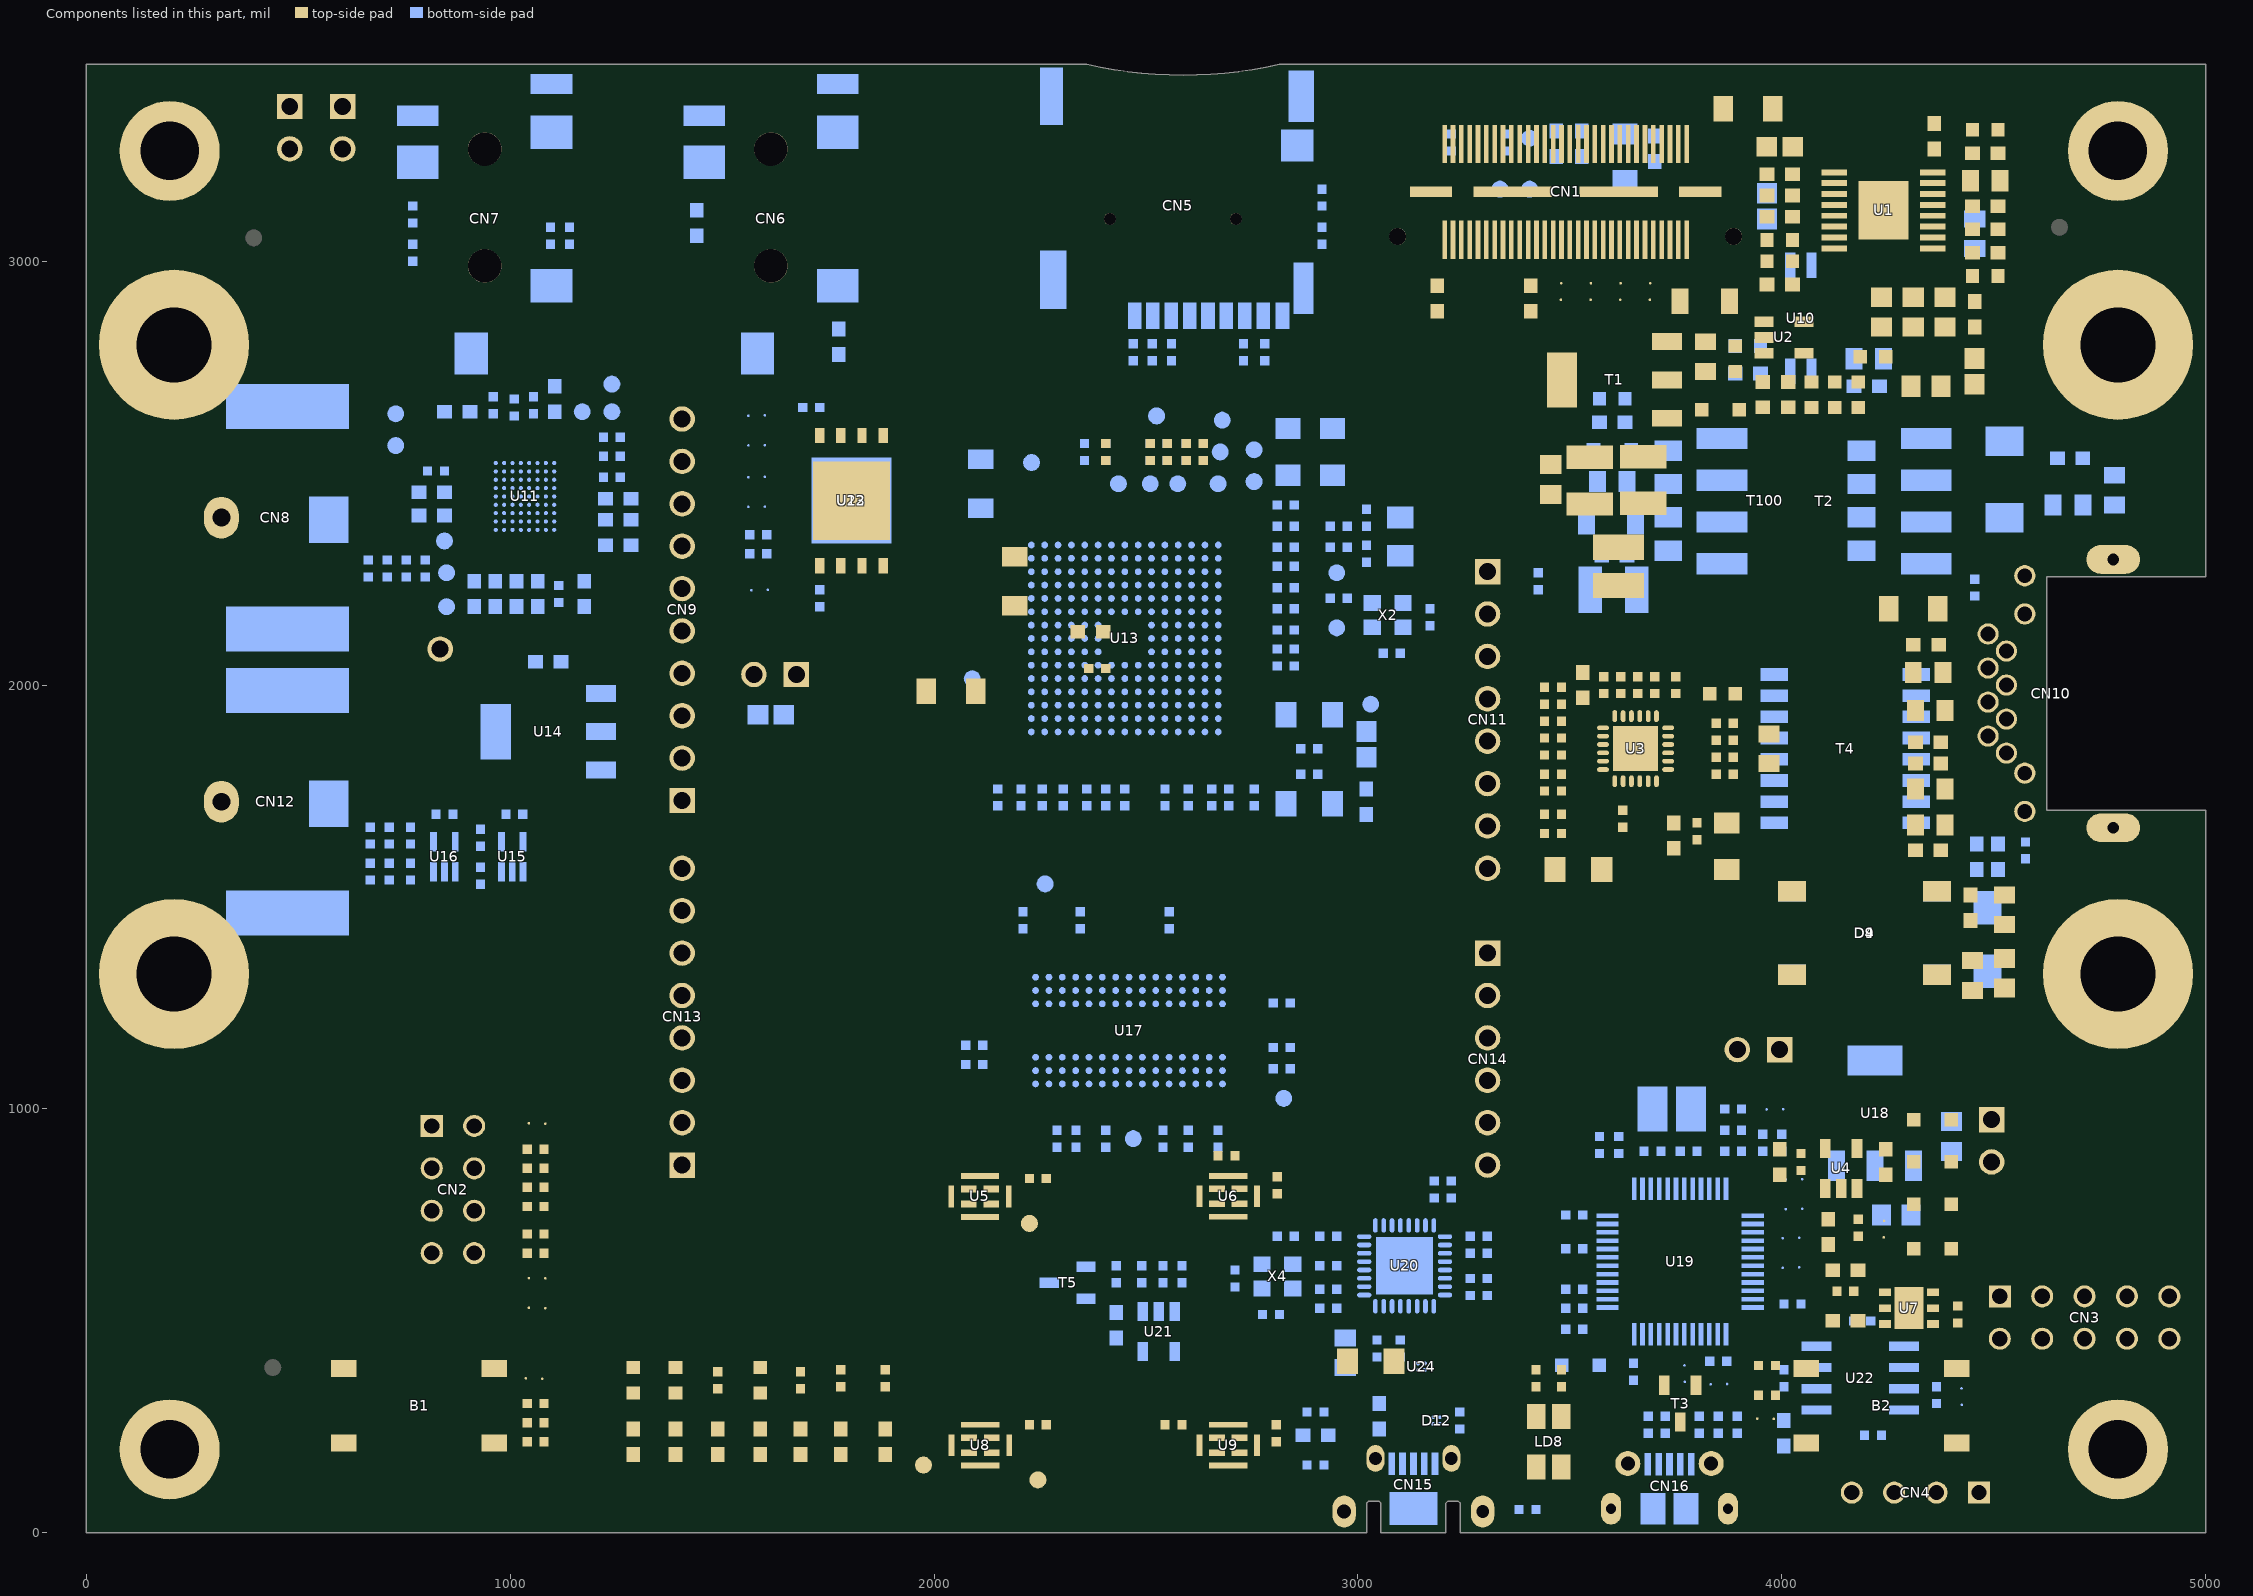
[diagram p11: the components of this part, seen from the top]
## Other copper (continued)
Bottom Layer:
  pour cut-out: 4531.33,875 4530.09,884.4 4526.46,893.17 4520.69,900.69 4513.17,906.46 4504.4,910.09 4495,911.33 4485.6,910.09 4476.83,906.46 4469.31,900.69 4463.54,893.17 4459.91,884.4 4458.67,875 4459.91,865.6 4463.54,856.83 4469.31,849.31 4476.83,843.54 4485.6,839.91 4495,838.67 4504.4,839.91 4513.17,843.54 4520.69,849.31 4526.46,856.83 4530.09,865.6 4531.33,875
  pour cut-out: 3939.33,3270 3938.09,3276.25 3934.55,3281.55 3929.25,3285.09 3923,3286.33 3916.75,3285.09 3911.45,3281.55 3907.91,3276.25 3906.67,3270 3907.91,3263.75 3911.45,3258.45 3916.75,3254.91 3923,3253.67 3929.25,3254.91 3934.55,3258.45 3938.09,3263.75 3939.33,3270
  pour cut-out: 4116.33,3250 4115.09,3256.25 4111.55,3261.55 4106.25,3265.09 4100,3266.33 4093.75,3265.09 4088.45,3261.55 4084.91,3256.25 4083.67,3250 4084.91,3243.75 4088.45,3238.45 4093.75,3234.91 4100,3233.67 4106.25,3234.91 4111.55,3238.45 4115.09,3243.75 4116.33,3250
  pour cut-out: 4086.33,3205 4085.09,3211.25 4081.55,3216.55 4076.25,3220.09 4070,3221.33 4063.75,3220.09 4058.45,3216.55 4054.91,3211.25 4053.67,3205 4054.91,3198.75 4058.45,3193.45 4063.75,3189.91 4070,3188.67 4076.25,3189.91 4081.55,3193.45 4085.09,3198.75 4086.33,3205
  pour cut-out: 4336.33,3265 4335.09,3271.25 4331.55,3276.55 4326.25,3280.09 4320,3281.33 4313.75,3280.09 4308.45,3276.55 4304.91,3271.25 4303.67,3265 4304.91,3258.75 4308.45,3253.45 4313.75,3249.91 4320,3248.67 4326.25,3249.91 4331.55,3253.45 4335.09,3258.75 4336.33,3265
  pour cut-out: 4571.33,3130 4570.09,3136.25 4566.55,3141.55 4561.25,3145.09 4555,3146.33 4548.75,3145.09 4543.45,3141.55 4539.91,3136.25 4538.67,3130 4539.91,3123.75 4543.45,3118.45 4548.75,3114.91 4555,3113.67 4561.25,3114.91 4566.55,3118.45 4570.09,3123.75 4571.33,3130
  pour cut-out: 4571.33,3190 4570.09,3196.25 4566.55,3201.55 4561.25,3205.09 4555,3206.33 4548.75,3205.09 4543.45,3201.55 4539.91,3196.25 4538.67,3190 4539.91,3183.75 4543.45,3178.45 4548.75,3174.91 4555,3173.67 4561.25,3174.91 4566.55,3178.45 4570.09,3183.75 4571.33,3190
  pour cut-out: 4571.33,3255 4570.09,3261.25 4566.55,3266.55 4561.25,3270.09 4555,3271.33 4548.75,3270.09 4543.45,3266.55 4539.91,3261.25 4538.67,3255 4539.91,3248.75 4543.45,3243.45 4548.75,3239.91 4555,3238.67 4561.25,3239.91 4566.55,3243.45 4570.09,3248.75 4571.33,3255
  pour cut-out: 4196.33,660 4195.09,666.25 4191.55,671.55 4186.25,675.09 4180,676.33 4173.75,675.09 4168.45,671.55 4164.91,666.25 4163.67,660 4164.91,653.75 4168.45,648.45 4173.75,644.91 4180,643.67 4186.25,644.91 4191.55,648.45 4195.09,653.75 4196.33,660
  pour cut-out: 4161.33,770 4160.09,776.25 4156.55,781.55 4151.25,785.09 4145,786.33 4138.75,785.09 4133.45,781.55 4129.91,776.25 4128.67,770 4129.91,763.75 4133.45,758.45 4138.75,754.91 4145,753.67 4151.25,754.91 4156.55,758.45 4160.09,763.75 4161.33,770
  text "6" at 925,1310 h34
  text "6" at 925,1310 h34
  text "B" at 920,1230 h34
  text "B" at 920,1230 h34
L2_GND (plane layer: these items are gaps in the copper):
  region: 4024.98,2105 4024.98,1595 4273,1595 4273,2105
  region: 591,1300.04 591,1276.1 663.94,1276.1 663.94,1300.04
  region: 450.03,1360.01 450.03,1215.02 601.35,1215.02 601.35,1360.01
  region: 655.62,1360.01 655.62,1215.02 1013.38,1215.02 1013.38,1360.01
  region: 0,1088 0,527 555,527 555,1088
  pour cut-out: 2741.52,3099.56 2740.52,3107.14 2737.6,3114.2 2732.94,3120.26 2726.88,3124.92 2719.82,3127.84 2712.24,3128.84 2704.66,3127.84 2697.6,3124.92 2691.54,3120.26 2686.88,3114.2 2683.96,3107.14 2682.96,3099.56 2683.96,3091.98 2686.88,3084.92 2691.54,3078.86 2697.6,3074.2 2704.66,3071.28 2712.24,3070.28 2719.82,3071.28 2726.88,3074.2 2732.94,3078.86 2737.6,3084.92 2740.52,3091.98 2741.52,3099.56
  pour cut-out: 2444.28,3099.56 2443.28,3107.14 2440.36,3114.2 2435.7,3120.26 2429.64,3124.92 2422.58,3127.84 2415,3128.84 2407.42,3127.84 2400.36,3124.92 2394.3,3120.26 2389.64,3114.2 2386.72,3107.14 2385.72,3099.56 2386.72,3091.98 2389.64,3084.92 2394.3,3078.86 2400.36,3074.2 2407.42,3071.28 2415,3070.28 2422.58,3071.28 2429.64,3074.2 2435.7,3078.86 2440.36,3084.92 2443.28,3091.98 2444.28,3099.56
  pour cut-out: 1669.83,3264.56 1667.96,3278.75 1662.48,3291.97 1653.77,3303.33 1642.41,3312.04 1629.19,3317.52 1615,3319.39 1600.81,3317.52 1587.59,3312.04 1576.23,3303.33 1567.52,3291.97 1562.04,3278.75 1560.17,3264.56 1562.04,3250.37 1567.52,3237.15 1576.23,3225.79 1587.59,3217.08 1600.81,3211.6 1615,3209.73 1629.19,3211.6 1642.41,3217.08 1653.77,3225.79 1662.48,3237.15 1667.96,3250.37 1669.83,3264.56
  pour cut-out: 994.83,3264.56 992.96,3278.75 987.48,3291.97 978.77,3303.33 967.41,3312.04 954.19,3317.52 940,3319.39 925.81,3317.52 912.59,3312.04 901.23,3303.33 892.52,3291.97 887.04,3278.75 885.17,3264.56 887.04,3250.37 892.52,3237.15 901.23,3225.79 912.59,3217.08 925.81,3211.6 940,3209.73 954.19,3211.6 967.41,3217.08 978.77,3225.79 987.48,3237.15 992.96,3250.37 994.83,3264.56
  pour cut-out: 994.83,2988.97 992.96,3003.16 987.48,3016.38 978.77,3027.74 967.41,3036.45 954.19,3041.93 940,3043.8 925.81,3041.93 912.59,3036.45 901.23,3027.74 892.52,3016.38 887.04,3003.16 885.17,2988.97 887.04,2974.78 892.52,2961.56 901.23,2950.2 912.59,2941.49 925.81,2936.01 940,2934.14 954.19,2936.01 967.41,2941.49 978.77,2950.2 987.48,2961.56 992.96,2974.78 994.83,2988.97
  pour cut-out: 1669.83,2988.97 1667.96,3003.16 1662.48,3016.38 1653.77,3027.74 1642.41,3036.45 1629.19,3041.93 1615,3043.8 1600.81,3041.93 1587.59,3036.45 1576.23,3027.74 1567.52,3016.38 1562.04,3003.16 1560.17,2988.97 1562.04,2974.78 1567.52,2961.56 1576.23,2950.2 1587.59,2941.49 1600.81,2936.01 1615,2934.14 1629.19,2936.01 1642.41,2941.49 1653.77,2950.2 1662.48,2961.56 1667.96,2974.78 1669.83,2988.97
  pour cut-out: 3129.5,3058.42 3128.28,3067.68 3124.7,3076.3 3119.02,3083.71 3111.61,3089.39 3102.99,3092.97 3093.73,3094.19 3084.47,3092.97 3075.85,3089.39 3068.44,3083.71 3062.76,3076.3 3059.18,3067.68 3057.96,3058.42 3059.18,3049.16 3062.76,3040.54 3068.44,3033.13 3075.85,3027.45 3084.47,3023.87 3093.73,3022.65 3102.99,3023.87 3111.61,3027.45 3119.02,3033.13 3124.7,3040.54 3128.28,3049.16 3129.5,3058.42
  lines w10: 600,1220 600,1275 655,1275 655,1220 600,1220 ; 600,1300 600,1355 655,1355 655,1300 600,1300
  lines w20: 3895,3495 3895,3090 3765,2960 3745,2960 3726,2941 3726,2881 3670,2825 3440,2825 3370,2755 3370,2400 3496,2274 3496,2204 3585,2115 3955,2115 4005,2165 4005,2850 4155,3000 4375,3000 4440,2935 4560,2935 4585,2960 4585,3490
  text "2" at 611.7,1308.3 h34
  text "2" at 611.7,1308.3 h34
  text "B" at 610,1230 h34
  text "B" at 610,1230 h34
  text "'.Layer_Name'" at 866,-1088 h118.11
  text ".G2" at 2504,-1091 h118.11
L3_VCC (plane layer: these items are gaps in the copper):
  region: 4024.98,2105 4024.98,1595 4273,1595 4273,2105
  region: 725,1360.01 725,1215.02 1013.38,1215.02 1013.38,1360.01
  region: 450.03,1360.01 450.03,1215.02 672.87,1215.02 672.87,1360.01
  region: 668.05,1300.04 668.05,1276.1 730,1276.1 730,1300.04
  region: 0,1088 0,527 555,527 555,1088
  region: 4665.3,1442.97 cw(c4893.73,1167.88) 4723.36,1482.25 cw(c4824.17,1131.49) 4793.75,1495.18 cw(c4749.59,1098.97) 4870.22,1478.95 cw(c4716.26,1170.91) 4927.38,1442.97 4825.57,1442.97
  pour cut-out: 3922.03,3058.42 3920.81,3067.68 3917.23,3076.31 3911.55,3083.72 3904.14,3089.4 3895.51,3092.98 3886.25,3094.2 3876.99,3092.98 3868.36,3089.4 3860.95,3083.72 3855.27,3076.31 3851.69,3067.68 3850.47,3058.42 3851.69,3049.16 3855.27,3040.53 3860.95,3033.12 3868.36,3027.44 3876.99,3023.86 3886.25,3022.64 3895.51,3023.86 3904.14,3027.44 3911.55,3033.12 3917.23,3040.53 3920.81,3049.16 3922.03,3058.42
  pour cut-out: 3129.51,3058.42 3128.29,3067.68 3124.71,3076.31 3119.03,3083.72 3111.62,3089.4 3102.99,3092.98 3093.73,3094.2 3084.47,3092.98 3075.84,3089.4 3068.43,3083.72 3062.75,3076.31 3059.17,3067.68 3057.95,3058.42 3059.17,3049.16 3062.75,3040.53 3068.43,3033.12 3075.84,3027.44 3084.47,3023.86 3093.73,3022.64 3102.99,3023.86 3111.62,3027.44 3119.03,3033.12 3124.71,3040.53 3128.29,3049.16 3129.51,3058.42
  pour cut-out: 1669.84,2988.97 1667.97,3003.16 1662.49,3016.39 1653.78,3027.75 1642.42,3036.46 1629.19,3041.94 1615,3043.81 1600.81,3041.94 1587.58,3036.46 1576.22,3027.75 1567.51,3016.39 1562.03,3003.16 1560.16,2988.97 1562.03,2974.78 1567.51,2961.55 1576.22,2950.19 1587.58,2941.48 1600.81,2936 1615,2934.13 1629.19,2936 1642.42,2941.48 1653.78,2950.19 1662.49,2961.55 1667.97,2974.78 1669.84,2988.97
  pour cut-out: 994.83,3264.56 992.96,3278.75 987.48,3291.97 978.77,3303.33 967.41,3312.04 954.19,3317.52 940,3319.39 925.81,3317.52 912.59,3312.04 901.23,3303.33 892.52,3291.97 887.04,3278.75 885.17,3264.56 887.04,3250.37 892.52,3237.15 901.23,3225.79 912.59,3217.08 925.81,3211.6 940,3209.73 954.19,3211.6 967.41,3217.08 978.77,3225.79 987.48,3237.15 992.96,3250.37 994.83,3264.56
  pour cut-out: 1669.83,3264.56 1667.96,3278.75 1662.48,3291.97 1653.77,3303.33 1642.41,3312.04 1629.19,3317.52 1615,3319.39 1600.81,3317.52 1587.59,3312.04 1576.23,3303.33 1567.52,3291.97 1562.04,3278.75 1560.17,3264.56 1562.04,3250.37 1567.52,3237.15 1576.23,3225.79 1587.59,3217.08 1600.81,3211.6 1615,3209.73 1629.19,3211.6 1642.41,3217.08 1653.77,3225.79 1662.48,3237.15 1667.96,3250.37 1669.83,3264.56
  pour cut-out: 2444.28,3099.56 2443.28,3107.14 2440.36,3114.2 2435.7,3120.26 2429.64,3124.92 2422.58,3127.84 2415,3128.84 2407.42,3127.84 2400.36,3124.92 2394.3,3120.26 2389.64,3114.2 2386.72,3107.14 2385.72,3099.56 2386.72,3091.98 2389.64,3084.92 2394.3,3078.86 2400.36,3074.2 2407.42,3071.28 2415,3070.28 2422.58,3071.28 2429.64,3074.2 2435.7,3078.86 2440.36,3084.92 2443.28,3091.98 2444.28,3099.56
  pour cut-out: 2741.52,3099.56 2740.52,3107.14 2737.6,3114.2 2732.94,3120.26 2726.88,3124.92 2719.82,3127.84 2712.24,3128.84 2704.66,3127.84 2697.6,3124.92 2691.54,3120.26 2686.88,3114.2 2683.96,3107.14 2682.96,3099.56 2683.96,3091.98 2686.88,3084.92 2691.54,3078.86 2697.6,3074.2 2704.66,3071.28 2712.24,3070.28 2719.82,3071.28 2726.88,3074.2 2732.94,3078.86 2737.6,3084.92 2740.52,3091.98 2741.52,3099.56
  lines w10: 4665.29,1442.47 cw(c4792.99,1318.43) 4922.21,1440.89 ; 4979.96,1690.41 4610.41,1690.41 4610.41,2269.59 4979.96,2269.59 ; 670,1220 670,1275 725,1275 725,1220 670,1220 ; 670,1300 670,1355 725,1355 725,1300 670,1300
  lines w20: 3095,1600 1670,1600 1620,1650 1620,2060 1645,2085 1700,2085 1745,2130 1745,2510 1805,2570 3025,2570 3040,2555 3040,2460 3020,2440 2855,2440 2835,2420 2835,2055 2860,2030 3055,2030 3100,1985 3100,1920 ; 3410,-135 3410,925 3445,960 3970,960 4010,920 4010,485 3995,470 3920,470 3895,445 3895,325 3935,285 4500,285 4575,210 4575,-55 ; 4170,285 4170,565 4195,590 4300,590 4320,610 4320,1050 4215,1155 3150,1155 3100,1205 3100,1920 ; 5045,1440 3470,1440 3415,1495 3415,1895 3390,1920 3100,1920 ; 610,2020 680,1950 1215,1950 1255,1990 1255,2225 1235,2245 1065,2245 1045,2265 1045,2385 1025,2405 890,2405 860,2435 860,2745 880,2765 1035,2765 1050,2750 1050,2590 1070,2570 1230,2570 1250,2590 1250,2895 1220,2925 695,2925 640,2925 610,2895 610,2020
  text "3" at 681.7,1308.3 h34
  text "3" at 681.7,1308.3 h34
  text "B" at 680,1230 h34
  text "B" at 680,1230 h34
  text ".G3" at 2509,-1087 h118.11
  text "'.Layer_Name'" at 866,-1089 h118.11
L5_GND (plane layer: these items are gaps in the copper):
  region: 4024.98,2105 4024.98,1595 4273,1595 4273,2105
  region: 865,1360.01 865,1215.02 1013.38,1215.02 1013.38,1360.01
  region: 450.03,1360.01 450.03,1215.02 812,1215.02 812,1360.01
  region: 810,1300.04 810,1276.1 870,1276.1 870,1300.04
  region: 0,1088 0,527 555,527 555,1088
  pour cut-out: 2741.52,3099.56 2740.52,3107.14 2737.6,3114.2 2732.94,3120.26 2726.88,3124.92 2719.82,3127.84 2712.24,3128.84 2704.66,3127.84 2697.6,3124.92 2691.54,3120.26 2686.88,3114.2 2683.96,3107.14 2682.96,3099.56 2683.96,3091.98 2686.88,3084.92 2691.54,3078.86 2697.6,3074.2 2704.66,3071.28 2712.24,3070.28 2719.82,3071.28 2726.88,3074.2 2732.94,3078.86 2737.6,3084.92 2740.52,3091.98 2741.52,3099.56
  pour cut-out: 2444.28,3099.56 2443.28,3107.14 2440.36,3114.2 2435.7,3120.26 2429.64,3124.92 2422.58,3127.84 2415,3128.84 2407.42,3127.84 2400.36,3124.92 2394.3,3120.26 2389.64,3114.2 2386.72,3107.14 2385.72,3099.56 2386.72,3091.98 2389.64,3084.92 2394.3,3078.86 2400.36,3074.2 2407.42,3071.28 2415,3070.28 2422.58,3071.28 2429.64,3074.2 2435.7,3078.86 2440.36,3084.92 2443.28,3091.98 2444.28,3099.56
  pour cut-out: 1669.83,3264.56 1667.96,3278.75 1662.48,3291.97 1653.77,3303.33 1642.41,3312.04 1629.19,3317.52 1615,3319.39 1600.81,3317.52 1587.59,3312.04 1576.23,3303.33 1567.52,3291.97 1562.04,3278.75 1560.17,3264.56 1562.04,3250.37 1567.52,3237.15 1576.23,3225.79 1587.59,3217.08 1600.81,3211.6 1615,3209.73 1629.19,3211.6 1642.41,3217.08 1653.77,3225.79 1662.48,3237.15 1667.96,3250.37 1669.83,3264.56
  pour cut-out: 994.83,3264.56 992.96,3278.75 987.48,3291.97 978.77,3303.33 967.41,3312.04 954.19,3317.52 940,3319.39 925.81,3317.52 912.59,3312.04 901.23,3303.33 892.52,3291.97 887.04,3278.75 885.17,3264.56 887.04,3250.37 892.52,3237.15 901.23,3225.79 912.59,3217.08 925.81,3211.6 940,3209.73 954.19,3211.6 967.41,3217.08 978.77,3225.79 987.48,3237.15 992.96,3250.37 994.83,3264.56
  pour cut-out: 994.83,2988.97 992.96,3003.16 987.48,3016.38 978.77,3027.74 967.41,3036.45 954.19,3041.93 940,3043.8 925.81,3041.93 912.59,3036.45 901.23,3027.74 892.52,3016.38 887.04,3003.16 885.17,2988.97 887.04,2974.78 892.52,2961.56 901.23,2950.2 912.59,2941.49 925.81,2936.01 940,2934.14 954.19,2936.01 967.41,2941.49 978.77,2950.2 987.48,2961.56 992.96,2974.78 994.83,2988.97
  pour cut-out: 1669.83,2988.97 1667.96,3003.16 1662.48,3016.38 1653.77,3027.74 1642.41,3036.45 1629.19,3041.93 1615,3043.8 1600.81,3041.93 1587.59,3036.45 1576.23,3027.74 1567.52,3016.38 1562.04,3003.16 1560.17,2988.97 1562.04,2974.78 1567.52,2961.56 1576.23,2950.2 1587.59,2941.49 1600.81,2936.01 1615,2934.14 1629.19,2936.01 1642.41,2941.49 1653.77,2950.2 1662.48,2961.56 1667.96,2974.78 1669.83,2988.97
  pour cut-out: 3129.5,3058.42 3128.28,3067.68 3124.7,3076.3 3119.02,3083.71 3111.61,3089.39 3102.99,3092.97 3093.73,3094.19 3084.47,3092.97 3075.85,3089.39 3068.44,3083.71 3062.76,3076.3 3059.18,3067.68 3057.96,3058.42 3059.18,3049.16 3062.76,3040.54 3068.44,3033.13 3075.85,3027.45 3084.47,3023.87 3093.73,3022.65 3102.99,3023.87 3111.61,3027.45 3119.02,3033.13 3124.7,3040.54 3128.28,3049.16 3129.5,3058.42
  lines w10: 810,1220 865,1220 865,1275 810,1275 810,1220 ; 810,1300 865,1300 865,1355 810,1355 810,1300
  lines w20: 3895,3495 3895,3090 3765,2960 3745,2960 3726,2941 3726,2881 3670,2825 3440,2825 3370,2755 3370,2400 3496,2274 3496,2204 3585,2115 3955,2115 4005,2165 4005,2850 4155,3000 4375,3000 4440,2935 4560,2935 4585,2960 4585,3490
  text "5" at 855,1310 h34
  text "5" at 855,1310 h34
  text "B" at 850,1230 h34
  text "B" at 850,1230 h34
  text ".G5" at 2507,-1085 h118.11
  text "'.Layer_Name'" at 865,-1088 h118.11

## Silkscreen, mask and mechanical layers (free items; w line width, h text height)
Top Overlay:
  drawing of 5985 lines, arcs and shapes, not listed
  text "A" at 4545,3355 h40
  text "spk L" at 705,3228 h40 r90
  text "spk R" at 401,3224 h40 r90
  text "uSD" at 2598,3219 h34
  text "CN5" at 2437,3216 h34
  text "JP3" at 421,3161 h34
  text "JP2" at 547,3161 h34
  text "DSI LCD" at 2960,3140 h34 r90
  text "CN7" at 963,3089 h34 r90
  text "CN6" at 1606,3088 h34 r90
  text "Line Out" at 1029.42,3056 h34 r90
  text "Line In" at 1708,3056 h34 r90
  text "CN10" at 4727,2431 h34
  text "Ethernet" at 4691,2377 h34
  text "CN8" at 102,2376 h34
  text "SPDIF TX" at 22,2279 h34
  text "CN12" at 113,1687 h34
  text "SPDIF RX" at 23,1614 h34
  text "A" at 3860,1345 h40
  text "S" at 465,1309 h34
  text "B" at 465.7,1228.3 h34
  text "Wifi or I2C ext" at 559,1119 h34
  text "Ext 5V" at 4641,1089 h34
  text "T.R" at 2830,875 h34
  text "T.L" at 2082.86,870 h34
  text "CN3" at 4833.06,629.64 h34
  text "I" at 3580,550 h500
  text "G" at 2797,535 h400
  text "H" at 3155,503 h600
  text "MB1225C" at 2224,498 h100
  text "STM32F769I-DISCO" at 2015,379 h100
  text "S" at 3168,325 h300
  text "B.L" at 2081.77,295 h34
  text "B.R" at 2660.33,295 h34
  text "reset" at 4493,197 h34
  text "CN16" at 3695,131 h30
  text "user" at 710,115 h34
  text "USB HS" at 3036,98 h34
  text "USB" at 3697,90 h30
  text "COM" at 3396,64 h34
  text "ST_LINK" at 3650,41 h30
  text "CN15" at 3060,33 h34
  text "PWR" at 1760,15 h34 r90
  text "Fault" at 1851,11 h34 r90
  text "usr1" at 1244,10 h34 r90
  text "usr2" at 1345,5 h34 r90
  text "usr3" at 1450,5 h34 r90
  text "OC" at 1560,5 h34 r90
  text "VBUS" at 1655,5 h34 r90
  text "DIO" at 4090,5 h34
  text "GND" at 4210,5 h34
  text "CLK" at 4325,5 h34
  text "3V3" at 4440,5 h34
Bottom Overlay:
  drawing of 328 lines, arcs and shapes, not listed
  text "uSD" at 2215,3425 h34 r90
  text "Line In" at 1881,3225 h34 r270
  text "Line Out" at 1200,3185 h34 r270
  text "spk L" at 603,2963 h40 r270
  text "spk R" at 489,2960 h40 r270
  text "D15" at 1525,2635 h30
  text "D14" at 1525,2525 h30
  text "AVDD" at 1515,2375 h30 r315
  text "GND" at 1530,2325 h30
  text "Ethernet" at 4667,2310 h34
  text "nc" at 3405,2240 h30
  text "D13" at 1530,2205 h30
  text "IOREF5" at 3505,2150 h30
  text "SPDIF TX" at 264,2110 h34
  text "D12" at 1525,2105 h30
  text "Idd" at 1742,2090 h34
  text "NRST" at 3455,2045 h30
  text "D11" at 1525,2010 h30
  text "SPDIF RX" at 264,1970 h34
  text "3V3" at 3430,1960 h30
  text "D10" at 1525,1905 h30
  text "5V" at 3410,1845 h30
  text "D9" at 1505,1810 h30
  text "GND" at 3435,1750 h30
  text "D8" at 1505,1715 h30
  text "GND" at 3430,1670 h30
  text "VIN" at 3435,1550 h30
  text "D7" at 1515,1545 h30
  text "D6" at 1515,1445 h30
  text "D5" at 1515,1355 h30
  text "A0" at 3425,1350 h30
  text "B" at 993,1309 h34
  text "A1" at 3425,1260 h30
  text "D4" at 1515,1255 h30
  text "B" at 993,1229 h34
  text "VCP_TX" at 3855,1205 h34 r270
  text "VCP_RX" at 3940,1200 h34 r270
  text "D3" at 1515,1150 h30
  text "A2" at 3425,1150 h30
  text "A3" at 3425,1055 h30
  text "D2" at 1515,1050 h30
  text "JP1" at 4954,976 h34
  text "D1" at 1515,955 h30
  text "A4" at 3425,955 h30
  text "CN2" at 733,943 h34
  text "Ext 5V" at 4970,894 h34
  text "Wifi or I2C ext" at 733,871 h34
  text "D0" at 1515,850 h30
  text "A5" at 3425,850 h30
  text "stlk" at 4503,649 h34 r270
  text "chgr" at 4896,633 h34 r270
  text "usbhs" at 4593,630 h34 r270
  text "poe5V" at 4793,630 h34 r270
  text "ext5V" at 4698,627 h34 r270
  text "5V" at 4942,347 h34
  text "USB HS" at 2900,25 h34
  text "USB ST_LINK" at 4246,22 h34
M1-Board Shape:
  lines w10: 0,3464.56 0,0 3020,0 3020,69.65 3024.57,74.22 3050.16,74.22 3052.13,72.25 3052.13,37.11 3052.13,1.97 3054.1,0 3107,0 3207.64,0 3207.64,70.28 3209.61,72.25 3222.41,72.25 3238.51,72.25 3241.11,69.65 3241.11,0 4998,0 4998,1705 4625,1705 4625,2255 5000,2255 5000,3463 2816.58,3463 cw(c2591.86,4511.45) 2359.98,3464.56 ; 0,3465 2359.54,3465
Mechanical 1:
  lines w1: 950,2350 1120,2350 1120,2540 950,2540 950,2350 ; 2186,1015 2735,1015 2735,1362 2186,1362 2186,1015 ; 2191,1846 2709,1846 2709,2364 2191,2364 2191,1846 ; 4396.96,285.31 4452.81,285.31 4452.81,374.85 4396.96,374.85 4396.96,285.31
DIMENSION:
  drawing of 420 lines, arcs and shapes, not listed
  text "59" at 3220,3348.58 h25
  text "2" at 3785,2953.58 h25
  text "60" at 3225,2943.58 h25
  text "50" at 3320,2943.58 h25
  text "40" at 3420,2943.58 h25
  text "30" at 3520,2943.58 h25
  text "20" at 3620,2943.58 h25
  text "10" at 3715,2943.58 h25
BOARD_GEOMETRY_OUT:
  drawing of 22 lines, arcs and shapes, not listed
PIN_TOP:
  circle w1: c4065.98,760 r30
  circle w1: c4130.98,1435 r30
  circle w1: c3745.98,1435 r30
  circle w1: c600,2215 r30
  circle w1: c4515,2255.98 r30
  circle w1: c207,205.83 r177
  circle w1: c4792.99,205.83 r177
  circle w1: c207,1690.24 r177
  circle w1: c4792.99,1690.24 r177
  circle w1: c3853.78,2130.9 r20
  circle w1: c3126.22,2130.9 r20
Drill Drawing:
  drawing of 1334 lines, arcs and shapes, not listed
  text "5" at 689,9177 h100
  text "IMPEDANCE TABLE" at 910,9140 h100
  text "IMPEDANCE TABLE" at 910,9140 h100
  text "LAYER" at 835,8846 h75
  text "LAYER" at 835,8846 h75
  text "TOLERANCE" at 4585,8846 h75
  text "TOLERANCE" at 4585,8846 h75
  text "TRACE" at 1585,8836 h75
  text "TRACE" at 1585,8836 h75
  text "SPACEING" at 2135,8836 h75
  text "SPACEING" at 2135,8836 h75
  text "IMPEDANCE" at 2885,8836 h75
  text "IMPEDANCE" at 2885,8836 h75
  text "IMPEDANCE" at 3785,8836 h75
  text "IMPEDANCE" at 3785,8836 h75
  text "(mil)" at 1635,8746 h50
  text "(mil)" at 1635,8746 h50
  text "(Single end)" at 2935,8746 h50
  text "(Single end)" at 2935,8746 h50
  text "(mil)" at 2235,8736 h50
  text "(mil)" at 2235,8736 h50
  text "(Differential)" at 3785,8736 h50
  text "(Differential)" at 3785,8736 h50
  text "4" at 6920,8610 h75
  text "4" at 6920,8610 h75
  text "LAYER STUCK-UP" at 7120,8610 h75
  text "LAYER STUCK-UP" at 7120,8610 h75
  text "1,6" at 830,8600 h75
  text "1,6" at 830,8600 h75
  text "5.0" at 1630,8590 h75
  text "5.0" at 1630,8590 h75
  text "N/A" at 2285,8536 h75
  text "N/A" at 2285,8536 h75
  text "55 OHM" at 2935,8526 h75
  text "55 OHM" at 2935,8526 h75
  text "N/A" at 3935,8526 h75
  text "N/A" at 3935,8526 h75
  text "+/-10%" at 4685,8526 h75
  text "+/-10%" at 4685,8526 h75
  text "4.0" at 1620,8470 h75
  text "4.0" at 1620,8470 h75
  text "4" at 830,8460 h75
  text "4" at 830,8460 h75
  text "SOLDERMASK & SILKSCREEN" at 8880,8370 h60
  text "SOLDERMASK & SILKSCREEN" at 8880,8370 h60
  text "N/A" at 3040,8290 h75
  text "5.1" at 1615,8285 h75
  text "9.9" at 2265,8285 h75
  text "100 OHM" at 3850,8280 h75
  text "+/-10%" at 4685,8276 h75
  text "+/-10%" at 4685,8276 h75
  text "1,6" at 830,8275 h75
  text "TOP     (0.5 oz cu+planted)" at 8880,8250 h60
  text "TOP     (0.5 oz cu+planted)" at 8880,8250 h60
  text "PREPREG  3.9 mil" at 7560,8085 h60
  text "PREPREG  3.9 mil" at 7560,8085 h60
  text "90 OHM" at 3844,8034 h75
  text "+/-10%" at 4691,8032 h75
  text "6.1" at 1610,8025 h75
  text "8.9" at 2260,8020 h75
  text "N/A" at 3045,8011 h75
  text "1,6" at 835,8005 h75
  text "LAYER 2 (1 oz)" at 8880,7950 h60
  text "LAYER 2 (1 oz)" at 8880,7950 h60
  text "CORE     4  mil" at 7560,7850 h60
  text "CORE     4  mil" at 7560,7850 h60
  text "LAYER 3 (1 oz)" at 8880,7750 h60
  text "LAYER 3 (1 oz)" at 8880,7750 h60
  text "1.2 mm" at 6688,7677.5 h75
  text "1.2 mm" at 6688,7677.5 h75
  text "PREPREG  ** mil" at 7560,7585 h60
  text "PREPREG  ** mil" at 7560,7585 h60
  text "+/-10%" at 6730,7570 h50
  text "+/-10%" at 6730,7570 h50
  text "LAYER 4 (1 oz)" at 8880,7450 h60
  text "LAYER 4 (1 oz)" at 8880,7450 h60
  text "CORE     4  mil" at 7560,7350 h60
  text "CORE     4  mil" at 7560,7350 h60
  text "LAYER 5 (1 oz)" at 8880,7250 h60
  text "LAYER 5 (1 oz)" at 8880,7250 h60
  text "PREPREG  3.9 mil" at 7560,7085 h60
  text "PREPREG  3.9 mil" at 7560,7085 h60
  text "BOTTOM  (0.5 oz cu+planted)" at 8880,6950 h60
  text "BOTTOM  (0.5 oz cu+planted)" at 8880,6950 h60
  text "SOLDERMASK & SILKSCREEN" at 8880,6830 h60
  text "SOLDERMASK & SILKSCREEN" at 8880,6830 h60
  text "6 LAYER STACKING" at 7500,6650 h75
  text "6 LAYER STACKING" at 7500,6650 h75
  text "PCB SPECIFICATIONS:" at 10537,5421 h85
  text "PCB SPECIFICATIONS:" at 10537,5421 h85
  text "A. MATERIAL;" at 10537,5221 h85
  text "A. MATERIAL;" at 10537,5221 h85
  text "FR-4," at 12287,5221 h85
  text "FR-4," at 12287,5221 h85
  text "TG-170" at 13237,5221 h85
  text "TG-170" at 13237,5221 h85
  text "TG-150" at 13987,5221 h85
  text "TG-150" at 13987,5221 h85
  text "TG-140" at 14837,5221 h85
  text "TG-140" at 14837,5221 h85
  text "B. MATERIAL FAMILY;" at 10537,5021 h85
  text "B. MATERIAL FAMILY;" at 10537,5021 h85
  text "N/A." at 12287,5021 h85
  text "N/A." at 12287,5021 h85
  text "C. SOLDERMASK COLOR;" at 10537,4821 h85
  text "C. SOLDERMASK COLOR;" at 10537,4821 h85
  text "GREEN" at 12437,4821 h85
  text "GREEN" at 12437,4821 h85
  text "BLUE" at 13187,4821 h85
  text "BLUE" at 13187,4821 h85
  text "RED" at 14037,4821 h85
  text "RED" at 14037,4821 h85
  text "BLACK" at 14887,4821 h85
  text "BLACK" at 14887,4821 h85
  text "D. SILKSCREEN COLOR;" at 10537,4621 h85
  text "D. SILKSCREEN COLOR;" at 10537,4621 h85
  text "WHITE" at 12437,4621 h85
  text "WHITE" at 12437,4621 h85
  text "YELLOW" at 13187,4621 h85
  text "YELLOW" at 13187,4621 h85
  text "BLACK" at 14037,4621 h85
  text "BLACK" at 14037,4621 h85
  text "E. SURFACE FINISH;" at 10537,4421 h85
  text "E. SURFACE FINISH;" at 10537,4421 h85
  text "ENIG" at 12437,4421 h85
  text "ENIG" at 12437,4421 h85
  text "IMMERSION SILVER" at 13187,4421 h85
  text "IMMERSION SILVER" at 13187,4421 h85
  text "IMMERSION TIN" at 14887,4421 h85
  text "IMMERSION TIN" at 14887,4421 h85
  text "HASL" at 12437,4221 h85
  text "HASL" at 12437,4221 h85
  text "HASL(PB-FREE)" at 13187,4221 h85
  text "HASL(PB-FREE)" at 13187,4221 h85
  text "GOLDEN FINGER" at 14887,4221 h85
  text "GOLDEN FINGER" at 14887,4221 h85
  text "F. IMPEDANCE CONTROL;" at 10537,4021 h85
  text "F. IMPEDANCE CONTROL;" at 10537,4021 h85
  text "NO" at 12437,4021 h85
  text "NO" at 12437,4021 h85
  text "YES" at 13187,4021 h85
  text "YES" at 13187,4021 h85
  text "(SEE IMPEDANCE TABLE FOR DETAIL INFORMATION)" at 13387,4021 h85
  text "(SEE IMPEDANCE TABLE FOR DETAIL INFORMATION)" at 13387,4021 h85
  text "G. THROUGH VIA;" at 10537,3821 h85
  text "G. THROUGH VIA;" at 10537,3821 h85
  text "PLUG THE VIAS WHICH ARE COVERED WITH SOLDERMASK ONE OR TWO SIDE." at 11987,3821 h85
  text "PLUG THE VIAS WHICH ARE COVERED WITH SOLDERMASK ONE OR TWO SIDE." at 11987,3821 h85
  text "PLUG MATERIAL:" at 11987,3621 h85
  text "PLUG MATERIAL:" at 11987,3621 h85
  text "SOLDERMASK" at 13587,3621 h85
  text "SOLDERMASK" at 13587,3621 h85
  text "NON-CONDUCTIVE EPOXY." at 14887,3621 h85
  text "NON-CONDUCTIVE EPOXY." at 14887,3621 h85
  text "H. STACK-UP;" at 10537,3421 h85
  text "H. STACK-UP;" at 10537,3421 h85
  text "SEE LAYER STACK-UP SEQUENCE FOR OVERALL THICKNESS." at 11987,3421 h85
  text "SEE LAYER STACK-UP SEQUENCE FOR OVERALL THICKNESS." at 11987,3421 h85
  text "Symbol" at 5689.18,3351.82 h120
  text "Hit Count" at 6159.33,3351.82 h120
  text "Finished Hole Size" at 6721.8,3351.82 h120
  text "Plated" at 7728.89,3351.82 h120
  text "Hole Length" at 8141.6,3351.82 h120
  text "Routed Path Length" at 8829.28,3351.82 h120
  text "27" at 6159.33,3144.85 h100
  text "0,15mm" at 6721.8,3144.85 h100
  text "PTH" at 7728.89,3144.85 h100
  text "-" at 8141.6,3144.85 h100
  text "-" at 8829.28,3144.85 h100
  text "D" at 5651.65,3134.86 h91.99
  text "PCB REQUIREMENTS:" at 10527,3121 h85
  text "PCB REQUIREMENTS:" at 10527,3121 h85
  text "2" at 6159.33,2937.88 h100
  text "0,20mm" at 6721.8,2937.88 h100
  text "PTH" at 7728.89,2937.88 h100
  text "-" at 8141.6,2937.88 h100
  text "-" at 8829.28,2937.88 h100
  text "1. THIS BOARD WILL CONFORM TO:" at 10477,2921 h85
  text "1. THIS BOARD WILL CONFORM TO:" at 10477,2921 h85
  text "IPC-A-600. CURRENT REV., CLASS II" at 10477,2771 h85
  text "IPC-A-600. CURRENT REV., CLASS II" at 10477,2771 h85
  text "219" at 6159.33,2730.91 h100
  text "0,20mm" at 6721.8,2730.91 h100
  text "PTH" at 7728.89,2730.91 h100
  text "-" at 8141.6,2730.91 h100
  text "-" at 8829.28,2730.91 h100
  text "C" at 5651.65,2720.93 h91.99
  text "IPC-6012, CURRENT REV., CLASS II" at 10477,2621 h85
  text "IPC-6012, CURRENT REV., CLASS II" at 10477,2621 h85
  text "354" at 6159.33,2523.94 h100
  text "0,25mm" at 6721.8,2523.94 h100
  text "PTH" at 7728.89,2523.94 h100
  text "-" at 8141.6,2523.94 h100
  text "-" at 8829.28,2523.94 h100
  text "A" at 5651.65,2513.96 h91.99
  text "2. UNLESS OTHERWISE SPECIFIED ALL HOLE DIMENSIONS APPLY AFTER PLATING." at 10477,2411 h85
  text "2. UNLESS OTHERWISE SPECIFIED ALL HOLE DIMENSIONS APPLY AFTER PLATING." at 10477,2411 h85
  text "347" at 6159.33,2316.97 h100
  text "0,31mm" at 6721.8,2316.97 h100
  text "PTH" at 7728.89,2316.97 h100
  text "-" at 8141.6,2316.97 h100
  text "-" at 8829.28,2316.97 h100
  text "B" at 5651.65,2306.99 h91.99
  text "ALL HOLES SHALL BE LOCATED WITHIN .003\" DIAMETER OF TRUE POSITION." at 10477,2261 h85
  text "ALL HOLES SHALL BE LOCATED WITHIN .003\" DIAMETER OF TRUE POSITION." at 10477,2261 h85
  text "2" at 6159.33,2110 h100
  text "0,61mm" at 6721.8,2110 h100
  text "PTH" at 7728.89,2110 h100
  text "1,30mm" at 8141.6,2110 h100
  text "0,69mm" at 8829.28,2110 h100
  text "3. PLATED HOLE WALL THICKNESS SHALL NOT BE LESS THAN .001 INCH MINIMUM" at 10477,2061 h85
  text "3. PLATED HOLE WALL THICKNESS SHALL NOT BE LESS THAN .001 INCH MINIMUM" at 10477,2061 h85
  text "AVERAGE, WITH NO READING LESS THAN .0008 BY COROSS SECTION." at 10657,1921 h85
  text "AVERAGE, WITH NO READING LESS THAN .0008 BY COROSS SECTION." at 10657,1921 h85
  text "2" at 6159.33,1903.04 h100
  text "0,71mm" at 6721.8,1903.04 h100
  text "PTH" at 7728.89,1903.04 h100
  text "-" at 8141.6,1903.04 h100
  text "-" at 8829.28,1903.04 h100
  text "4. MATERIAL FR4 RATING 94V-0 MINIMUM EPOXY GLASS LAMINATE." at 10477,1711 h85
  text "4. MATERIAL FR4 RATING 94V-0 MINIMUM EPOXY GLASS LAMINATE." at 10477,1711 h85
  text "2" at 6159.33,1696.07 h100
  text "0,71mm" at 6721.8,1696.07 h100
  text "PTH" at 7728.89,1696.07 h100
  text "2,21mm" at 8141.6,1696.07 h100
  text "1,50mm" at 8829.28,1696.07 h100
  text "5. BOARD SHALL BE LPI SOLDER MASKED OVER BARE COPPER BOTH SIDES PER" at 10477,1531 h85
  text "5. BOARD SHALL BE LPI SOLDER MASKED OVER BARE COPPER BOTH SIDES PER" at 10477,1531 h85
  text "2" at 6159.33,1489.1 h100
  text "0,76mm" at 6721.8,1489.1 h100
  text "PTH" at 7728.89,1489.1 h100
  text "0,84mm" at 8141.6,1489.1 h100
  text "0,08mm" at 8829.28,1489.1 h100
  text "IPC-SM-840 CLASS II." at 10477,1381 h85
  text "IPC-SM-840 CLASS II." at 10477,1381 h85
  text "1" at 6159.33,1282.13 h100
  text "0,76mm" at 6721.8,1282.13 h100
  text "PTH" at 7728.89,1282.13 h100
  text "1,50mm" at 8141.6,1282.13 h100
  text "0,74mm" at 8829.28,1282.13 h100
  text "6. SILKSCREEN SHALL BE PERMANENT NON-CONDUCTIVE INK AND WITH NO OVERLAP" at 10477,1181 h85
  text "6. SILKSCREEN SHALL BE PERMANENT NON-CONDUCTIVE INK AND WITH NO OVERLAP" at 10477,1181 h85
  text "2" at 6159.33,1075.16 h100
  text "0,84mm" at 6721.8,1075.16 h100
  text "PTH" at 7728.89,1075.16 h100
  text "-" at 8141.6,1075.16 h100
  text "-" at 8829.28,1075.16 h100
  text "ON ANY COMPONENT PAD OR THROUGH HOLE." at 10477,1031 h85
  text "ON ANY COMPONENT PAD OR THROUGH HOLE." at 10477,1031 h85
  text "1" at 6159.33,868.19 h100
  text "0,84mm" at 6721.8,868.19 h100
  text "PTH" at 7728.89,868.19 h100
  text "1,50mm" at 8141.6,868.19 h100
  text "0,66mm" at 8829.28,868.19 h100
  text "E" at 5651.65,858.21 h91.99
  text "7. MFGR, TO LEGIBLY ETCH OR STAMP/SCREEN WITH PERMANENT NON-CONDUCTIVE INK" at 10477,831 h85
  text "7. MFGR, TO LEGIBLY ETCH OR STAMP/SCREEN WITH PERMANENT NON-CONDUCTIVE INK" at 10477,831 h85
  text "D. MFGR. LOGO" at 12327,701 h85
  text "D. MFGR. LOGO" at 12327,701 h85
  text "A. U.L. CODE" at 10767,681 h85
  text "A. U.L. CODE" at 10767,681 h85
  text "12" at 6159.33,661.22 h100
  text "0,89mm" at 6721.8,661.22 h100
  text "PTH" at 7728.89,661.22 h100
  text "-" at 8141.6,661.22 h100
  text "-" at 8829.28,661.22 h100
  text "E. SUCCESSFUL ELECTRICAL BOARD TEST." at 12327,561 h85
  text "E. SUCCESSFUL ELECTRICAL BOARD TEST." at 12327,561 h85
  text "B. DATE CODE" at 10767,541 h85
  text "B. DATE CODE" at 10767,541 h85
  text "22" at 6159.33,454.26 h100
  text "0,91mm" at 6721.8,454.26 h100
  text "PTH" at 7728.89,454.26 h100
  text "-" at 8141.6,454.26 h100
  text "-" at 8829.28,454.26 h100
  text "C. FLAMMABILITY RATING" at 10767,401 h85
  text "C. FLAMMABILITY RATING" at 10767,401 h85
  text "45" at 6159.33,247.29 h100
  text "1,02mm" at 6721.8,247.29 h100
  text "PTH" at 7728.89,247.29 h100
  text "-" at 8141.6,247.29 h100
  text "-" at 8829.28,247.29 h100
  text "8. REMOVE THE FLASHS WHICH SMALLER THAN HOLE SIZE." at 10477,191 h85
  text "8. REMOVE THE FLASHS WHICH SMALLER THAN HOLE SIZE." at 10477,191 h85
  text "2" at 6159.33,40.32 h100
  text "1,07mm" at 6721.8,40.32 h100
  text "PTH" at 7728.89,40.32 h100
  text "1,47mm" at 8141.6,40.32 h100
  text "0,41mm" at 8829.28,40.32 h100
  text "9. REMOVE ALL SHAPE EDGES AND BURRS .005 MAXIMUM." at 10477,-9 h85
  text "9. REMOVE ALL SHAPE EDGES AND BURRS .005 MAXIMUM." at 10477,-9 h85
  text "4" at 6159.33,-166.65 h100
  text "2,01mm" at 6721.8,-166.65 h100
  text "PTH" at 7728.89,-166.65 h100
  text "-" at 8141.6,-166.65 h100
  text "-" at 8829.28,-166.65 h100
  text "10. PLEASE USE THE SUPPLIED IPC 356 NETLIST TO VERIFY BOARD BEFORE" at 10477,-219 h85
  text "10. PLEASE USE THE SUPPLIED IPC 356 NETLIST TO VERIFY BOARD BEFORE" at 10477,-219 h85
  text "FABRICATING BOARD." at 10477,-369 h85
  text "FABRICATING BOARD." at 10477,-369 h85
  text "4" at 6159.33,-373.62 h100
  text "3,51mm" at 6721.8,-373.62 h100
  text "PTH" at 7728.89,-373.62 h100
  text "-" at 8141.6,-373.62 h100
  text "-" at 8829.28,-373.62 h100
  text "4" at 6159.33,-580.59 h100
  text "4,50mm" at 6721.8,-580.59 h100
  text "PTH" at 7728.89,-580.59 h100
  text "-" at 8141.6,-580.59 h100
  text "-" at 8829.28,-580.59 h100
  text "1054 Total" at 6159.33,-787.56 h100
  text "Slot definitions :" at 5689.18,-932.44 h100
  text "Routed Path Length" at 6371.21,-932.44 h100
  text "= Calculated from tool start centre position to tool end centre position." at 7216.12,-932.44 h100
  text "Hole Length" at 6371.21,-1015.22 h100
  text "= Routed Path Length + Tool Size = Slot length as defined in the PCB layout" at 6902.46,-1015.22 h100
LAY6:
  the board outline again, w6
DFA_BOUND_BOTTOM:
  circle w1: c0,0 r100
  circle w1: c0,0 r100
  lines w1: -150,0 150,0 -150,0 ; 0,-150 0,150 0,-150

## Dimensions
4793,3259 to 4793,2801 on M2-Board Dimensions
4792,3259 to 5000,3465 on M2-Board Dimensions
4794,194 to 5000,-1 on M2-Board Dimensions
206,2809 to 4793,2801 on M2-Board Dimensions
208,1320 to 206,2809 on M2-Board Dimensions
195,193 to 208,1320 on M2-Board Dimensions
5000,-1 to 5001,1705 on M2-Board Dimensions
5001,2255 to 5001,1705 on M2-Board Dimensions
5000,3465 to 5001,2255 on M2-Board Dimensions
-1,0 to 5000,-1 on M2-Board Dimensions
2815,3474.56 to 5000,3465 on M2-Board Dimensions
2360,3464.56 to 2815,3464.56 on M2-Board Dimensions
0,3465 to 2360,3464.56 on M2-Board Dimensions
